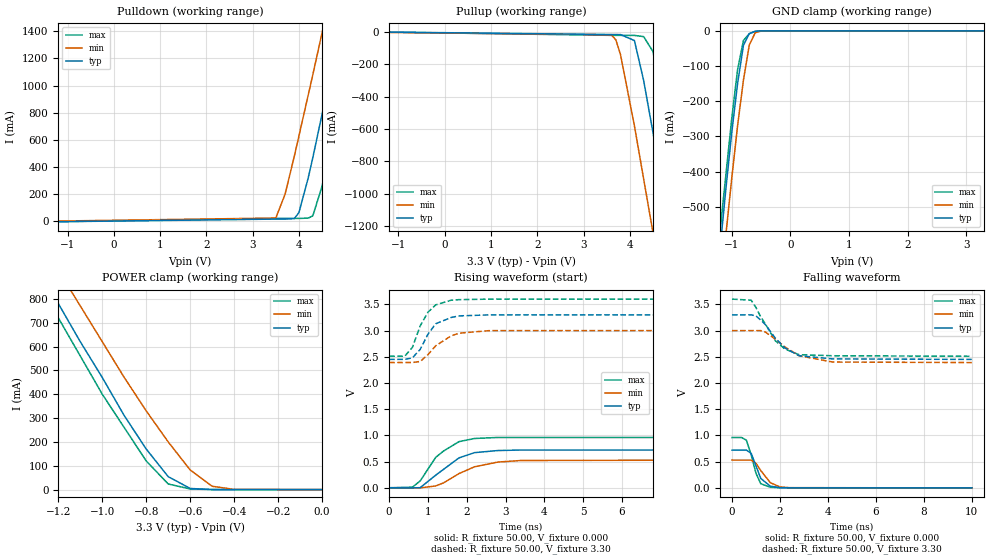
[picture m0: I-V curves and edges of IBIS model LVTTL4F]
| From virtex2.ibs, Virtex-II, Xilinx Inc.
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|   Model LVTTL4F
[Model]   LVTTL4F
Model_type   I/O
Polarity   Non-Inverting
Enable   Active-Low
Vinh = 2.0V
Vinl = 0.8V
Vmeas =   1.40V
Cref =  0pF
Rref =   1.00M
Vref =  0.000V
C_comp   10.00pF   10.00pF   10.00pF
[Temperature Range]   25.00   100.00   0.000
[Voltage Range]   3.30V   3.00V   3.60V
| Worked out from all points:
|   slope of the pulldown table from 0 to 0.495 V, typ, clamps not added: 64.8 ohm
|   slope of the pullup table from 0 to 0.495 V, typ, clamps not added: 95.5 ohm
|   GND clamp passes 1 mA (typ) near -0.57 V on its own axis
|   POWER clamp passes 1 mA (typ) near -0.52 V on its own axis
|   rising waveform, R_fixture 50.00, V_fixture 0.000: 20-80 % time 753ps typ, 888ps min, 672ps max; typ from 0 V to 0.72 V
|   rising waveform, R_fixture 50.00, V_fixture 3.30: 20-80 % time 425ps typ, 594ps min, 422ps max; typ from 2.45 V to 3.3 V
|   falling waveform, R_fixture 50.00, V_fixture 0.000: 20-80 % time 412ps typ, 520ps min, 386ps max; typ from 0.72 V to 0 V
|   falling waveform, R_fixture 50.00, V_fixture 3.30: 20-80 % time 1.01ns typ, 1.16ns min, 918ps max; typ from 3.3 V to 2.45 V
[Pulldown]
| voltage   I(typ)   I(min)   I(max)
-3.3V     -10.77mA   -7.22mA    -12.39mA
3.5V      17.22mA    24.99mA    22.01mA
3.7V      17.28mA    200mA      22.05mA
3.9V      21.2mA     480mA      22.09mA
4V        65.53mA    630mA      22.12mA
4.2V      320mA      930mA      24.26mA
4.3V      470mA      1.08A      41.45mA
4.5V      790mA      1.39A      260mA
4.9V      1.43A      2.01A      890mA
5.1V      1.76A      2.33A      1.21A
5.3V      2.09A      2.64A      1.54A
6.6V      4.26A      4.7A       3.7A
[Pullup]
| voltage   I(typ)   I(min)   I(max)
-3.3V     6.76mA     3.9mA      8.28mA
3.6V      -15.07mA   -16.2mA    -20.1mA
3.7V      -15.12mA   -48.43mA   -20.17mA
3.8V      -15.26mA   -140mA     -20.23mA
4.1V      -52.21mA   -580mA     -20.5mA
4.3V      -300mA     -910mA     -27.9mA
4.5V      -620mA     -1.24A     -120mA
4.7V      -960mA     -1.58A     -410mA
4.9V      -1.3A      -1.91A     -750mA
5.1V      -1.65A     -2.25A     -1.09A
5.3V      -2A        -2.6A      -1.43A
6.6V      -4.31A     -4.84A     -3.73A
[GND_clamp]
| voltage   I(typ)   I(min)   I(max)
-3.3V     -4.3A      -4.31A     -4.26A
-1.2V     -620mA     -740mA     -570mA
-1.1V     -450mA     -580mA     -410mA
-1V       -290mA     -420mA     -250mA
-900mV    -150mA     -270mA     -110mA
-800mV    -41.03mA   -140mA     -27.28mA
-700mV    -7.6mA     -40.21mA   -8.18mA
-600mV    -1.42mA    -5.61mA    -1.62mA
-500mV    -130uA     -670uA     -130uA
3.3V      67.85pA    43.48uA    45.6pA
[POWER_clamp]
| voltage   I(typ)   I(min)   I(max)
-3.3V     4.25A      4.22A      4.2A
-1.3V     940mA      1.07A      880mA
-1.2V     780mA      920mA      720mA
-1.1V     620mA      770mA      560mA
-1V       470mA      620mA      400mA
-900mV    310mA      470mA      260mA
-800mV    170mA      330mA      120mA
-700mV    54.34mA    200mA      23.62mA
-600mV    4.76mA     82.21mA    2.52mA
-500mV    280uA      14.02mA    260uA
-400mV    16.9uA     860uA      14.85uA
0V        67.85pA    2.04nA     61.89pA
[Ramp]
| variable   typ   min   max
dV/dt_r   0.43/0.69n   0.32/0.87n   0.58/0.60n
dV/dt_f   0.51/0.98n   0.37/1.21n   0.65/0.84n
R_load = 50.00
[Rising Waveform]
R_fixture = 50.00
V_fixture = 0.000
| time   V(typ)   V(min)   V(max)
0s        0V         0V         0V
600ps     -2.08mV    -200uV     11.19mV
800ps     1.27mV     -2.1mV     130mV
1.2ns     240mV      34.86mV    580mV
1.4ns     350mV      91.91mV    700mV
1.8ns     570mV      270mV      880mV
2.2ns     670mV      400mV      940mV
2.8ns     710mV      490mV      960mV
3.4ns     720mV      520mV      960mV
10ns      720mV      530mV      960mV
[Rising Waveform]
R_fixture = 50.00
V_fixture = 3.30
V_fixture_min = 3.00
V_fixture_max = 3.60
| time   V(typ)   V(min)   V(max)
0s        2.45V      2.39V      2.51V
400ps     2.45V      2.39V      2.51V
600ps     2.48V      2.39V      2.68V
800ps     2.64V      2.41V      3.09V
1ns       2.93V      2.54V      3.35V
1.2ns     3.13V      2.71V      3.49V
1.6ns     3.25V      2.9V       3.58V
1.8ns     3.28V      2.95V      3.59V
2.6ns     3.3V       3V         3.6V
10ns      3.3V       3V         3.6V
[Falling Waveform]
R_fixture = 50.00
V_fixture = 0.000
| time   V(typ)   V(min)   V(max)
0s        720mV      530mV      960mV
400ps     720mV      530mV      960mV
600ps     720mV      530mV      910mV
800ps     660mV      530mV      630mV
1ns       420mV      470mV      280mV
1.2ns     180mV      330mV      79.39mV
1.6ns     31.69mV    98.14mV    11.24mV
2ns       4.12mV     18.37mV    1.29mV
2.4ns     830uV      3.64mV     310uV
10ns      3.35uV     4.12uV     2.23uV
[Falling Waveform]
R_fixture = 50.00
V_fixture = 3.30
V_fixture_min = 3.00
V_fixture_max = 3.60
| time   V(typ)   V(min)   V(max)
0s        3.3V       3V         3.6V
800ps     3.3V       3V         3.58V
1ns       3.28V      3V         3.44V
1.2ns     3.2V       3V         3.26V
1.4ns     3.11V      2.97V      3.12V
1.8ns     2.86V      2.84V      2.81V
2.2ns     2.67V      2.69V      2.65V
2.8ns     2.52V      2.52V      2.54V
4.2ns     2.46V      2.4V       2.52V
10ns      2.45V      2.39V      2.51V
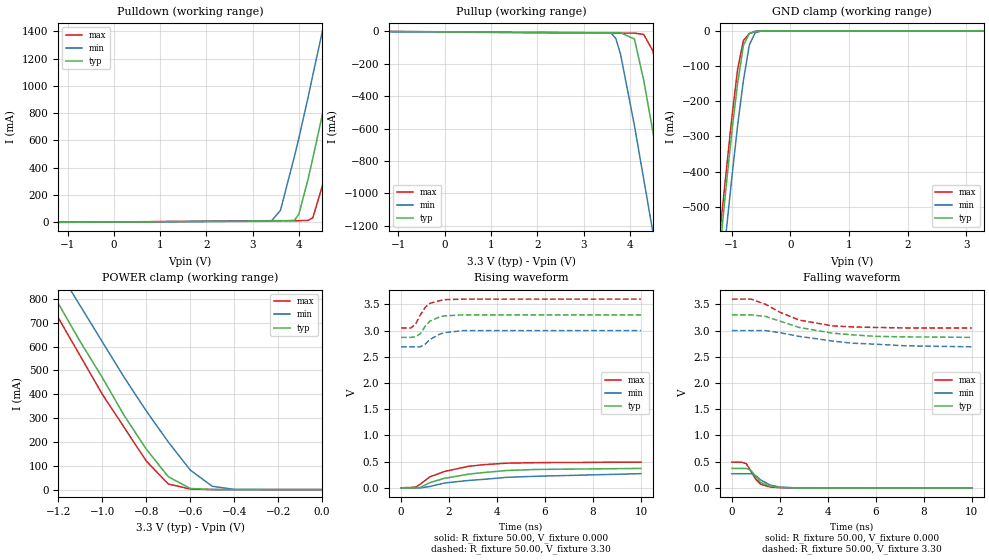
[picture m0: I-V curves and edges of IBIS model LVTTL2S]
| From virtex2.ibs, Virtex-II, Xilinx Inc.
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|   Model LVTTL2S
[Model]   LVTTL2S
Model_type   I/O
Polarity   Non-Inverting
Enable   Active-Low
Vinh = 2.0V
Vinl = 0.8V
Vmeas =   1.40V
Cref =  0pF
Rref =   1.00M
Vref =  0.000V
C_comp   10.00pF   10.00pF   10.00pF
[Temperature Range]   25.00   100.00   0.000
[Voltage Range]   3.30V   3.00V   3.60V
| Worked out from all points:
|   slope of the pulldown table from 0 to 0.495 V, typ, clamps not added: 127 ohm
|   slope of the pullup table from 0 to 0.495 V, typ, clamps not added: 191 ohm
|   GND clamp passes 1 mA (typ) near -0.57 V on its own axis
|   POWER clamp passes 1 mA (typ) near -0.52 V on its own axis
|   rising waveform, R_fixture 50.00, V_fixture 0.000: 20-80 % time 2.43ns typ, 3.86ns min, 1.75ns max; typ from 0 V to 0.37 V
|   rising waveform, R_fixture 50.00, V_fixture 3.30: 20-80 % time 547ps typ, 627ps min, 481ps max; typ from 2.87 V to 3.3 V
|   falling waveform, R_fixture 50.00, V_fixture 0.000: 20-80 % time 485ps typ, 557ps min, 445ps max; typ from 0.37 V to 0 V
|   falling waveform, R_fixture 50.00, V_fixture 3.30: 20-80 % time 2.31ns typ, 3.04ns min, 1.76ns max; typ from 3.3 V to 2.87 V
[Pulldown]
| voltage   I(typ)   I(min)   I(max)
-3.3V     -5.48mA    -3.66mA    -6.34mA
3.4V      8.68mA     7.12mA     11.12mA
3.6V      8.7mA      86.09mA    11.15mA
3.9V      13.03mA    480mA      11.18mA
4V        59.94mA    620mA      11.2mA
4.2V      320mA      920mA      13.51mA
4.3V      470mA      1.08A      32.54mA
4.5V      780mA      1.39A      260mA
4.9V      1.43A      2.01A      880mA
5.1V      1.76A      2.32A      1.21A
5.3V      2.09A      2.64A      1.54A
6.6V      4.26A      4.7A       3.7A
[Pullup]
| voltage   I(typ)   I(min)   I(max)
-3.3V     3.38mA     1.95mA     4.15mA
3.6V      -7.53mA    -10.9mA    -10.05mA
3.7V      -7.56mA    -44.3mA    -10.08mA
3.8V      -7.7mA     -140mA     -10.12mA
4.1V      -46.57mA   -580mA     -10.31mA
4.3V      -300mA     -910mA     -18.03mA
4.5V      -620mA     -1.24A     -120mA
4.7V      -960mA     -1.57A     -410mA
4.9V      -1.3A      -1.91A     -740mA
5.1V      -1.65A     -2.25A     -1.08A
5.3V      -2A        -2.59A     -1.43A
6.6V      -4.3A      -4.83A     -3.73A
[GND_clamp]
| voltage   I(typ)   I(min)   I(max)
-3.3V     -4.3A      -4.31A     -4.26A
-1.2V     -620mA     -740mA     -570mA
-1.1V     -450mA     -580mA     -410mA
-1V       -290mA     -420mA     -250mA
-900mV    -150mA     -270mA     -110mA
-800mV    -41.03mA   -140mA     -27.28mA
-700mV    -7.6mA     -40.21mA   -8.18mA
-600mV    -1.42mA    -5.61mA    -1.62mA
-500mV    -130uA     -670uA     -130uA
3.3V      67.85pA    43.48uA    45.6pA
[POWER_clamp]
| voltage   I(typ)   I(min)   I(max)
-3.3V     4.25A      4.22A      4.2A
-1.3V     940mA      1.07A      880mA
-1.2V     780mA      920mA      720mA
-1.1V     620mA      770mA      560mA
-1V       470mA      620mA      400mA
-900mV    310mA      470mA      260mA
-800mV    170mA      330mA      120mA
-700mV    54.34mA    200mA      23.62mA
-600mV    4.76mA     82.21mA    2.52mA
-500mV    280uA      14.02mA    260uA
-400mV    16.9uA     860uA      14.85uA
0V        67.85pA    2.04nA     61.89pA
[Ramp]
| variable   typ   min   max
dV/dt_r   0.22/2.35n   0.16/3.54n   0.30/1.75n
dV/dt_f   0.26/2.28n   0.18/2.95n   0.33/1.84n
R_load = 50.00
[Rising Waveform]
R_fixture = 50.00
V_fixture = 0.000
| time   V(typ)   V(min)   V(max)
0s        0V         530nV      0V
600ps     -700uV     -26.34uV   11.48mV
800ps     6.24mV     -870uV     71.23mV
1.2ns     99.9mV     25.12mV    210mV
1.8ns     180mV      90.4mV     310mV
2.8ns     260mV      140mV      410mV
3.4ns     290mV      160mV      440mV
4.4ns     330mV      200mV      470mV
5.6ns     350mV      220mV      480mV
10ns      370mV      270mV      490mV
[Rising Waveform]
R_fixture = 50.00
V_fixture = 3.30
V_fixture_min = 3.00
V_fixture_max = 3.60
| time   V(typ)   V(min)   V(max)
0s        2.87V      2.69V      3.05V
400ps     2.87V      2.69V      3.05V
600ps     2.88V      2.69V      3.12V
800ps     2.94V      2.69V      3.3V
1ns       3.08V      2.74V      3.44V
1.2ns     3.18V      2.83V      3.52V
1.6ns     3.26V      2.93V      3.57V
1.8ns     3.28V      2.96V      3.59V
2.6ns     3.3V       3V         3.6V
10ns      3.3V       3V         3.6V
[Falling Waveform]
R_fixture = 50.00
V_fixture = 0.000
| time   V(typ)   V(min)   V(max)
0s        370mV      270mV      490mV
400ps     370mV      270mV      490mV
600ps     370mV      270mV      460mV
800ps     330mV      270mV      310mV
1ns       210mV      230mV      160mV
1.2ns     100mV      150mV      68.41mV
1.6ns     29.86mV    52.35mV    16.7mV
2ns       6.52mV     14.14mV    3.15mV
2.6ns     950uV      2.13mV     600uV
10ns      6.68uV     17.14uV    4.21uV
[Falling Waveform]
R_fixture = 50.00
V_fixture = 3.30
V_fixture_min = 3.00
V_fixture_max = 3.60
| time   V(typ)   V(min)   V(max)
0s        3.3V       3V         3.6V
800ps     3.3V       3V         3.6V
1.4ns     3.27V      3V         3.5V
2ns       3.18V      2.96V      3.35V
2.8ns     3.06V      2.89V      3.2V
4.2ns     2.95V      2.8V       3.09V
5ns       2.92V      2.76V      3.07V
6ns       2.89V      2.74V      3.06V
7.2ns     2.88V      2.71V      3.05V
10ns      2.87V      2.69V      3.05V
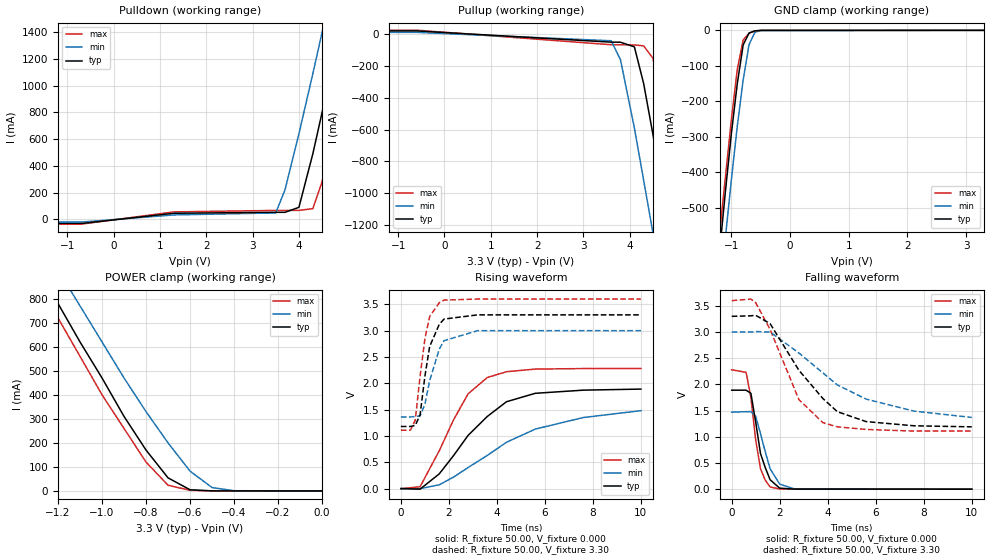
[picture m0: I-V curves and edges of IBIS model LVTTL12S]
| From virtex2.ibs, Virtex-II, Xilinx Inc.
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|   Model LVTTL12S
[Model]   LVTTL12S
Model_type   I/O
Polarity   Non-Inverting
Enable   Active-Low
Vinh = 2.0V
Vinl = 0.8V
Vmeas =   1.40V
Cref =  0pF
Rref =   1.00M
Vref =  0.000V
C_comp   10.00pF   10.00pF   10.00pF
[Temperature Range]   25.00   100.00   0.000
[Voltage Range]   3.30V   3.00V   3.60V
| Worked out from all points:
|   slope of the pulldown table from 0 to 0.495 V, typ, clamps not added: 21.8 ohm
|   slope of the pullup table from 0 to 0.495 V, typ, clamps not added: 29.6 ohm
|   GND clamp passes 1 mA (typ) near -0.57 V on its own axis
|   POWER clamp passes 1 mA (typ) near -0.52 V on its own axis
|   rising waveform, R_fixture 50.00, V_fixture 0.000: 20-80 % time 2.2ns typ, 3.54ns min, 1.54ns max; typ from 0 V to 1.89 V
|   rising waveform, R_fixture 50.00, V_fixture 3.30: 20-80 % time 497ps typ, 588ps min, 448ps max; typ from 1.18 V to 3.3 V
|   falling waveform, R_fixture 50.00, V_fixture 0.000: 20-80 % time 512ps typ, 571ps min, 407ps max; typ from 1.89 V to 0 V
|   falling waveform, R_fixture 50.00, V_fixture 3.30: 20-80 % time 2.06ns typ, 3.11ns min, 1.39ns max; typ from 3.3 V to 1.19 V
[Pulldown]
| voltage   I(typ)   I(min)   I(max)
-3.3V     -32.1mA    -21.58mA   -36.83mA
-700mV    -32.1mA    -21.58mA   -36.83mA
1.3V      44.67mA    32.07mA    55.03mA
3.5V      51.66mA    47.4mA     66.01mA
3.7V      51.79mA    220mA      66.14mA
4V        89.06mA    640mA      66.32mA
4.3V      490mA      1.09A      79.21mA
4.5V      800mA      1.4A       280mA
4.9V      1.45A      2.02A      900mA
5.1V      1.78A      2.34A      1.23A
5.3V      2.11A      2.65A      1.56A
6.6V      4.27A      4.71A      3.72A
[Pullup]
| voltage   I(typ)   I(min)   I(max)
-3.3V     21.9mA     12.73mA    26.65mA
-600mV    21.9mA     12.73mA    26.65mA
3.6V      -48.95mA   -40.18mA   -65.29mA
3.8V      -49.31mA   -160mA     -65.71mA
4.1V      -78.6mA    -590mA     -66.32mA
4.3V      -310mA     -920mA     -72.41mA
4.5V      -630mA     -1.25A     -150mA
4.7V      -970mA     -1.58A     -430mA
4.9V      -1.32A     -1.92A     -760mA
5.1V      -1.66A     -2.26A     -1.1A
5.3V      -2.01A     -2.6A      -1.45A
6.6V      -4.32A     -4.84A     -3.74A
[GND_clamp]
| voltage   I(typ)   I(min)   I(max)
-3.3V     -4.3A      -4.31A     -4.26A
-1.2V     -620mA     -740mA     -570mA
-1.1V     -450mA     -580mA     -410mA
-1V       -290mA     -420mA     -250mA
-900mV    -150mA     -270mA     -110mA
-800mV    -41.03mA   -140mA     -27.28mA
-700mV    -7.6mA     -40.21mA   -8.18mA
-600mV    -1.42mA    -5.61mA    -1.62mA
-500mV    -130uA     -670uA     -130uA
3.3V      67.85pA    43.48uA    45.6pA
[POWER_clamp]
| voltage   I(typ)   I(min)   I(max)
-3.3V     4.25A      4.22A      4.2A
-1.3V     940mA      1.07A      880mA
-1.2V     780mA      920mA      720mA
-1.1V     620mA      770mA      560mA
-1V       470mA      620mA      400mA
-900mV    310mA      470mA      260mA
-800mV    170mA      330mA      120mA
-700mV    54.34mA    200mA      23.62mA
-600mV    4.76mA     82.21mA    2.52mA
-500mV    280uA      14.02mA    260uA
-400mV    16.9uA     860uA      14.85uA
0V        67.85pA    2.04nA     61.89pA
[Ramp]
| variable   typ   min   max
dV/dt_r   1.13/2.21n   0.86/3.37n   1.37/1.56n
dV/dt_f   1.27/2.08n   0.96/3.00n   1.50/1.44n
R_load = 50.00
[Rising Waveform]
R_fixture = 50.00
V_fixture = 0.000
| time   V(typ)   V(min)   V(max)
0s        0V         0V         0V
800ps     -10.81mV   -1.76mV    34.91mV
1.6ns     280mV      71.85mV    720mV
2.2ns     630mV      220mV      1.31V
2.8ns     1.01V      400mV      1.8V
3.6ns     1.37V      630mV      2.11V
4.4ns     1.65V      880mV      2.22V
5.6ns     1.81V      1.13V      2.27V
7.6ns     1.87V      1.35V      2.28V
10ns      1.89V      1.48V      2.28V
[Rising Waveform]
R_fixture = 50.00
V_fixture = 3.30
V_fixture_min = 3.00
V_fixture_max = 3.60
| time   V(typ)   V(min)   V(max)
0s        1.18V      1.36V      1.11V
400ps     1.18V      1.36V      1.11V
600ps     1.2V       1.37V      1.3V
800ps     1.4V       1.38V      2.13V
1ns       2.13V      1.6V       2.84V
1.2ns     2.7V       2.05V      3.27V
1.6ns     3.12V      2.65V      3.53V
1.8ns     3.22V      2.81V      3.58V
3.2ns     3.3V       3V         3.6V
10ns      3.3V       3V         3.6V
[Falling Waveform]
R_fixture = 50.00
V_fixture = 0.000
| time   V(typ)   V(min)   V(max)
0s        1.89V      1.47V      2.28V
600ps     1.89V      1.48V      2.23V
800ps     1.83V      1.48V      1.75V
1ns       1.28V      1.39V      940mV
1.2ns     680mV      1.06V      390mV
1.4ns     410mV      710mV      170mV
1.6ns     180mV      390mV      42.75mV
2ns       18.75mV    95.16mV    2.56mV
2.6ns     1.66mV     6.68mV     1.25mV
10ns      23.01uV    70.16uV    7.96uV
[Falling Waveform]
R_fixture = 50.00
V_fixture = 3.30
V_fixture_min = 3.00
V_fixture_max = 3.60
| time   V(typ)   V(min)   V(max)
0s        3.3V       3V         3.6V
800ps     3.31V      3V         3.63V
1ns       3.32V      3.01V      3.56V
1.6ns     3.16V      3V         3.05V
2.8ns     2.27V      2.6V       1.71V
3.8ns     1.73V      2.22V      1.27V
4.4ns     1.48V      1.99V      1.19V
5.6ns     1.29V      1.72V      1.14V
7.6ns     1.21V      1.49V      1.11V
10ns      1.19V      1.37V      1.11V
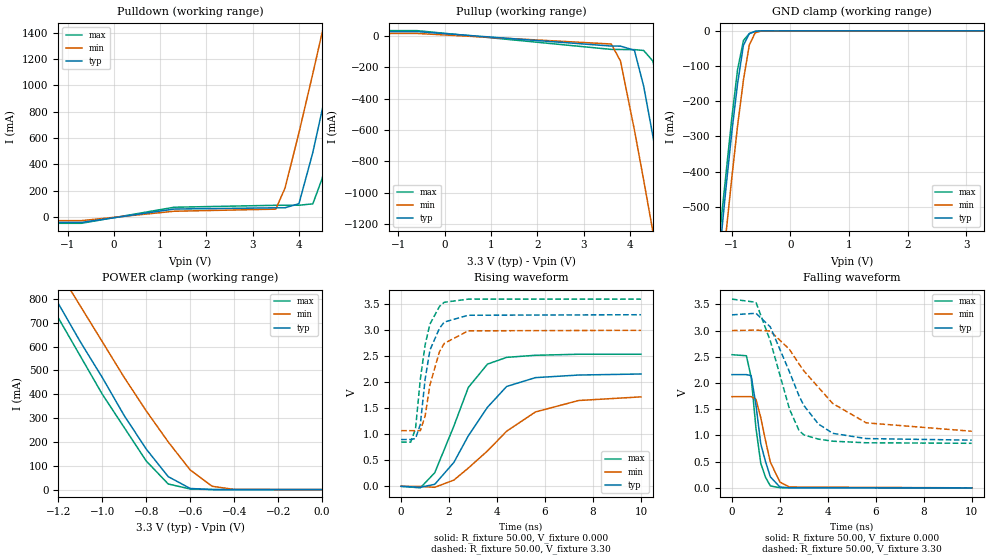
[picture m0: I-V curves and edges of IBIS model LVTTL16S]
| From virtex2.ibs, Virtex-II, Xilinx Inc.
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|   Model LVTTL16S
[Model]   LVTTL16S
Model_type   I/O
Polarity   Non-Inverting
Enable   Active-Low
Vinh = 2.0V
Vinl = 0.8V
Vmeas =   1.40V
Cref =  0pF
Rref =   1.00M
Vref =  0.000V
C_comp   10.00pF   10.00pF   10.00pF
[Temperature Range]   25.00   100.00   0.000
[Voltage Range]   3.30V   3.00V   3.60V
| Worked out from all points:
|   slope of the pulldown table from 0 to 0.495 V, typ, clamps not added: 16.5 ohm
|   slope of the pullup table from 0 to 0.495 V, typ, clamps not added: 22.7 ohm
|   GND clamp passes 1 mA (typ) near -0.57 V on its own axis
|   POWER clamp passes 1 mA (typ) near -0.52 V on its own axis
|   rising waveform, R_fixture 50.00, V_fixture 0.000: 20-80 % time 1.84ns typ, 2.63ns min, 1.31ns max; typ from 0 V to 2.16 V
|   rising waveform, R_fixture 50.00, V_fixture 3.30: 20-80 % time 530ps typ, 595ps min, 504ps max; typ from 0.9 V to 3.3 V
|   falling waveform, R_fixture 50.00, V_fixture 0.000: 20-80 % time 500ps typ, 548ps min, 373ps max; typ from 2.16 V to 0 V
|   falling waveform, R_fixture 50.00, V_fixture 3.30: 20-80 % time 1.45ns typ, 2.18ns min, 1.04ns max; typ from 3.3 V to 0.91 V
[Pulldown]
| voltage   I(typ)   I(min)   I(max)
-3.3V     -42.66mA   -28.71mA   -48.88mA
-700mV    -42.66mA   -28.71mA   -48.88mA
1.3V      59.43mA    42.7mA     73.14mA
3.5V      68.88mA    58.81mA    88.01mA
3.7V      69.04mA    220mA      88.18mA
4V        100mA      640mA      88.42mA
4.3V      490mA      1.09A      98.99mA
4.5V      810mA      1.4A       290mA
4.9V      1.45A      2.03A      910mA
5.1V      1.78A      2.34A      1.24A
5.3V      2.11A      2.66A      1.56A
6.6V      4.28A      4.72A      3.72A
[Pullup]
| voltage   I(typ)   I(min)   I(max)
-3.3V     28.6mA     16.68mA    34.69mA
-600mV    28.6mA     16.68mA    34.69mA
3.6V      -63.99mA   -50.9mA    -85.36mA
3.8V      -64.43mA   -160mA     -85.91mA
4.1V      -90.87mA   -600mA     -86.68mA
4.3V      -320mA     -920mA     -92.25mA
4.5V      -640mA     -1.25A     -160mA
4.7V      -980mA     -1.59A     -440mA
4.9V      -1.32A     -1.93A     -770mA
5.1V      -1.67A     -2.27A     -1.11A
5.3V      -2.02A     -2.61A     -1.46A
6.6V      -4.32A     -4.85A     -3.75A
[GND_clamp]
| voltage   I(typ)   I(min)   I(max)
-3.3V     -4.3A      -4.31A     -4.26A
-1.2V     -620mA     -740mA     -570mA
-1.1V     -450mA     -580mA     -410mA
-1V       -290mA     -420mA     -250mA
-900mV    -150mA     -270mA     -110mA
-800mV    -41.03mA   -140mA     -27.28mA
-700mV    -7.6mA     -40.21mA   -8.18mA
-600mV    -1.42mA    -5.61mA    -1.62mA
-500mV    -130uA     -670uA     -130uA
3.3V      67.85pA    43.48uA    45.6pA
[POWER_clamp]
| voltage   I(typ)   I(min)   I(max)
-3.3V     4.25A      4.22A      4.2A
-1.3V     940mA      1.07A      880mA
-1.2V     780mA      920mA      720mA
-1.1V     620mA      770mA      560mA
-1V       470mA      620mA      400mA
-900mV    310mA      470mA      260mA
-800mV    170mA      330mA      120mA
-700mV    54.34mA    200mA      23.62mA
-600mV    4.76mA     82.21mA    2.52mA
-500mV    280uA      14.02mA    260uA
-400mV    16.9uA     860uA      14.85uA
0V        67.85pA    2.04nA     61.89pA
[Ramp]
| variable   typ   min   max
dV/dt_r   1.29/1.83n   1.03/2.65n   1.52/1.35n
dV/dt_f   1.44/1.44n   1.15/2.23n   1.65/1.03n
R_load = 50.00
[Rising Waveform]
R_fixture = 50.00
V_fixture = 0.000
| time   V(typ)   V(min)   V(max)
0s        0V         0V         0V
800ps     -18.47mV   -1.57mV    -29.99mV
1.4ns     37.83mV    -19.32mV   260mV
2.2ns     460mV      120mV      1.16V
2.8ns     970mV      350mV      1.9V
3.6ns     1.52V      680mV      2.35V
4.4ns     1.92V      1.06V      2.48V
5.6ns     2.09V      1.43V      2.52V
7.4ns     2.14V      1.65V      2.54V
10ns      2.16V      1.72V      2.54V
[Rising Waveform]
R_fixture = 50.00
V_fixture = 3.30
V_fixture_min = 3.00
V_fixture_max = 3.60
| time   V(typ)   V(min)   V(max)
0s        900mV      1.07V      850mV
400ps     900mV      1.07V      850mV
600ps     920mV      1.07V      1.11V
800ps     1.19V      1.07V      2.06V
1ns       2.06V      1.35V      2.72V
1.2ns     2.62V      1.95V      3.12V
1.6ns     3.04V      2.59V      3.46V
1.8ns     3.16V      2.75V      3.54V
2.8ns     3.29V      2.99V      3.6V
10ns      3.3V       3V         3.6V
[Falling Waveform]
R_fixture = 50.00
V_fixture = 0.000
| time   V(typ)   V(min)   V(max)
0s        2.16V      1.74V      2.54V
600ps     2.16V      1.74V      2.52V
800ps     2.14V      1.74V      2.11V
1ns       1.58V      1.69V      1.14V
1.2ns     840mV      1.34V      470mV
1.4ns     500mV      900mV      200mV
1.6ns     210mV      490mV      36.83mV
2ns       14.92mV    110mV      2.43mV
2.4ns     2.24mV     16.23mV    1.64mV
10ns      7.85uV     40.04uV    2.89uV
[Falling Waveform]
R_fixture = 50.00
V_fixture = 3.30
V_fixture_min = 3.00
V_fixture_max = 3.60
| time   V(typ)   V(min)   V(max)
0s        3.3V       3V         3.6V
1ns       3.33V      3.01V      3.54V
1.6ns     3.07V      2.99V      2.8V
2.4ns     2.21V      2.64V      1.5V
2.8ns     1.75V      2.36V      1.09V
3ns       1.57V      2.23V      1.01V
3.6ns     1.22V      1.92V      930mV
4.2ns     1.04V      1.61V      890mV
5.6ns     940mV      1.24V      860mV
10ns      910mV      1.08V      850mV
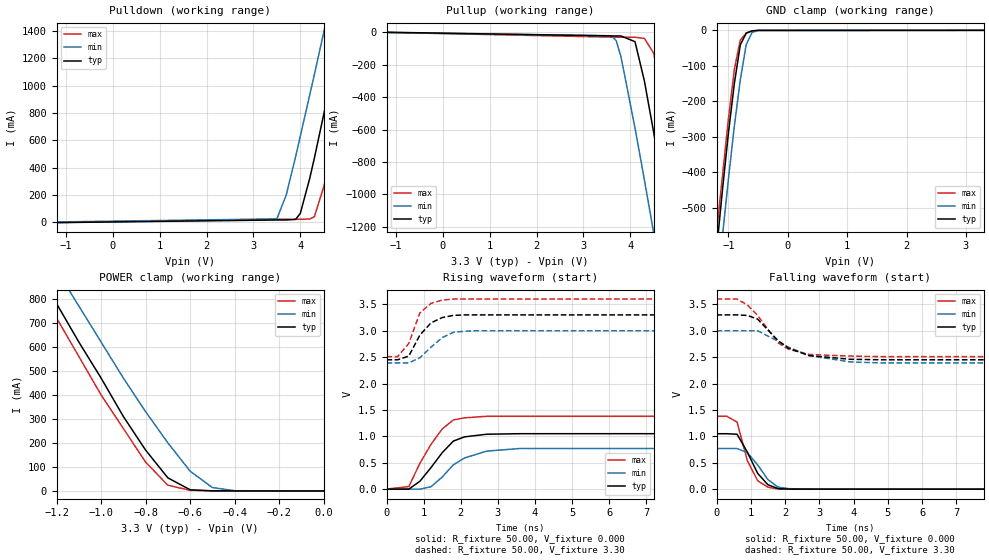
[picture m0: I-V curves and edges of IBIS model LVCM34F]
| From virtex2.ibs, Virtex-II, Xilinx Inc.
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|   Model LVCM34F
[Model]   LVCM34F
Model_type   I/O
Polarity   Non-Inverting
Enable   Active-Low
Vinh = 2.0V
Vinl = 0.8V
Vmeas =   1.65V
Cref =  0pF
Rref =   1.00M
Vref =  0.000V
C_comp   10.00pF   10.00pF   10.00pF
[Temperature Range]   25.00   100.00   0.000
[Voltage Range]   3.30V   3.00V   3.60V
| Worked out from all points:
|   slope of the pulldown table from 0 to 0.495 V, typ, clamps not added: 64.8 ohm
|   slope of the pullup table from 0 to 0.495 V, typ, clamps not added: 63.8 ohm
|   GND clamp passes 1 mA (typ) near -0.57 V on its own axis
|   POWER clamp passes 1 mA (typ) near -0.52 V on its own axis
|   rising waveform, R_fixture 50.00, V_fixture 0.000: 20-80 % time 735ps typ, 821ps min, 708ps max; typ from 0 V to 1.05 V
|   rising waveform, R_fixture 50.00, V_fixture 3.30: 20-80 % time 499ps typ, 591ps min, 408ps max; typ from 2.45 V to 3.3 V
|   falling waveform, R_fixture 50.00, V_fixture 0.000: 20-80 % time 548ps typ, 558ps min, 440ps max; typ from 1.05 V to 0 V
|   falling waveform, R_fixture 50.00, V_fixture 3.30: 20-80 % time 925ps typ, 1.19ns min, 843ps max; typ from 3.3 V to 2.45 V
[Pulldown]
| voltage   I(typ)   I(min)   I(max)
-3.3V     -10.77mA   -7.22mA    -12.39mA
3.5V      17.22mA    24.99mA    22.01mA
3.7V      17.28mA    200mA      22.05mA
3.9V      21.2mA     480mA      22.09mA
4V        65.53mA    630mA      22.12mA
4.2V      320mA      930mA      24.26mA
4.3V      470mA      1.08A      41.45mA
4.5V      790mA      1.39A      260mA
4.9V      1.43A      2.01A      890mA
5.1V      1.76A      2.33A      1.21A
5.3V      2.09A      2.64A      1.54A
6.6V      4.26A      4.7A       3.7A
[Pullup]
| voltage   I(typ)   I(min)   I(max)
-3.3V     10.13mA    5.86mA     12.39mA
3.6V      -22.6mA    -21.51mA   -30.15mA
3.7V      -22.67mA   -52.6mA    -30.25mA
3.8V      -22.83mA   -150mA     -30.34mA
4.1V      -57.92mA   -590mA     -30.68mA
4.3V      -300mA     -910mA     -37.77mA
4.5V      -620mA     -1.24A     -130mA
4.7V      -960mA     -1.58A     -420mA
4.9V      -1.31A     -1.92A     -750mA
5.1V      -1.66A     -2.26A     -1.09A
5.3V      -2.01A     -2.6A      -1.44A
6.6V      -4.31A     -4.84A     -3.73A
[GND_clamp]
| voltage   I(typ)   I(min)   I(max)
-3.3V     -4.3A      -4.31A     -4.26A
-1.2V     -620mA     -740mA     -570mA
-1.1V     -450mA     -580mA     -410mA
-1V       -290mA     -420mA     -250mA
-900mV    -150mA     -270mA     -110mA
-800mV    -41.03mA   -140mA     -27.28mA
-700mV    -7.6mA     -40.21mA   -8.18mA
-600mV    -1.42mA    -5.61mA    -1.62mA
-500mV    -130uA     -670uA     -130uA
3.3V      67.85pA    43.48uA    45.6pA
[POWER_clamp]
| voltage   I(typ)   I(min)   I(max)
-3.3V     4.25A      4.22A      4.2A
-1.3V     940mA      1.07A      880mA
-1.2V     780mA      920mA      720mA
-1.1V     620mA      770mA      560mA
-1V       470mA      620mA      400mA
-900mV    310mA      470mA      260mA
-800mV    170mA      330mA      120mA
-700mV    54.34mA    200mA      23.62mA
-600mV    4.76mA     82.21mA    2.52mA
-500mV    280uA      14.02mA    260uA
-400mV    16.9uA     860uA      14.85uA
0V        67.85pA    2.04nA     61.89pA
[Ramp]
| variable   typ   min   max
dV/dt_r   0.63/0.69n   0.46/0.86n   0.83/0.58n
dV/dt_f   0.51/0.98n   0.37/1.21n   0.65/0.85n
R_load = 50.00
[Rising Waveform]
R_fixture = 50.00
V_fixture = 0.000
| time   V(typ)   V(min)   V(max)
0s        0V         0V         0V
600ps     400uV      -280uV     49.26mV
900ps     150mV      -470uV     490mV
1.2ns     410mV      45.71mV    850mV
1.5ns     690mV      230mV      1.14V
1.8ns     910mV      460mV      1.31V
2.1ns     990mV      590mV      1.35V
2.7ns     1.04V      720mV      1.38V
3.6ns     1.05V      770mV      1.38V
15ns      1.05V      770mV      1.38V
[Rising Waveform]
R_fixture = 50.00
V_fixture = 3.30
V_fixture_min = 3.00
V_fixture_max = 3.60
| time   V(typ)   V(min)   V(max)
0s        2.45V      2.39V      2.51V
300ps     2.45V      2.39V      2.51V
600ps     2.52V      2.39V      2.76V
900ps     2.92V      2.49V      3.34V
1.2ns     3.15V      2.69V      3.52V
1.5ns     3.25V      2.87V      3.58V
1.8ns     3.29V      2.97V      3.6V
2.1ns     3.3V       2.99V      3.6V
2.4ns     3.3V       3V         3.6V
15ns      3.3V       3V         3.6V
[Falling Waveform]
R_fixture = 50.00
V_fixture = 0.000
| time   V(typ)   V(min)   V(max)
0s        1.05V      770mV      1.38V
300ps     1.05V      770mV      1.38V
600ps     1.04V      770mV      1.27V
900ps     700mV      690mV      540mV
1.2ns     300mV      460mV      160mV
1.5ns     83.87mV    180mV      37.44mV
1.8ns     10.26mV    37.81mV    1.95mV
2.1ns     1.97mV     9.84mV     530uV
2.7ns     290uV      1.01mV     110uV
15ns      2uV        2.58uV     2.72uV
[Falling Waveform]
R_fixture = 50.00
V_fixture = 3.30
V_fixture_min = 3.00
V_fixture_max = 3.60
| time   V(typ)   V(min)   V(max)
0s        3.3V       3V         3.6V
600ps     3.3V       3V         3.6V
900ps     3.29V      3V         3.49V
1.2ns     3.22V      3V         3.29V
1.8ns     2.81V      2.8V       2.77V
2.1ns     2.67V      2.69V      2.65V
2.7ns     2.53V      2.53V      2.55V
3.9ns     2.46V      2.41V      2.52V
4.8ns     2.45V      2.39V      2.51V
15ns      2.45V      2.39V      2.51V
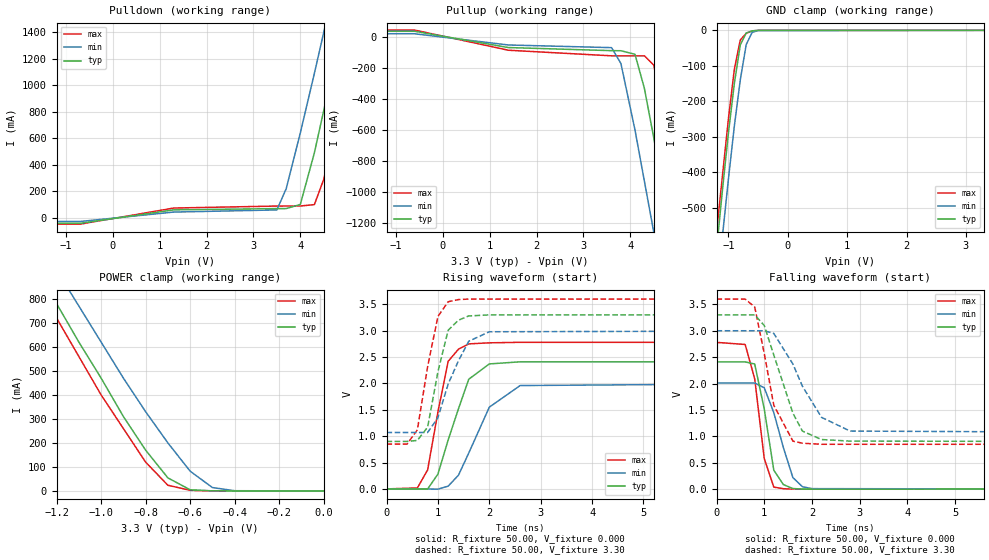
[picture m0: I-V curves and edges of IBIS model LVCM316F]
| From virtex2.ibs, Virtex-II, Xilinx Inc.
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|   Model LVCM316F
[Model]   LVCM316F
Model_type   I/O
Polarity   Non-Inverting
Enable   Active-Low
Vinh = 2.0V
Vinl = 0.8V
Vmeas =   1.65V
Cref =  0pF
Rref =   1.00M
Vref =  0.000V
C_comp   10.00pF   10.00pF   10.00pF
[Temperature Range]   25.00   100.00   0.000
[Voltage Range]   3.30V   3.00V   3.60V
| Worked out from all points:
|   slope of the pulldown table from 0 to 0.495 V, typ, clamps not added: 16.5 ohm
|   slope of the pullup table from 0 to 0.495 V, typ, clamps not added: 16.9 ohm
|   GND clamp passes 1 mA (typ) near -0.57 V on its own axis
|   POWER clamp passes 1 mA (typ) near -0.52 V on its own axis
|   rising waveform, R_fixture 50.00, V_fixture 0.000: 20-80 % time 484ps typ, 581ps min, 324ps max; typ from 0 V to 2.41 V
|   rising waveform, R_fixture 50.00, V_fixture 3.30: 20-80 % time 312ps typ, 466ps min, 307ps max; typ from 0.9 V to 3.3 V
|   falling waveform, R_fixture 50.00, V_fixture 0.000: 20-80 % time 275ps typ, 403ps min, 250ps max; typ from 2.41 V to 0 V
|   falling waveform, R_fixture 50.00, V_fixture 3.30: 20-80 % time 535ps typ, 648ps min, 397ps max; typ from 3.3 V to 0.9 V
[Pulldown]
| voltage   I(typ)   I(min)   I(max)
-3.3V     -42.66mA   -28.71mA   -48.88mA
-700mV    -42.66mA   -28.71mA   -48.88mA
1.3V      59.43mA    42.7mA     73.14mA
3.5V      68.88mA    58.81mA    88.01mA
3.7V      69.04mA    220mA      88.18mA
4V        100mA      640mA      88.42mA
4.3V      490mA      1.09A      98.99mA
4.5V      810mA      1.4A       290mA
4.9V      1.45A      2.03A      910mA
5.1V      1.78A      2.34A      1.24A
5.3V      2.11A      2.66A      1.56A
6.6V      4.28A      4.72A      3.72A
[Pullup]
| voltage   I(typ)   I(min)   I(max)
-3.3V     38.58mA    22.62mA    46.62mA
-600mV    38.58mA    22.62mA    46.62mA
1.4V      -66.48mA   -49.89mA   -83.88mA
3.6V      -86.56mA   -67.02mA   -120mA
3.8V      -87.11mA   -170mA     -120mA
4.1V      -110mA     -600mA     -120mA
4.3V      -330mA     -930mA     -120mA
4.5V      -650mA     -1.26A     -180mA
4.9V      -1.33A     -1.93A     -780mA
5.1V      -1.68A     -2.27A     -1.12A
5.3V      -2.03A     -2.61A     -1.46A
6.6V      -4.33A     -4.85A     -3.76A
[GND_clamp]
| voltage   I(typ)   I(min)   I(max)
-3.3V     -4.3A      -4.31A     -4.26A
-1.2V     -620mA     -740mA     -570mA
-1.1V     -450mA     -580mA     -410mA
-1V       -290mA     -420mA     -250mA
-900mV    -150mA     -270mA     -110mA
-800mV    -41.03mA   -140mA     -27.28mA
-700mV    -7.6mA     -40.21mA   -8.18mA
-600mV    -1.42mA    -5.61mA    -1.62mA
-500mV    -130uA     -670uA     -130uA
3.3V      67.85pA    43.48uA    45.6pA
[POWER_clamp]
| voltage   I(typ)   I(min)   I(max)
-3.3V     4.25A      4.22A      4.2A
-1.3V     940mA      1.07A      880mA
-1.2V     780mA      920mA      720mA
-1.1V     620mA      770mA      560mA
-1V       470mA      620mA      400mA
-900mV    310mA      470mA      260mA
-800mV    170mA      330mA      120mA
-700mV    54.34mA    200mA      23.62mA
-600mV    4.76mA     82.21mA    2.52mA
-500mV    280uA      14.02mA    260uA
-400mV    16.9uA     860uA      14.85uA
0V        67.85pA    2.04nA     61.89pA
[Ramp]
| variable   typ   min   max
dV/dt_r   1.45/0.40n   1.20/0.55n   1.67/0.31n
dV/dt_f   1.44/0.45n   1.16/0.63n   1.65/0.35n
R_load = 50.00
[Rising Waveform]
R_fixture = 50.00
V_fixture = 0.000
| time   V(typ)   V(min)   V(max)
0s        0V         0V         0V
600ps     -2.99mV    52.17uV    18.17mV
800ps     -1.05mV    -2mV       360mV
1ns       280mV      -5mV       1.46V
1.2ns     930mV      52.91mV    2.42V
1.4ns     1.52V      260mV      2.65V
1.6ns     2.08V      680mV      2.75V
2ns       2.37V      1.55V      2.77V
2.6ns     2.41V      1.96V      2.78V
10ns      2.41V      2.01V      2.78V
[Rising Waveform]
R_fixture = 50.00
V_fixture = 3.30
V_fixture_min = 3.00
V_fixture_max = 3.60
| time   V(typ)   V(min)   V(max)
0s        900mV      1.07V      850mV
400ps     900mV      1.07V      850mV
600ps     920mV      1.07V      1.12V
800ps     1.17V      1.07V      2.32V
1ns       2.22V      1.35V      3.27V
1.2ns     3.01V      1.99V      3.55V
1.4ns     3.2V       2.43V      3.59V
1.6ns     3.28V      2.8V       3.6V
2ns       3.3V       2.98V      3.6V
10ns      3.3V       3V         3.6V
[Falling Waveform]
R_fixture = 50.00
V_fixture = 0.000
| time   V(typ)   V(min)   V(max)
0s        2.41V      2.01V      2.78V
600ps     2.41V      2.01V      2.74V
800ps     2.37V      2.01V      2.09V
1ns       1.52V      1.92V      580mV
1.2ns     360mV      1.45V      39.34mV
1.4ns     87.06mV    790mV      8.72mV
1.6ns     11.5mV     220mV      1.47mV
1.8ns     2.57mV     46.08mV    630uV
2ns       920uV      9.92mV     270uV
10ns      980nV      2.32uV     -4.81uV
[Falling Waveform]
R_fixture = 50.00
V_fixture = 3.30
V_fixture_min = 3.00
V_fixture_max = 3.60
| time   V(typ)   V(min)   V(max)
0s        3.3V       3V         3.6V
600ps     3.3V       3V         3.6V
800ps     3.3V       3V         3.45V
1ns       3.1V       3V         2.57V
1.2ns     2.54V      2.95V      1.59V
1.6ns     1.44V      2.37V      910mV
1.8ns     1.1V       1.95V      870mV
2.2ns     940mV      1.36V      850mV
2.8ns     910mV      1.1V       850mV
10ns      900mV      1.07V      850mV
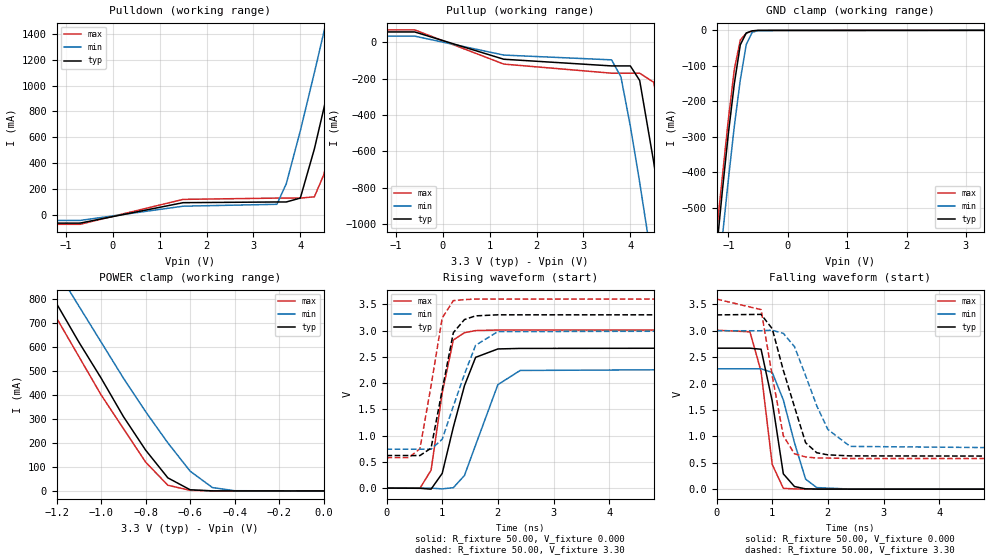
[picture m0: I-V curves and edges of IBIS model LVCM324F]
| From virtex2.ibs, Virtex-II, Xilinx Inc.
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|   Model LVCM324F
[Model]   LVCM324F
Model_type   I/O
Polarity   Non-Inverting
Enable   Active-Low
Vinh = 2.0V
Vinl = 0.8V
Vmeas =   1.65V
Cref =  0pF
Rref =   1.00M
Vref =  0.000V
C_comp   10.00pF   10.00pF   10.00pF
[Temperature Range]   25.00   100.00   0.000
[Voltage Range]   3.30V   3.00V   3.60V
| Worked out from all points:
|   slope of the pulldown table from 0 to 0.495 V, typ, clamps not added: 11.1 ohm
|   slope of the pullup table from 0 to 0.495 V, typ, clamps not added: 11.5 ohm
|   GND clamp passes 1 mA (typ) near -0.57 V on its own axis
|   POWER clamp passes 1 mA (typ) near -0.52 V on its own axis
|   rising waveform, R_fixture 50.00, V_fixture 0.000: 20-80 % time 411ps typ, 465ps min, 283ps max; typ from 0 V to 2.67 V
|   rising waveform, R_fixture 50.00, V_fixture 3.30: 20-80 % time 293ps typ, 454ps min, 290ps max; typ from 0.62 V to 3.3 V
|   falling waveform, R_fixture 50.00, V_fixture 0.000: 20-80 % time 260ps typ, 374ps min, 232ps max; typ from 2.67 V to 0 V
|   falling waveform, R_fixture 50.00, V_fixture 3.30: 20-80 % time 449ps typ, 517ps min, 305ps max; typ from 3.3 V to 0.62 V
[Pulldown]
| voltage   I(typ)   I(min)   I(max)
-3.3V     -63.55mA   -42.85mA   -72.64mA
-700mV    -63.55mA   -42.85mA   -72.64mA
1.5V      94.54mA    67.4mA     120mA
3.5V      100mA      82mA       130mA
3.7V      100mA      240mA      130mA
4V        130mA      650mA      130mA
4.3V      510mA      1.1A       140mA
4.5V      820mA      1.41A      310mA
4.9V      1.47A      2.04A      930mA
5.1V      1.79A      2.35A      1.25A
5.3V      2.12A      2.67A      1.58A
6.6V      4.29A      4.73A      3.74A
[Pullup]
| voltage   I(typ)   I(min)   I(max)
-3.3V     56.69mA    33.54mA    68.06mA
-600mV    56.69mA    33.54mA    68.06mA
1.3V      -93.32mA   -70.46mA   -120mA
3.6V      -130mA     -96.72mA   -170mA
3.8V      -130mA     -190mA     -170mA
4V        -130mA     -460mA     -170mA
4.2V      -210mA     -770mA     -170mA
4.5V      -660mA     -1.27A     -220mA
4.9V      -1.34A     -1.94A     -800mA
5.1V      -1.69A     -2.28A     -1.14A
5.3V      -2.04A     -2.62A     -1.48A
6.6V      -4.34A     -4.86A     -3.78A
[GND_clamp]
| voltage   I(typ)   I(min)   I(max)
-3.3V     -4.3A      -4.31A     -4.26A
-1.2V     -620mA     -740mA     -570mA
-1.1V     -450mA     -580mA     -410mA
-1V       -290mA     -420mA     -250mA
-900mV    -150mA     -270mA     -110mA
-800mV    -41.03mA   -140mA     -27.28mA
-700mV    -7.6mA     -40.21mA   -8.18mA
-600mV    -1.42mA    -5.61mA    -1.62mA
-500mV    -130uA     -670uA     -130uA
3.3V      67.85pA    43.48uA    45.6pA
[POWER_clamp]
| voltage   I(typ)   I(min)   I(max)
-3.3V     4.25A      4.22A      4.2A
-1.3V     940mA      1.07A      880mA
-1.2V     780mA      920mA      720mA
-1.1V     620mA      770mA      560mA
-1V       470mA      620mA      400mA
-900mV    310mA      470mA      260mA
-800mV    170mA      330mA      120mA
-700mV    54.34mA    200mA      23.62mA
-600mV    4.76mA     82.21mA    2.52mA
-500mV    280uA      14.02mA    260uA
-400mV    16.9uA     860uA      14.85uA
0V        67.85pA    2.04nA     61.89pA
[Ramp]
| variable   typ   min   max
dV/dt_r   1.60/0.31n   1.37/0.44n   1.81/0.24n
dV/dt_f   1.61/0.36n   1.36/0.50n   1.81/0.28n
R_load = 50.00
[Rising Waveform]
R_fixture = 50.00
V_fixture = 0.000
| time   V(typ)   V(min)   V(max)
0s        0V         0V         0V
600ps     -3.4mV     110uV      -3.67mV
800ps     -20.51mV   -1.36mV    340mV
1ns       280mV      -15.14mV   1.81V
1.2ns     1.16V      7.51mV     2.82V
1.4ns     1.95V      240mV      2.96V
1.6ns     2.49V      820mV      3V
2ns       2.65V      1.97V      3.01V
2.4ns     2.66V      2.24V      3.01V
10ns      2.67V      2.28V      3.01V
[Rising Waveform]
R_fixture = 50.00
V_fixture = 3.30
V_fixture_min = 3.00
V_fixture_max = 3.60
| time   V(typ)   V(min)   V(max)
0s        620mV      740mV      580mV
400ps     620mV      740mV      580mV
600ps     620mV      740mV      750mV
800ps     760mV      740mV      1.95V
1ns       1.87V      930mV      3.24V
1.2ns     2.96V      1.56V      3.57V
1.4ns     3.21V      2.17V      3.59V
1.6ns     3.28V      2.72V      3.6V
2ns       3.3V       2.98V      3.6V
10ns      3.3V       3V         3.6V
[Falling Waveform]
R_fixture = 50.00
V_fixture = 0.000
| time   V(typ)   V(min)   V(max)
0s        2.67V      2.28V      3.01V
600ps     2.67V      2.28V      2.98V
800ps     2.65V      2.28V      2.23V
1ns       1.67V      2.21V      470mV
1.2ns     290mV      1.69V      16.04mV
1.4ns     49.91mV    880mV      4.63mV
1.6ns     6.1mV      190mV      1.52mV
1.8ns     2.09mV     30.01mV    660uV
2.4ns     280uV      1.39mV     67.14uV
10ns      2.82uV     -2.06uV    6.36uV
[Falling Waveform]
R_fixture = 50.00
V_fixture = 3.30
V_fixture_min = 3.00
V_fixture_max = 3.60
| time   V(typ)   V(min)   V(max)
0s        3.3V       3V         3.6V
800ps     3.31V      3V         3.4V
1ns       3.04V      3.01V      2.15V
1.2ns     2.25V      2.95V      1.01V
1.4ns     1.56V      2.7V       670mV
1.6ns     880mV      2.15V      610mV
1.8ns     690mV      1.58V      590mV
2ns       650mV      1.13V      590mV
2.4ns     630mV      810mV      580mV
10ns      620mV      740mV      580mV
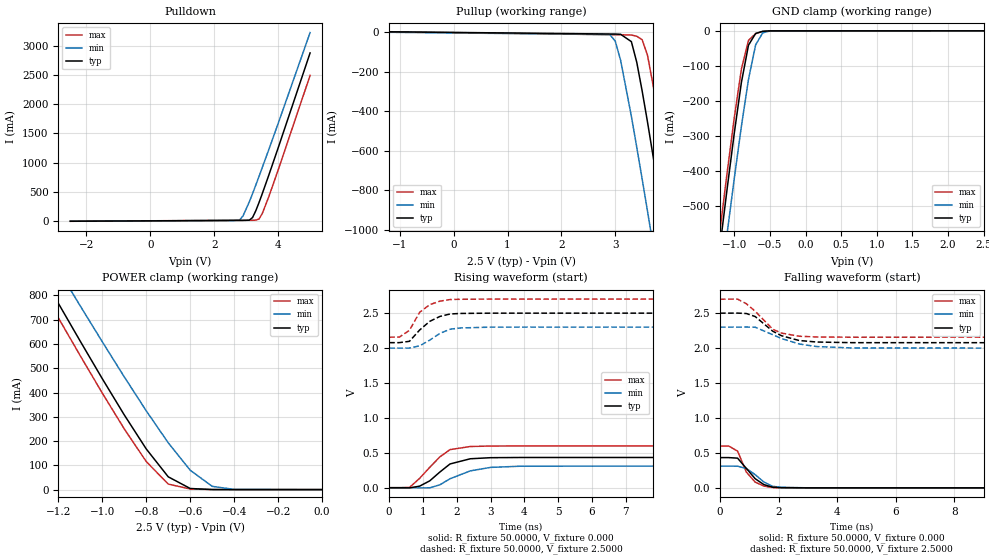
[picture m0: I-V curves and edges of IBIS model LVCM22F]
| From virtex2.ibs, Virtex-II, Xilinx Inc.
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|   Model LVCM22F
[Model]   LVCM22F
Model_type   I/O
Polarity   Non-Inverting
Enable   Active-Low
Vinh = 1.7V
Vinl = 0.7V
Vmeas =   1.2500V
Cref =  0pF
Rref =   1.0000M
Vref =  0.000V
C_comp   7.0000pF   6.0000pF   8.0000pF
[Temperature Range]   25.0000   100.0000   0.000
[Voltage Range]   2.5000V   2.3000V   2.7000V
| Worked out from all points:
|   slope of the pulldown table from 0 to 0.375 V, typ, clamps not added: 122 ohm
|   slope of the pullup table from 0 to 0.375 V, typ, clamps not added: 116 ohm
|   GND clamp passes 1 mA (typ) near -0.57 V on its own axis
|   POWER clamp passes 1 mA (typ) near -0.52 V on its own axis
|   rising waveform, R_fixture 50.0000, V_fixture 0.000: 20-80 % time 684ps typ, 900ps min, 739ps max; typ from 0 V to 0.433 V
|   rising waveform, R_fixture 50.0000, V_fixture 2.5000: 20-80 % time 622ps typ, 653ps min, 505ps max; typ from 2.08 V to 2.5 V
|   falling waveform, R_fixture 50.0000, V_fixture 0.000: 20-80 % time 596ps typ, 605ps min, 475ps max; typ from 0.433 V to 0 V
|   falling waveform, R_fixture 50.0000, V_fixture 2.5000: 20-80 % time 896ps typ, 1.11ns min, 809ps max; typ from 2.5 V to 2.08 V
[Pulldown]
| voltage   I(typ)   I(min)   I(max)
-2.5V     -5.481mA   -3.66mA    -6.342mA
2.6V      8.571mA    6.23mA     11mA
2.8V      8.605mA    18.9mA     11.04mA
2.9V      8.633mA    83.75mA    11.06mA
3.1V      12.78mA    327.5mA    11.1mA
3.2V      58.36mA    467.2mA    11.32mA
3.3V      171.9mA    611.7mA    13.35mA
3.4V      311.3mA    758.9mA    31.74mA
3.5V      460.3mA    908mA      121.4mA
3.7V      770.7mA    1.209A     402.1mA
4V        1.249A     1.668A     870.2mA
5V        2.877A     3.226A     2.492A
[Pullup]
| voltage   I(typ)   I(min)   I(max)
-2.5V     5.869mA    3.31mA     7.396mA
2.9V      -9.073mA   -11.85mA   -12.55mA
3V        -9.217mA   -45.04mA   -12.6mA
3.1V      -10.44mA   -142mA     -12.65mA
3.3V      -47.69mA   -425.5mA   -14.17mA
3.4V      -152.4mA   -582.2mA   -20.41mA
3.5V      -297mA     -743mA     -38.14mA
3.6V      -455.4mA   -906.4mA   -116.8mA
3.8V      -788.3mA   -1.238A    -410.7mA
4V        -1.13A     -1.574A    -743.1mA
4.2V      -1.477A    -1.913A    -1.085A
5V        -2.884A    -3.282A    -2.488A
[GND_clamp]
| voltage   I(typ)   I(min)   I(max)
-2.5V     -2.881A    -2.936A    -2.838A
-1.2V     -617mA     -740.6mA   -570.6mA
-1.1V     -452.1mA   -579.7mA   -406.1mA
-1V       -293.4mA   -423mA     -249mA
-900mV    -148mA     -273.4mA   -110.1mA
-800mV    -41mA      -138.5mA   -27.22mA
-700mV    -7.569mA   -40.19mA   -8.128mA
-600mV    -1.403mA   -5.589mA   -1.597mA
-500mV    -127.6uA   -662.5uA   -122uA
2.5V      397.5nA    2.548uA    351.3nA
[POWER_clamp]
| voltage   I(typ)   I(min)   I(max)
-2.5V     2.874A     2.908A     2.816A
-1.3V     925.8mA    1.055A     866.1mA
-1.2V     767.5mA    905.5mA    707.7mA
-1.1V     610.9mA    756.3mA    551.2mA
-1V       456.9mA    609.1mA    397.6mA
-900mV    307.7mA    464.5mA    250.2mA
-800mV    167.5mA    324.6mA    115.6mA
-700mV    52.75mA    192.9mA    22.81mA
-600mV    4.571mA    79.88mA    2.444mA
-500mV    271.3uA    13.45mA    251.8uA
-400mV    16.93uA    820.9uA    15.04uA
0V        397.5nA    368nA      428.7nA
[Ramp]
| variable   typ   min   max
dV/dt_r   0.2598/0.7377n   0.1865/0.9257n   0.3590/0.6380n
dV/dt_f   0.2538/0.9437n   0.1806/1.1440n   0.3270/0.8292n
R_load = 50.0000
[Rising Waveform]
R_fixture = 50.0000
V_fixture = 0.000
| time   V(typ)   V(min)   V(max)
0s        14.97uV    15.8uV     15.19uV
600ps     -1.679mV   -36.34uV   3.043mV
900ps     22.16mV    -2.088mV   133.4mV
1.2ns     98.34mV    -1.759mV   291.9mV
1.5ns     224.7mV    41.66mV    441.5mV
1.8ns     340.1mV    128.2mV    545.6mV
2.4ns     414.5mV    241.2mV    590mV
3ns       429.9mV    290.8mV    596.7mV
3.9ns     432.8mV    308.3mV    598mV
15ns      433.1mV    310.8mV    598.4mV
[Rising Waveform]
R_fixture = 50.0000
V_fixture = 2.5000
V_fixture_min = 2.3000
V_fixture_max = 2.7000
| time   V(typ)   V(min)   V(max)
0s        2.077V     1.999V     2.155V
300ps     2.077V     1.999V     2.156V
600ps     2.096V     1.999V     2.253V
900ps     2.257V     2.031V     2.511V
1.2ns     2.382V     2.113V     2.621V
1.5ns     2.452V     2.209V     2.671V
1.8ns     2.487V     2.269V     2.694V
2.1ns     2.495V     2.287V     2.698V
3ns       2.499V     2.299V     2.7V
15ns      2.5V       2.3V       2.7V
[Falling Waveform]
R_fixture = 50.0000
V_fixture = 0.000
| time   V(typ)   V(min)   V(max)
0s        433.1mV    310.8mV    598.4mV
300ps     433.1mV    310.8mV    598.5mV
600ps     425.1mV    310.4mV    525.7mV
900ps     278.3mV    277.1mV    225.1mV
1.2ns     131mV      188.9mV    82.29mV
1.5ns     46.23mV    82.79mV    25.35mV
1.8ns     8.845mV    21.84mV    4.019mV
2.1ns     2.591mV    7.985mV    964.4uV
3ns       114.5uV    414.1uV    46.86uV
15ns      1.966uV    2.77uV     2.285uV
[Falling Waveform]
R_fixture = 50.0000
V_fixture = 2.5000
V_fixture_min = 2.3000
V_fixture_max = 2.7000
| time   V(typ)   V(min)   V(max)
0s        2.5V       2.3V       2.7V
600ps     2.501V     2.3V       2.701V
900ps     2.495V     2.302V     2.635V
1.2ns     2.452V     2.299V     2.528V
1.8ns     2.242V     2.192V     2.27V
2.1ns     2.177V     2.137V     2.215V
2.7ns     2.109V     2.059V     2.17V
3.3ns     2.087V     2.022V     2.159V
4.5ns     2.078V     2.002V     2.156V
15ns      2.077V     1.999V     2.155V
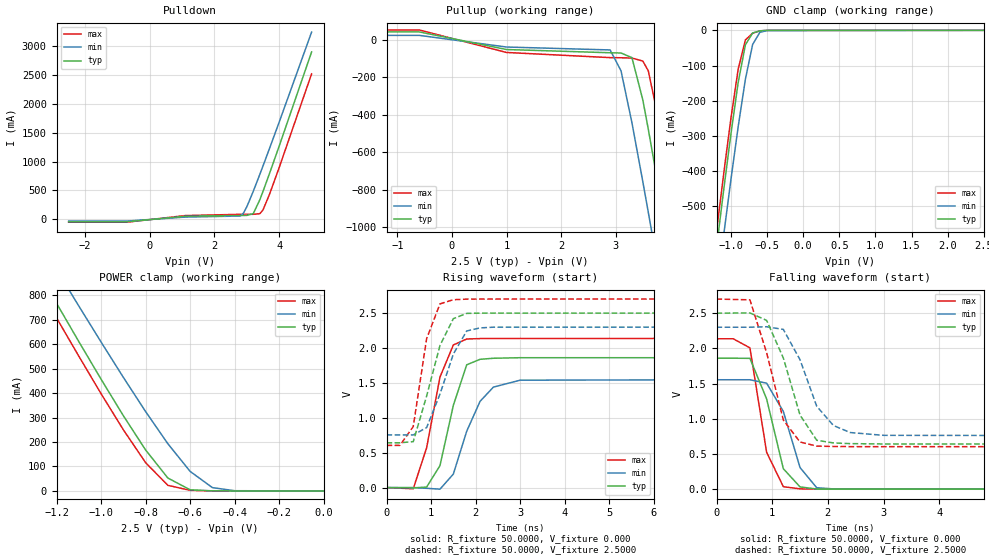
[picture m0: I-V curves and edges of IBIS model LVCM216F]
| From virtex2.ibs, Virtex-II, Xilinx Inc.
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|   Model LVCM216F
[Model]   LVCM216F
Model_type   I/O
Polarity   Non-Inverting
Enable   Active-Low
Vinh = 1.7V
Vinl = 0.7V
Vmeas =   1.2500V
Cref =  0pF
Rref =   1.0000M
Vref =  0.000V
C_comp   7.0000pF   6.0000pF   8.0000pF
[Temperature Range]   25.0000   100.0000   0.000
[Voltage Range]   2.5000V   2.3000V   2.7000V
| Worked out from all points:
|   slope of the pulldown table from 0 to 0.375 V, typ, clamps not added: 15.9 ohm
|   slope of the pullup table from 0 to 0.375 V, typ, clamps not added: 15.8 ohm
|   GND clamp passes 1 mA (typ) near -0.57 V on its own axis
|   POWER clamp passes 1 mA (typ) near -0.52 V on its own axis
|   rising waveform, R_fixture 50.0000, V_fixture 0.000: 20-80 % time 441ps typ, 554ps min, 455ps max; typ from 0 V to 1.86 V
|   rising waveform, R_fixture 50.0000, V_fixture 2.5000: 20-80 % time 510ps typ, 544ps min, 354ps max; typ from 0.641 V to 2.5 V
|   falling waveform, R_fixture 50.0000, V_fixture 0.000: 20-80 % time 383ps typ, 403ps min, 299ps max; typ from 1.86 V to 0 V
|   falling waveform, R_fixture 50.0000, V_fixture 2.5000: 20-80 % time 482ps typ, 531ps min, 424ps max; typ from 2.5 V to 0.641 V
[Pulldown]
| voltage   I(typ)   I(min)   I(max)
-2.5V     -42.66mA   -28.72mA   -48.89mA
-700mV    -42.66mA   -28.72mA   -48.89mA
1.1V      54.26mA    39.33mA    65.96mA
2.8V      68.19mA    57.71mA    87.25mA
2.9V      68.32mA    111.5mA    87.38mA
3V        68.55mA    218.2mA    87.5mA
3.2V      99.9mA     486.2mA    87.82mA
3.4V      336.9mA    776.8mA    97.97mA
3.5V      484.2mA    925.7mA    163.6mA
3.7V      793.2mA    1.227A     433.3mA
4V        1.27A      1.685A     898.5mA
5V        2.898A     3.242A     2.519A
[Pullup]
| voltage   I(typ)   I(min)   I(max)
-2.5V     43.6mA     25.02mA    54.04mA
-600mV    43.6mA     25.02mA    54.04mA
1V        -50.63mA   -37.28mA   -66.4mA
2.9V      -67.94mA   -52.89mA   -93.97mA
3.1V      -69.23mA   -164.7mA   -94.73mA
3.3V      -94.13mA   -442.3mA   -96.09mA
3.5V      -320.7mA   -758.3mA   -112.6mA
3.6V      -476.8mA   -921.4mA   -164.7mA
3.8V      -807.9mA   -1.252A    -441.1mA
4V        -1.149A    -1.588A    -770.5mA
4.2V      -1.496A    -1.927A    -1.112A
5V        -2.902A    -3.296A    -2.513A
[GND_clamp]
| voltage   I(typ)   I(min)   I(max)
-2.5V     -2.881A    -2.936A    -2.838A
-1.2V     -617mA     -740.6mA   -570.6mA
-1.1V     -452.1mA   -579.7mA   -406.1mA
-1V       -293.4mA   -423mA     -249mA
-900mV    -148mA     -273.4mA   -110.1mA
-800mV    -41mA      -138.5mA   -27.22mA
-700mV    -7.569mA   -40.19mA   -8.128mA
-600mV    -1.403mA   -5.589mA   -1.597mA
-500mV    -127.6uA   -662.5uA   -122uA
2.5V      397.5nA    2.548uA    351.3nA
[POWER_clamp]
| voltage   I(typ)   I(min)   I(max)
-2.5V     2.874A     2.908A     2.816A
-1.3V     925.8mA    1.055A     866.1mA
-1.2V     767.5mA    905.5mA    707.7mA
-1.1V     610.9mA    756.3mA    551.2mA
-1V       456.9mA    609.1mA    397.6mA
-900mV    307.7mA    464.5mA    250.2mA
-800mV    167.5mA    324.6mA    115.6mA
-700mV    52.75mA    192.9mA    22.81mA
-600mV    4.571mA    79.88mA    2.444mA
-500mV    271.3uA    13.45mA    251.8uA
-400mV    16.93uA    820.9uA    15.04uA
0V        397.5nA    368nA      428.7nA
[Ramp]
| variable   typ   min   max
dV/dt_r   1.1160/0.4046n   0.9324/0.5868n   1.2816/0.3094n
dV/dt_f   1.1152/0.3860n   0.9274/0.5390n   1.2578/0.2889n
R_load = 50.0000
[Rising Waveform]
R_fixture = 50.0000
V_fixture = 0.000
| time   V(typ)   V(min)   V(max)
0s        5.495uV    6.591uV    5.258uV
600ps     -5.26mV    44.72uV    -17.55mV
900ps     6.875mV    -10.79mV   569.3mV
1.2ns     314mV      -23.11mV   1.582V
1.5ns     1.177V     193.1mV    2.042V
1.8ns     1.758V     806.3mV    2.128V
2.1ns     1.837V     1.235V     2.134V
2.4ns     1.852V     1.439V     2.136V
3ns       1.86V      1.538V     2.136V
15ns      1.86V      1.554V     2.136V
[Rising Waveform]
R_fixture = 50.0000
V_fixture = 2.5000
V_fixture_min = 2.3000
V_fixture_max = 2.7000
| time   V(typ)   V(min)   V(max)
0s        641.4mV    754.3mV    603.7mV
300ps     641.4mV    754.3mV    603.7mV
600ps     657.6mV    754.1mV    873.5mV
900ps     1.31V      858.6mV    2.131V
1.2ns     2.035V     1.339V     2.631V
1.5ns     2.419V     1.912V     2.691V
1.8ns     2.495V     2.243V     2.699V
2.1ns     2.498V     2.287V     2.7V
2.4ns     2.499V     2.297V     2.7V
15ns      2.5V       2.3V       2.7V
[Falling Waveform]
R_fixture = 50.0000
V_fixture = 0.000
| time   V(typ)   V(min)   V(max)
0s        1.86V      1.554V     2.136V
300ps     1.86V      1.554V     2.136V
600ps     1.858V     1.554V     2.007V
900ps     1.281V     1.505V     524.1mV
1.2ns     290.4mV    1.104V     35.43mV
1.5ns     32.01mV    306.8mV    4.39mV
1.8ns     1.819mV    20.23mV    170.1uV
2.1ns     645.7uV    3.818mV    143.1uV
2.4ns     225.5uV    992.2uV    64.1uV
15ns      3.689uV    8.501uV    2.098uV
[Falling Waveform]
R_fixture = 50.0000
V_fixture = 2.5000
V_fixture_min = 2.3000
V_fixture_max = 2.7000
| time   V(typ)   V(min)   V(max)
0s        2.5V       2.3V       2.7V
600ps     2.503V     2.3V       2.689V
900ps     2.397V     2.307V     1.938V
1.2ns     1.863V     2.269V     981.3mV
1.5ns     1.052V     1.838V     669.7mV
1.8ns     694.6mV    1.177V     611.6mV
2.1ns     656.7mV    904.4mV    606mV
2.4ns     646.9mV    804.4mV    604.4mV
3ns       641.9mV    764.4mV    603.6mV
15ns      641.4mV    754.3mV    603.7mV
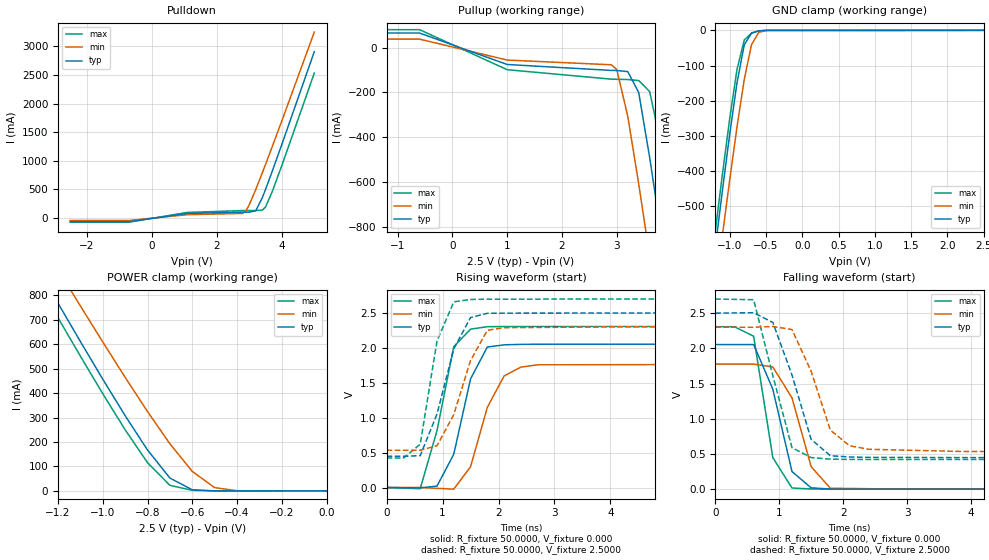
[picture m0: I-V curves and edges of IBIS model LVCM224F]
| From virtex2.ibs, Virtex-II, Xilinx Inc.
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|   Model LVCM224F
[Model]   LVCM224F
Model_type   I/O
Polarity   Non-Inverting
Enable   Active-Low
Vinh = 1.7V
Vinl = 0.7V
Vmeas =   1.2500V
Cref =  0pF
Rref =   1.0000M
Vref =  0.000V
C_comp   7.0000pF   6.0000pF   8.0000pF
[Temperature Range]   25.0000   100.0000   0.000
[Voltage Range]   2.5000V   2.3000V   2.7000V
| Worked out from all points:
|   slope of the pulldown table from 0 to 0.375 V, typ, clamps not added: 10.7 ohm
|   slope of the pullup table from 0 to 0.375 V, typ, clamps not added: 10.6 ohm
|   GND clamp passes 1 mA (typ) near -0.57 V on its own axis
|   POWER clamp passes 1 mA (typ) near -0.52 V on its own axis
|   rising waveform, R_fixture 50.0000, V_fixture 0.000: 20-80 % time 401ps typ, 461ps min, 384ps max; typ from 0 V to 2.05 V
|   rising waveform, R_fixture 50.0000, V_fixture 2.5000: 20-80 % time 467ps typ, 494ps min, 326ps max; typ from 0.448 V to 2.5 V
|   falling waveform, R_fixture 50.0000, V_fixture 0.000: 20-80 % time 364ps typ, 374ps min, 241ps max; typ from 2.05 V to 0 V
|   falling waveform, R_fixture 50.0000, V_fixture 2.5000: 20-80 % time 439ps typ, 421ps min, 391ps max; typ from 2.5 V to 0.448 V
[Pulldown]
| voltage   I(typ)   I(min)   I(max)
-2.5V     -63.55mA   -42.86mA   -72.65mA
-700mV    -63.55mA   -42.86mA   -72.65mA
1.1V      80.91mA    58.77mA    98.16mA
2.8V      102.3mA    80.58mA    130.8mA
2.9V      102.4mA    128mA      131mA
3V        102.7mA    231.2mA    131.2mA
3.2V      125.9mA    497mA      131.6mA
3.4V      351.8mA    787.1mA    138.6mA
3.5V      497.9mA    935.8mA    190.1mA
3.7V      806.1mA    1.237A     451.4mA
4V        1.283A     1.695A     914.8mA
5V        2.91A      3.252A     2.535A
[Pullup]
| voltage   I(typ)   I(min)   I(max)
-2.5V     64.88mA    37.65mA    79.8mA
-600mV    64.88mA    37.65mA    79.8mA
1V        -75.49mA   -55.69mA   -98.73mA
2.9V      -101.9mA   -76.76mA   -140.8mA
3V        -102.3mA   -97.71mA   -141.4mA
3.2V      -107.1mA   -305.7mA   -142.5mA
3.4V      -200.1mA   -607.2mA   -147.1mA
3.6V      -489.3mA   -930mA     -196.2mA
3.7V      -652.2mA   -1.094A    -310mA
4V        -1.16A     -1.597A    -786.4mA
4.2V      -1.506A    -1.935A    -1.127A
5V        -2.913A    -3.304A    -2.527A
[GND_clamp]
| voltage   I(typ)   I(min)   I(max)
-2.5V     -2.881A    -2.936A    -2.838A
-1.2V     -617mA     -740.6mA   -570.6mA
-1.1V     -452.1mA   -579.7mA   -406.1mA
-1V       -293.4mA   -423mA     -249mA
-900mV    -148mA     -273.4mA   -110.1mA
-800mV    -41mA      -138.5mA   -27.22mA
-700mV    -7.569mA   -40.19mA   -8.128mA
-600mV    -1.403mA   -5.589mA   -1.597mA
-500mV    -127.6uA   -662.5uA   -122uA
2.5V      397.5nA    2.548uA    351.3nA
[POWER_clamp]
| voltage   I(typ)   I(min)   I(max)
-2.5V     2.874A     2.908A     2.816A
-1.3V     925.8mA    1.055A     866.1mA
-1.2V     767.5mA    905.5mA    707.7mA
-1.1V     610.9mA    756.3mA    551.2mA
-1V       456.9mA    609.1mA    397.6mA
-900mV    307.7mA    464.5mA    250.2mA
-800mV    167.5mA    324.6mA    115.6mA
-700mV    52.75mA    192.9mA    22.81mA
-600mV    4.571mA    79.88mA    2.444mA
-500mV    271.3uA    13.45mA    251.8uA
-400mV    16.93uA    820.9uA    15.04uA
0V        397.5nA    368nA      428.7nA
[Ramp]
| variable   typ   min   max
dV/dt_r   1.2324/0.3212n   1.0656/0.4743n   1.3842/0.2521n
dV/dt_f   1.2313/0.3138n   1.0598/0.4429n   1.3672/0.2561n
R_load = 50.0000
[Rising Waveform]
R_fixture = 50.0000
V_fixture = 0.000
| time   V(typ)   V(min)   V(max)
0s        3.833uV    4.715uV    3.641uV
600ps     -5.66mV    191.6uV    -16.81mV
900ps     20.57mV    -12.12mV   814mV
1.2ns     476.6mV    -23.78mV   2.018V
1.5ns     1.556V     297.8mV    2.269V
1.8ns     2.013V     1.149V     2.304V
2.1ns     2.044V     1.598V     2.306V
2.4ns     2.051V     1.725V     2.306V
2.7ns     2.053V     1.758V     2.307V
15ns      2.054V     1.776V     2.307V
[Rising Waveform]
R_fixture = 50.0000
V_fixture = 2.5000
V_fixture_min = 2.3000
V_fixture_max = 2.7000
| time   V(typ)   V(min)   V(max)
0s        447.9mV    533.7mV    421.4mV
300ps     447.9mV    533.7mV    421.5mV
600ps     455.5mV    533.6mV    619.9mV
900ps     1.052V     598.4mV    2.098V
1.2ns     1.986V     1.045V     2.66V
1.5ns     2.435V     1.821V     2.694V
1.8ns     2.496V     2.252V     2.699V
2.1ns     2.498V     2.29V      2.699V
3.9ns     2.5V       2.3V       2.7V
15ns      2.5V       2.3V       2.7V
[Falling Waveform]
R_fixture = 50.0000
V_fixture = 0.000
| time   V(typ)   V(min)   V(max)
0s        2.054V     1.776V     2.307V
300ps     2.054V     1.776V     2.307V
600ps     2.054V     1.776V     2.172V
900ps     1.421V     1.736V     448.4mV
1.2ns     250.3mV    1.297V     16.27mV
1.5ns     19.08mV    320mV      2.736mV
1.8ns     1.851mV    12.85mV    392.6uV
3ns       45.03uV    230.2uV    -10.04uV
15ns      5.901uV    -15.56uV   -5.546uV
[Falling Waveform]
R_fixture = 50.0000
V_fixture = 2.5000
V_fixture_min = 2.3000
V_fixture_max = 2.7000
| time   V(typ)   V(min)   V(max)
0s        2.5V       2.3V       2.7V
600ps     2.506V     2.3V       2.691V
900ps     2.368V     2.31V      1.614V
1.2ns     1.622V     2.268V     589.1mV
1.5ns     707.3mV    1.673V     449mV
1.8ns     474.6mV    838.6mV    426.1mV
2.1ns     457.2mV    616.5mV    422.5mV
2.4ns     451.9mV    566.4mV    421.6mV
3.9ns     447.9mV    534.5mV    421.4mV
15ns      447.9mV    533.7mV    421.4mV
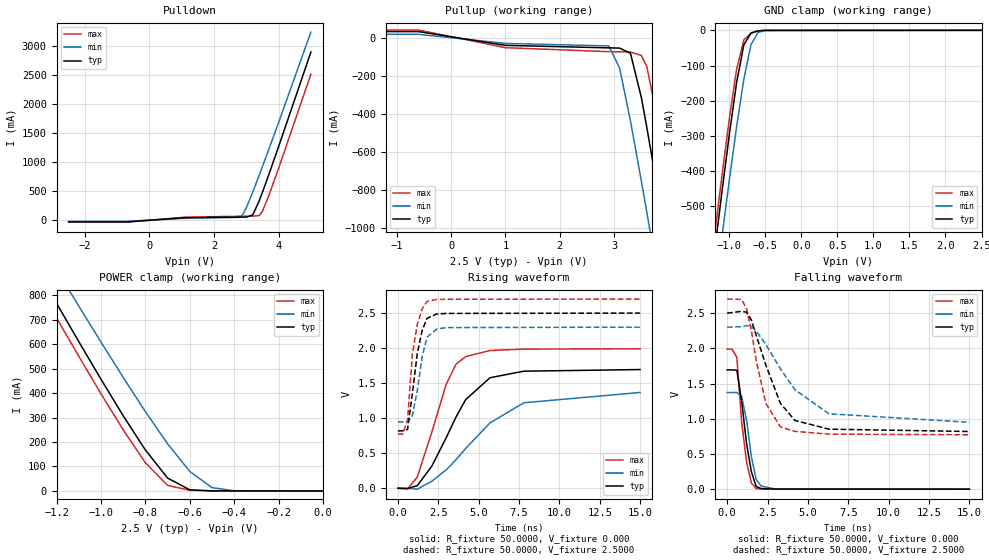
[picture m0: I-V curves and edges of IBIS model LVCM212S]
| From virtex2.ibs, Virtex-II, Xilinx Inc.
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|   Model LVCM212S
[Model]   LVCM212S
Model_type   I/O
Polarity   Non-Inverting
Enable   Active-Low
Vinh = 1.7V
Vinl = 0.7V
Vmeas =   1.2500V
Cref =  0pF
Rref =   1.0000M
Vref =  0.000V
C_comp   7.0000pF   6.0000pF   8.0000pF
[Temperature Range]   25.0000   100.0000   0.000
[Voltage Range]   2.5000V   2.3000V   2.7000V
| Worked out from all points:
|   slope of the pulldown table from 0 to 0.375 V, typ, clamps not added: 21 ohm
|   slope of the pullup table from 0 to 0.375 V, typ, clamps not added: 20.5 ohm
|   GND clamp passes 1 mA (typ) near -0.57 V on its own axis
|   POWER clamp passes 1 mA (typ) near -0.52 V on its own axis
|   rising waveform, R_fixture 50.0000, V_fixture 0.000: 20-80 % time 2.32ns typ, 3.58ns min, 1.58ns max; typ from 0 V to 1.69 V
|   rising waveform, R_fixture 50.0000, V_fixture 2.5000: 20-80 % time 640ps typ, 615ps min, 528ps max; typ from 0.819 V to 2.5 V
|   falling waveform, R_fixture 50.0000, V_fixture 0.000: 20-80 % time 607ps typ, 576ps min, 505ps max; typ from 1.69 V to 0 V
|   falling waveform, R_fixture 50.0000, V_fixture 2.5000: 20-80 % time 1.64ns typ, 2.59ns min, 1.06ns max; typ from 2.5 V to 0.819 V
[Pulldown]
| voltage   I(typ)   I(min)   I(max)
-2.5V     -32.1mA    -21.59mA   -36.83mA
-700mV    -32.1mA    -21.59mA   -36.83mA
1.1V      40.81mA    29.55mA    49.66mA
2.8V      51.15mA    46.44mA    65.44mA
2.9V      51.24mA    103.4mA    65.54mA
3V        51.47mA    211.8mA    65.63mA
3.2V      87.52mA    480.7mA    65.92mA
3.4V      329.5mA    771.7mA    78.28mA
3.5V      477.3mA    920.6mA    151mA
3.7V      786.8mA    1.222A     424.4mA
4V        1.264A     1.68A      890.4mA
5V        2.892A     3.237A     2.511A
[Pullup]
| voltage   I(typ)   I(min)   I(max)
-2.5V     33.53mA    19.14mA    41.73mA
-600mV    33.53mA    19.14mA    41.73mA
1V        -38.92mA   -28.63mA   -51.11mA
2.9V      -52.1mA    -41.79mA   -72.07mA
3.1V      -53.39mA   -158.4mA   -72.65mA
3.3V      -81.13mA   -437.8mA   -74mA
3.5V      -314.2mA   -754.1mA   -92.11mA
3.6V      -471mA     -917.4mA   -151mA
3.8V      -802.6mA   -1.249A    -432.8mA
4V        -1.144A    -1.585A    -763.1mA
4.2V      -1.491A    -1.923A    -1.105A
5V        -2.897A    -3.292A    -2.506A
[GND_clamp]
| voltage   I(typ)   I(min)   I(max)
-2.5V     -2.881A    -2.936A    -2.838A
-1.2V     -617mA     -740.6mA   -570.6mA
-1.1V     -452.1mA   -579.7mA   -406.1mA
-1V       -293.4mA   -423mA     -249mA
-900mV    -148mA     -273.4mA   -110.1mA
-800mV    -41mA      -138.5mA   -27.22mA
-700mV    -7.569mA   -40.19mA   -8.128mA
-600mV    -1.403mA   -5.589mA   -1.597mA
-500mV    -127.6uA   -662.5uA   -122uA
2.5V      397.5nA    2.548uA    351.3nA
[POWER_clamp]
| voltage   I(typ)   I(min)   I(max)
-2.5V     2.874A     2.908A     2.816A
-1.3V     925.8mA    1.055A     866.1mA
-1.2V     767.5mA    905.5mA    707.7mA
-1.1V     610.9mA    756.3mA    551.2mA
-1V       456.9mA    609.1mA    397.6mA
-900mV    307.7mA    464.5mA    250.2mA
-800mV    167.5mA    324.6mA    115.6mA
-700mV    52.75mA    192.9mA    22.81mA
-600mV    4.571mA    79.88mA    2.444mA
-500mV    271.3uA    13.45mA    251.8uA
-400mV    16.93uA    820.9uA    15.04uA
0V        397.5nA    368nA      428.7nA
[Ramp]
| variable   typ   min   max
dV/dt_r   1.0164/2.3118n   0.8202/3.5760n   1.1940/1.6126n
dV/dt_f   1.0087/1.6280n   0.8105/2.5838n   1.1564/1.1102n
R_load = 50.0000
[Rising Waveform]
R_fixture = 50.0000
V_fixture = 0.000
| time   V(typ)   V(min)   V(max)
0s        6.981uV    8.2uV      6.729uV
600ps     -3.649mV   -137.9uV   -10.31mV
1.2ns     37.33mV    -12.94mV   159.6mV
2.1ns     315.3mV    100.7mV    800mV
3ns       725.2mV    264.2mV    1.49V
3.6ns     1.017V     407.9mV    1.771V
4.2ns     1.266V     568.3mV    1.879V
5.7ns     1.577V     932.1mV    1.966V
7.8ns     1.671V     1.22V      1.986V
15ns      1.694V     1.367V     1.99V
[Rising Waveform]
R_fixture = 50.0000
V_fixture = 2.5000
V_fixture_min = 2.3000
V_fixture_max = 2.7000
| time   V(typ)   V(min)   V(max)
0s        818.6mV    946.5mV    772.7mV
300ps     818.6mV    946.5mV    772.7mV
600ps     840.7mV    947.5mV    978.4mV
900ps     1.359V     1.041V     1.919V
1.2ns     1.922V     1.393V     2.335V
1.5ns     2.249V     1.875V     2.558V
1.8ns     2.425V     2.155V     2.666V
2.4ns     2.487V     2.272V     2.695V
3ns       2.495V     2.293V     2.697V
15ns      2.5V       2.299V     2.7V
[Falling Waveform]
R_fixture = 50.0000
V_fixture = 0.000
| time   V(typ)   V(min)   V(max)
0s        1.694V     1.372V     1.99V
300ps     1.694V     1.372V     1.99V
600ps     1.69V      1.373V     1.873V
900ps     1.244V     1.315V     948.5mV
1.2ns     651.6mV    983.7mV    391.5mV
1.5ns     246.5mV    462mV      88.56mV
1.8ns     38.27mV    136.8mV    7.769mV
2.1ns     9.096mV    45.79mV    2.659mV
3ns       1.209mV    1.233mV    1.14mV
15ns      -23.71uV   15.13uV    33.54uV
[Falling Waveform]
R_fixture = 50.0000
V_fixture = 2.5000
V_fixture_min = 2.3000
V_fixture_max = 2.7000
| time   V(typ)   V(min)   V(max)
0s        2.5V       2.3V       2.7V
900ps     2.526V     2.308V     2.695V
1.2ns     2.513V     2.322V     2.561V
1.5ns     2.404V     2.312V     2.256V
1.8ns     2.184V     2.247V     1.825V
2.4ns     1.759V     2.054V     1.217V
3.3ns     1.218V     1.708V     885.2mV
4.2ns     975.3mV    1.411V     820.3mV
6.3ns     852.2mV    1.071V     781.3mV
15ns      818.8mV    949.2mV    772.7mV
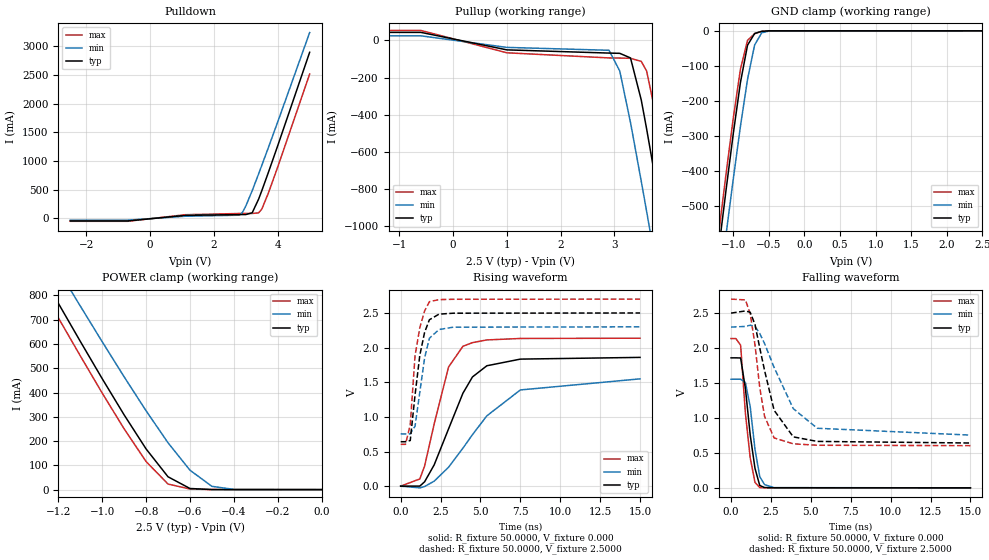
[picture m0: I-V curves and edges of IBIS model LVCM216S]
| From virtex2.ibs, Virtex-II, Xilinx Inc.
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|   Model LVCM216S
[Model]   LVCM216S
Model_type   I/O
Polarity   Non-Inverting
Enable   Active-Low
Vinh = 1.7V
Vinl = 0.7V
Vmeas =   1.2500V
Cref =  0pF
Rref =   1.0000M
Vref =  0.000V
C_comp   7.0000pF   6.0000pF   8.0000pF
[Temperature Range]   25.0000   100.0000   0.000
[Voltage Range]   2.5000V   2.3000V   2.7000V
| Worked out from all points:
|   slope of the pulldown table from 0 to 0.375 V, typ, clamps not added: 15.9 ohm
|   slope of the pullup table from 0 to 0.375 V, typ, clamps not added: 15.8 ohm
|   GND clamp passes 1 mA (typ) near -0.57 V on its own axis
|   POWER clamp passes 1 mA (typ) near -0.52 V on its own axis
|   rising waveform, R_fixture 50.0000, V_fixture 0.000: 20-80 % time 2.02ns typ, 3.26ns min, 1.36ns max; typ from 0 V to 1.86 V
|   rising waveform, R_fixture 50.0000, V_fixture 2.5000: 20-80 % time 654ps typ, 626ps min, 552ps max; typ from 0.641 V to 2.5 V
|   falling waveform, R_fixture 50.0000, V_fixture 0.000: 20-80 % time 587ps typ, 554ps min, 502ps max; typ from 1.86 V to 0 V
|   falling waveform, R_fixture 50.0000, V_fixture 2.5000: 20-80 % time 1.17ns typ, 1.89ns min, 756ps max; typ from 2.5 V to 0.642 V
[Pulldown]
| voltage   I(typ)   I(min)   I(max)
-2.5V     -42.66mA   -28.72mA   -48.89mA
-700mV    -42.66mA   -28.72mA   -48.89mA
1.1V      54.26mA    39.33mA    65.96mA
2.8V      68.19mA    57.71mA    87.24mA
2.9V      68.31mA    111.5mA    87.38mA
3V        68.55mA    218.2mA    87.5mA
3.2V      99.9mA     486.1mA    87.82mA
3.4V      336.9mA    776.8mA    97.97mA
3.5V      484.1mA    925.7mA    163.6mA
3.7V      793.2mA    1.227A     433.3mA
4V        1.27A      1.685A     898.5mA
5V        2.898A     3.242A     2.519A
[Pullup]
| voltage   I(typ)   I(min)   I(max)
-2.5V     43.6mA     25.02mA    54.04mA
-600mV    43.6mA     25.02mA    54.04mA
1V        -50.63mA   -37.27mA   -66.4mA
2.9V      -67.94mA   -52.88mA   -93.97mA
3.1V      -69.23mA   -164.7mA   -94.73mA
3.3V      -94.12mA   -442.3mA   -96.08mA
3.5V      -320.6mA   -758.3mA   -112.6mA
3.6V      -476.8mA   -921.4mA   -164.7mA
3.8V      -807.9mA   -1.252A    -441.1mA
4V        -1.149A    -1.588A    -770.5mA
4.2V      -1.496A    -1.927A    -1.112A
5V        -2.902A    -3.296A    -2.513A
[GND_clamp]
| voltage   I(typ)   I(min)   I(max)
-2.5V     -2.881A    -2.936A    -2.838A
-1.2V     -617mA     -740.6mA   -570.6mA
-1.1V     -452.1mA   -579.7mA   -406.1mA
-1V       -293.4mA   -423mA     -249mA
-900mV    -148mA     -273.4mA   -110.1mA
-800mV    -41mA      -138.5mA   -27.22mA
-700mV    -7.569mA   -40.19mA   -8.128mA
-600mV    -1.403mA   -5.589mA   -1.597mA
-500mV    -127.6uA   -662.5uA   -122uA
2.5V      397.5nA    2.548uA    351.3nA
[POWER_clamp]
| voltage   I(typ)   I(min)   I(max)
-2.5V     2.874A     2.908A     2.816A
-1.3V     925.8mA    1.055A     866.1mA
-1.2V     767.5mA    905.5mA    707.7mA
-1.1V     610.9mA    756.3mA    551.2mA
-1V       456.9mA    609.1mA    397.6mA
-900mV    307.7mA    464.5mA    250.2mA
-800mV    167.5mA    324.6mA    115.6mA
-700mV    52.75mA    192.9mA    22.81mA
-600mV    4.571mA    79.88mA    2.444mA
-500mV    271.3uA    13.45mA    251.8uA
-400mV    16.93uA    820.9uA    15.04uA
0V        397.5nA    368nA      428.7nA
[Ramp]
| variable   typ   min   max
dV/dt_r   1.1154/2.0087n   0.9294/3.2576n   1.2816/1.3797n
dV/dt_f   1.1151/1.1674n   0.9272/1.8839n   1.2578/0.8180n
R_load = 50.0000
[Rising Waveform]
R_fixture = 50.0000
V_fixture = 0.000
| time   V(typ)   V(min)   V(max)
0s        5.495uV    6.59uV     5.26uV
1.2ns     997uV      -24.63mV   104.2mV
1.5ns     63.01mV    -5.122mV   290.9mV
2.1ns     307.2mV    71.91mV    897.8mV
3ns       826.3mV    273.3mV    1.72V
3.9ns     1.341V     548.2mV    2.019V
4.5ns     1.577V     743.7mV    2.072V
5.4ns     1.738V     1.015V     2.111V
7.5ns     1.834V     1.389V     2.132V
15ns      1.859V     1.549V     2.136V
[Rising Waveform]
R_fixture = 50.0000
V_fixture = 2.5000
V_fixture_min = 2.3000
V_fixture_max = 2.7000
| time   V(typ)   V(min)   V(max)
0s        641.4mV    754.3mV    603.7mV
300ps     641.4mV    754.3mV    603.7mV
600ps     658.4mV    754.2mV    884.6mV
900ps     1.314V     865.3mV    1.881V
1.2ns     1.89V      1.357V     2.289V
1.5ns     2.22V      1.852V     2.53V
1.8ns     2.402V     2.135V     2.663V
2.4ns     2.483V     2.261V     2.693V
3.3ns     2.497V     2.295V     2.698V
15ns      2.5V       2.3V       2.7V
[Falling Waveform]
R_fixture = 50.0000
V_fixture = 0.000
| time   V(typ)   V(min)   V(max)
0s        1.86V      1.554V     2.136V
300ps     1.86V      1.554V     2.136V
600ps     1.858V     1.554V     2.041V
900ps     1.422V     1.507V     1.067V
1.2ns     756.1mV    1.163V     431.8mV
1.5ns     278.8mV    551.3mV    78.52mV
1.8ns     33.55mV    159.8mV    4.472mV
2.1ns     4.563mV    45.87mV    1.495mV
2.7ns     1.304mV    3.561mV    1.395mV
15ns      38.41uV    46.73uV    -13.1uV
[Falling Waveform]
R_fixture = 50.0000
V_fixture = 2.5000
V_fixture_min = 2.3000
V_fixture_max = 2.7000
| time   V(typ)   V(min)   V(max)
0s        2.5V       2.3V       2.7V
900ps     2.531V     2.309V     2.689V
1.2ns     2.512V     2.327V     2.493V
1.5ns     2.338V     2.31V      2.048V
1.8ns     2.001V     2.207V     1.433V
2.1ns     1.68V      2.065V     1.022V
2.7ns     1.109V     1.722V     714.3mV
3.9ns     729.2mV    1.133V     629.9mV
5.4ns     664.6mV    852.8mV    609.6mV
15ns      641.5mV    754.7mV    603.7mV
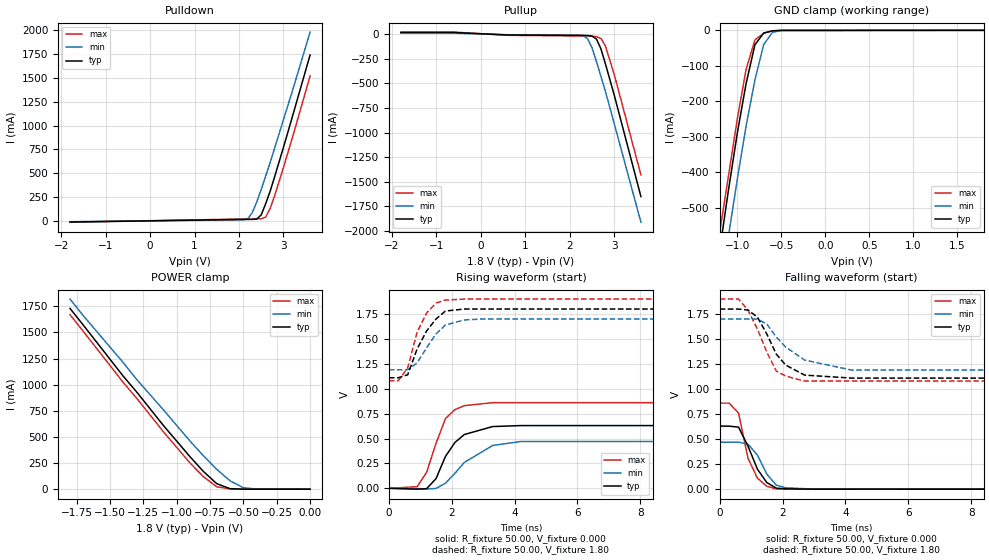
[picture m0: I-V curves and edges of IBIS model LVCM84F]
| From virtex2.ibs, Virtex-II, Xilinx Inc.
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|   Model LVCM84F
[Model]   LVCM84F
Model_type   I/O
Polarity   Non-Inverting
Enable   Active-Low
Vinh = 1.19V
Vinl = 0.4V
Vmeas =   0.90V
Cref =  0pF
Rref =   1.00M
Vref =  0.000V
C_comp   10.00pF   10.00pF   10.00pF
[Temperature Range]   25.00   100.00   0.000
[Voltage Range]   1.80V   1.70V   1.90V
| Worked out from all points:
|   slope of the pulldown table from 0 to 0.27 V, typ, clamps not added: 60.3 ohm
|   slope of the pullup table from 0 to 0.27 V, typ, clamps not added: 50.5 ohm
|   GND clamp passes 1 mA (typ) near -0.57 V on its own axis
|   POWER clamp passes 1 mA (typ) near -0.52 V on its own axis
|   rising waveform, R_fixture 50.00, V_fixture 0.000: 20-80 % time 726ps typ, 987ps min, 573ps max; typ from 0 V to 0.63 V
|   rising waveform, R_fixture 50.00, V_fixture 1.80: 20-80 % time 680ps typ, 696ps min, 534ps max; typ from 1.11 V to 1.8 V
|   falling waveform, R_fixture 50.00, V_fixture 0.000: 20-80 % time 582ps typ, 551ps min, 459ps max; typ from 0.63 V to 0 V
|   falling waveform, R_fixture 50.00, V_fixture 1.80: 20-80 % time 776ps typ, 1.07ns min, 714ps max; typ from 1.8 V to 1.11 V
[Pulldown]
| voltage   I(typ)   I(min)   I(max)
-1.8V     -10.76mA   -7.23mA    -12.39mA
2.1V      16.75mA    12.75mA    21.45mA
2.2V      16.82mA    24.06mA    21.53mA
2.3V      17.09mA    87.43mA    21.61mA
2.4V      20.67mA    200mA      21.85mA
2.5V      63.83mA    330mA      23.76mA
2.6V      180mA      470mA      40.43mA
2.7V      310mA      610mA      130mA
2.8V      460mA      760mA      260mA
3V        770mA      1.06A      560mA
3.2V      1.09A      1.36A      870mA
3.6V      1.74A      1.98A      1.52A
[Pullup]
| voltage   I(typ)   I(min)   I(max)
-1.8V     15.21mA    8.5mA      19.56mA
-600mV    15.21mA    8.5mA      19.56mA
600mV     -9.7mA     -7.29mA    -13.14mA
2.2V      -13.94mA   -11mA      -19.85mA
2.3V      -14.12mA   -15.57mA   -19.97mA
2.4V      -15.32mA   -47.94mA   -20.16mA
2.5V      -21.08mA   -140mA     -21.5mA
2.6V      -51.36mA   -280mA     -27.58mA
2.7V      -150mA     -430mA     -44.6mA
2.8V      -300mA     -580mA     -120mA
3V        -620mA     -910mA     -410mA
3.6V      -1.65A     -1.91A     -1.43A
[GND_clamp]
| voltage   I(typ)   I(min)   I(max)
-1.8V     -1.65A     -1.74A     -1.6A
-1.2V     -620mA     -740mA     -570mA
-1.1V     -450mA     -580mA     -410mA
-1V       -290mA     -420mA     -250mA
-900mV    -150mA     -270mA     -110mA
-800mV    -40.97mA   -140mA     -27.17mA
-700mV    -7.54mA    -40.17mA   -8.08mA
-600mV    -1.39mA    -5.57mA    -1.57mA
-500mV    -120uA     -660uA     -120uA
1.8V      34.27pA    98.88nA    22.46pA
[POWER_clamp]
| voltage   I(typ)   I(min)   I(max)
-1.8V     1.73A      1.82A      1.67A
-1.7V     1.57A      1.66A      1.51A
-1.4V     1.08A      1.21A      1.02A
-1.3V     930mA      1.05A      870mA
-1.1V     610mA      760mA      550mA
-900mV    310mA      460mA      250mA
-800mV    170mA      320mA      120mA
-700mV    52.75mA    190mA      22.81mA
-600mV    4.57mA     79.88mA    2.44mA
-500mV    270uA      13.45mA    250uA
-400mV    16.38uA    820uA      14.46uA
0V        34.27pA    1.07nA     29.84pA
[Ramp]
| variable   typ   min   max
dV/dt_r   0.38/0.74n   0.28/0.96n   0.51/0.62n
dV/dt_f   0.41/0.84n   0.31/1.11n   0.49/0.66n
R_load = 50.00
[Rising Waveform]
R_fixture = 50.00
V_fixture = 0.000
| time   V(typ)   V(min)   V(max)
0s        0V         0V         0V
900ps     -8.44mV    -3.78mV    16.31mV
1.2ns     -3.78mV    -6.95mV    160mV
1.5ns     96.81mV    -1.27mV    450mV
1.8ns     320mV      51.66mV    700mV
2.1ns     460mV      150mV      790mV
2.4ns     540mV      260mV      830mV
3.3ns     620mV      430mV      860mV
4.2ns     630mV      470mV      860mV
15ns      630mV      470mV      860mV
[Rising Waveform]
R_fixture = 50.00
V_fixture = 1.80
V_fixture_min = 1.70
V_fixture_max = 1.90
| time   V(typ)   V(min)   V(max)
0s        1.11V      1.19V      1.08V
300ps     1.11V      1.19V      1.08V
600ps     1.14V      1.19V      1.21V
900ps     1.4V       1.26V      1.57V
1.2ns     1.58V      1.41V      1.76V
1.5ns     1.7V       1.55V      1.86V
1.8ns     1.78V      1.64V      1.89V
2.4ns     1.8V       1.69V      1.9V
3ns       1.8V       1.7V       1.9V
15ns      1.8V       1.7V       1.9V
[Falling Waveform]
R_fixture = 50.00
V_fixture = 0.000
| time   V(typ)   V(min)   V(max)
0s        630mV      470mV      860mV
300ps     630mV      470mV      860mV
600ps     620mV      470mV      760mV
900ps     430mV      450mV      310mV
1.2ns     200mV      340mV      110mV
1.5ns     65.65mV    150mV      28.82mV
1.8ns     9.88mV     40.34mV    2.28mV
2.1ns     3.35mV     13.6mV     980uV
3ns       180uV      380uV      67.2uV
15ns      8.42uV     2.42uV     -29.8uV
[Falling Waveform]
R_fixture = 50.00
V_fixture = 1.80
V_fixture_min = 1.70
V_fixture_max = 1.90
| time   V(typ)   V(min)   V(max)
0s        1.8V       1.7V       1.9V
600ps     1.8V       1.7V       1.9V
900ps     1.79V      1.7V       1.79V
1.2ns     1.72V      1.7V       1.6V
1.5ns     1.55V      1.65V      1.37V
1.8ns     1.35V      1.52V      1.18V
2.1ns     1.24V      1.42V      1.13V
2.7ns     1.14V      1.29V      1.08V
4.2ns     1.11V      1.19V      1.08V
15ns      1.11V      1.19V      1.08V
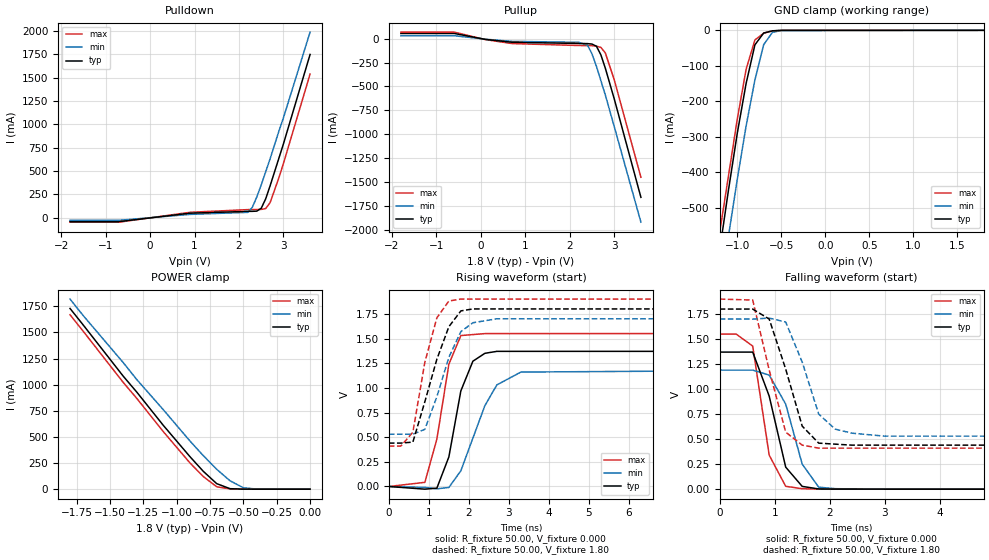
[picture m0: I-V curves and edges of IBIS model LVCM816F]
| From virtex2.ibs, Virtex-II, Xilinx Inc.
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|   Model LVCM816F
[Model]   LVCM816F
Model_type   I/O
Polarity   Non-Inverting
Enable   Active-Low
Vinh = 1.19V
Vinl = 0.4V
Vmeas =   0.90V
Cref =  0pF
Rref =   1.00M
Vref =  0.000V
C_comp   10.00pF   10.00pF   10.00pF
[Temperature Range]   25.00   100.00   0.000
[Voltage Range]   1.80V   1.70V   1.90V
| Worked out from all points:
|   slope of the pulldown table from 0 to 0.27 V, typ, clamps not added: 15.4 ohm
|   slope of the pullup table from 0 to 0.27 V, typ, clamps not added: 14.2 ohm
|   GND clamp passes 1 mA (typ) near -0.57 V on its own axis
|   POWER clamp passes 1 mA (typ) near -0.52 V on its own axis
|   rising waveform, R_fixture 50.00, V_fixture 0.000: 20-80 % time 451ps typ, 718ps min, 416ps max; typ from 0 V to 1.37 V
|   rising waveform, R_fixture 50.00, V_fixture 1.80: 20-80 % time 625ps typ, 613ps min, 461ps max; typ from 0.44 V to 1.8 V
|   falling waveform, R_fixture 50.00, V_fixture 0.000: 20-80 % time 390ps typ, 421ps min, 277ps max; typ from 1.37 V to 0 V
|   falling waveform, R_fixture 50.00, V_fixture 1.80: 20-80 % time 454ps typ, 439ps min, 410ps max; typ from 1.8 V to 0.44 V
[Pulldown]
| voltage   I(typ)   I(min)   I(max)
-1.8V     -42.66mA   -28.72mA   -48.89mA
-700mV    -42.66mA   -28.72mA   -48.89mA
900mV     47.73mA    34.88mA    57.36mA
2.2V      67.2mA     56.66mA    86.05mA
2.3V      67.54mA    110mA      86.33mA
2.4V      69.73mA    220mA      86.66mA
2.5V      99.28mA    350mA      87.97mA
2.6V      200mA      490mA      97.08mA
2.7V      340mA      630mA      160mA
2.9V      640mA      930mA      430mA
3V        790mA      1.07A      580mA
3.6V      1.75A      1.99A      1.54A
[Pullup]
| voltage   I(typ)   I(min)   I(max)
-1.8V     54.35mA    30.98mA    68.67mA
-600mV    54.35mA    30.98mA    68.67mA
100mV     -7.7mA     -5.89mA    -9.92mA
700mV     -37.83mA   -28.42mA   -51.54mA
2.2V      -50.35mA   -38.05mA   -71.67mA
2.4V      -51.79mA   -68.88mA   -72.53mA
2.5V      -56.69mA   -160mA     -73.67mA
2.6V      -79.92mA   -290mA     -78.72mA
2.7V      -170mA     -440mA     -91.95mA
2.8V      -310mA     -590mA     -150mA
3V        -630mA     -920mA     -430mA
3.6V      -1.66A     -1.92A     -1.45A
[GND_clamp]
| voltage   I(typ)   I(min)   I(max)
-1.8V     -1.65A     -1.74A     -1.6A
-1.2V     -620mA     -740mA     -570mA
-1.1V     -450mA     -580mA     -410mA
-1V       -290mA     -420mA     -250mA
-900mV    -150mA     -270mA     -110mA
-800mV    -40.97mA   -140mA     -27.17mA
-700mV    -7.54mA    -40.17mA   -8.08mA
-600mV    -1.39mA    -5.57mA    -1.57mA
-500mV    -120uA     -660uA     -120uA
1.8V      34.27pA    98.88nA    22.46pA
[POWER_clamp]
| voltage   I(typ)   I(min)   I(max)
-1.8V     1.73A      1.82A      1.67A
-1.7V     1.57A      1.66A      1.51A
-1.4V     1.08A      1.21A      1.02A
-1.3V     930mA      1.05A      870mA
-1.1V     610mA      760mA      550mA
-900mV    310mA      460mA      250mA
-800mV    170mA      320mA      120mA
-700mV    52.75mA    190mA      22.81mA
-600mV    4.57mA     79.88mA    2.44mA
-500mV    270uA      13.45mA    250uA
-400mV    16.38uA    820uA      14.46uA
0V        34.27pA    1.07nA     29.83pA
[Ramp]
| variable   typ   min   max
dV/dt_r   0.82/0.47n   0.71/0.68n   0.93/0.34n
dV/dt_f   0.82/0.34n   0.70/0.47n   0.90/0.28n
R_load = 50.00
[Rising Waveform]
R_fixture = 50.00
V_fixture = 0.000
| time   V(typ)   V(min)   V(max)
0s        0V         0V         0V
900ps     -27.07mV   -9.2mV     42.04mV
1.2ns     -16.63mV   -23.82mV   480mV
1.5ns     300mV      -9.82mV    1.24V
1.8ns     970mV      160mV      1.53V
2.1ns     1.27V      490mV      1.54V
2.4ns     1.35V      820mV      1.55V
2.7ns     1.37V      1.03V      1.55V
3.3ns     1.37V      1.16V      1.55V
15ns      1.37V      1.19V      1.55V
[Rising Waveform]
R_fixture = 50.00
V_fixture = 1.80
V_fixture_min = 1.70
V_fixture_max = 1.90
| time   V(typ)   V(min)   V(max)
0s        440mV      530mV      410mV
300ps     440mV      530mV      410mV
600ps     450mV      530mV      550mV
900ps     860mV      580mV      1.26V
1.2ns     1.29V      910mV      1.71V
1.5ns     1.62V      1.31V      1.88V
1.8ns     1.78V      1.57V      1.9V
2.1ns     1.8V       1.66V      1.9V
2.7ns     1.8V       1.7V       1.9V
15ns      1.8V       1.7V       1.9V
[Falling Waveform]
R_fixture = 50.00
V_fixture = 0.000
| time   V(typ)   V(min)   V(max)
0s        1.37V      1.19V      1.55V
300ps     1.37V      1.19V      1.55V
600ps     1.37V      1.19V      1.43V
900ps     930mV      1.14V      340mV
1.2ns     220mV      850mV      28.65mV
1.5ns     27.78mV    250mV      4.56mV
1.8ns     2.25mV     20.08mV    570uV
2.1ns     750uV      4.71mV     230uV
3ns       30.09uV    65.71uV    10.71uV
15ns      10.65uV    5.37uV     5.77uV
[Falling Waveform]
R_fixture = 50.00
V_fixture = 1.80
V_fixture_min = 1.70
V_fixture_max = 1.90
| time   V(typ)   V(min)   V(max)
0s        1.8V       1.7V       1.9V
600ps     1.8V       1.7V       1.89V
900ps     1.7V       1.71V      1.19V
1.2ns     1.2V       1.67V      570mV
1.5ns     630mV      1.27V      440mV
1.8ns     460mV      750mV      410mV
2.1ns     450mV      600mV      410mV
2.4ns     440mV      560mV      410mV
3ns       440mV      530mV      410mV
15ns      440mV      530mV      410mV
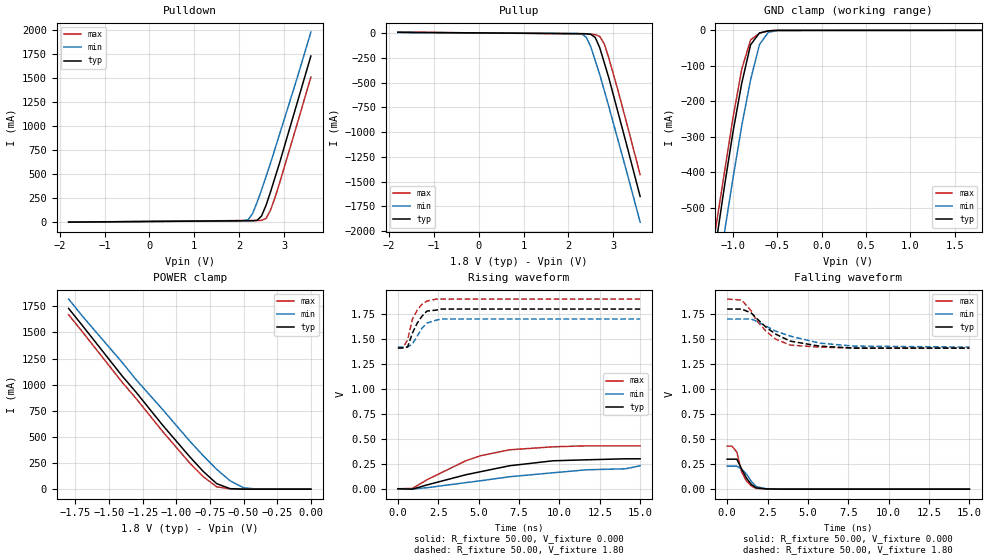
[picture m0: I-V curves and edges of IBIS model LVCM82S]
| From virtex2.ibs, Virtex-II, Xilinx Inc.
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|   Model LVCM82S
[Model]   LVCM82S
Model_type   I/O
Polarity   Non-Inverting
Enable   Active-Low
Vinh = 1.19V
Vinl = 0.4V
Vmeas =   0.90V
Cref =  0pF
Rref =   1.00M
Vref =  0.000V
C_comp   10.00pF   10.00pF   10.00pF
[Temperature Range]   25.00   100.00   0.000
[Voltage Range]   1.80V   1.70V   1.90V
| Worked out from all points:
|   slope of the pulldown table from 0 to 0.27 V, typ, clamps not added: 118 ohm
|   slope of the pullup table from 0 to 0.27 V, typ, clamps not added: 109 ohm
|   GND clamp passes 1 mA (typ) near -0.57 V on its own axis
|   POWER clamp passes 1 mA (typ) near -0.52 V on its own axis
|   rising waveform, R_fixture 50.00, V_fixture 0.000: 20-80 % time 4.86ns typ, 8.14ns min, 3.76ns max; typ from 0 V to 0.3 V
|   rising waveform, R_fixture 50.00, V_fixture 1.80: 20-80 % time 720ps typ, 707ps min, 634ps max; typ from 1.41 V to 1.8 V
|   falling waveform, R_fixture 50.00, V_fixture 0.000: 20-80 % time 656ps typ, 685ps min, 545ps max; typ from 0.3 V to 0 V
|   falling waveform, R_fixture 50.00, V_fixture 1.80: 20-80 % time 2.05ns typ, 3.03ns min, 1.53ns max; typ from 1.8 V to 1.41 V
[Pulldown]
| voltage   I(typ)   I(min)   I(max)
-1.8V     -5.48mA    -3.66mA    -6.34mA
2V        8.41mA     6.05mA     10.81mA
2.2V      8.5mA      18.77mA    10.9mA
2.3V      8.76mA     83.67mA    10.94mA
2.4V      12.68mA    200mA      11.18mA
2.5V      58.29mA    330mA      13.22mA
2.6V      170mA      470mA      31.64mA
2.7V      310mA      610mA      120mA
2.8V      460mA      760mA      250mA
2.9V      610mA      910mA      400mA
3.3V      1.25A      1.51A      1.03A
3.6V      1.73A      1.98A      1.51A
[Pullup]
| voltage   I(typ)   I(min)   I(max)
-1.8V     7.03mA     3.91mA     9.08mA
2.2V      -6.44mA    -5.43mA    -9.16mA
2.3V      -6.58mA    -10.18mA   -9.22mA
2.4V      -7.82mA    -43.74mA   -9.37mA
2.5V      -13.78mA   -140mA     -10.77mA
2.6V      -45.73mA   -280mA     -17.07mA
2.7V      -150mA     -420mA     -35.16mA
2.8V      -300mA     -580mA     -110mA
2.9V      -450mA     -740mA     -250mA
3.1V      -790mA     -1.07A     -570mA
3.3V      -1.13A     -1.4A      -910mA
3.6V      -1.65A     -1.91A     -1.43A
[GND_clamp]
| voltage   I(typ)   I(min)   I(max)
-1.8V     -1.65A     -1.74A     -1.6A
-1.2V     -620mA     -740mA     -570mA
-1.1V     -450mA     -580mA     -410mA
-1V       -290mA     -420mA     -250mA
-900mV    -150mA     -270mA     -110mA
-800mV    -40.97mA   -140mA     -27.17mA
-700mV    -7.54mA    -40.17mA   -8.08mA
-600mV    -1.39mA    -5.57mA    -1.57mA
-500mV    -120uA     -660uA     -120uA
1.8V      34.27pA    98.88nA    22.46pA
[POWER_clamp]
| voltage   I(typ)   I(min)   I(max)
-1.8V     1.73A      1.82A      1.67A
-1.7V     1.57A      1.66A      1.51A
-1.4V     1.08A      1.21A      1.02A
-1.3V     930mA      1.05A      870mA
-1.1V     610mA      760mA      550mA
-900mV    310mA      460mA      250mA
-800mV    170mA      320mA      120mA
-700mV    52.75mA    190mA      22.81mA
-600mV    4.57mA     79.88mA    2.44mA
-500mV    270uA      13.45mA    250uA
-400mV    16.38uA    820uA      14.46uA
0V        34.27pA    1.07nA     29.83pA
[Ramp]
| variable   typ   min   max
dV/dt_r   0.18/5.04n   0.12/6.79n   0.26/3.76n
dV/dt_f   0.24/2.16n   0.17/2.95n   0.29/1.62n
R_load = 50.00
[Rising Waveform]
R_fixture = 50.00
V_fixture = 0.000
| time   V(typ)   V(min)   V(max)
0s        0V         0V         0V
900ps     -4.18mV    -1.64mV    3.39mV
1.8ns     38.13mV    10.56mV    89.84mV
4.2ns     140mV      61.14mV    280mV
5.1ns     170mV      79.43mV    330mV
6.9ns     230mV      120mV      390mV
9.6ns     280mV      160mV      420mV
11.7ns    290mV      190mV      430mV
14.1ns    300mV      200mV      430mV
15ns      300mV      230mV      430mV
[Rising Waveform]
R_fixture = 50.00
V_fixture = 1.80
V_fixture_min = 1.70
V_fixture_max = 1.90
| time   V(typ)   V(min)   V(max)
0s        1.41V      1.42V      1.41V
300ps     1.41V      1.42V      1.41V
600ps     1.42V      1.42V      1.49V
900ps     1.56V      1.45V      1.7V
1.2ns     1.66V      1.53V      1.79V
1.5ns     1.73V      1.61V      1.85V
1.8ns     1.78V      1.66V      1.88V
2.4ns     1.79V      1.69V      1.9V
2.7ns     1.8V       1.7V       1.9V
15ns      1.8V       1.7V       1.9V
[Falling Waveform]
R_fixture = 50.00
V_fixture = 0.000
| time   V(typ)   V(min)   V(max)
0s        300mV      230mV      430mV
300ps     300mV      230mV      430mV
600ps     300mV      230mV      370mV
900ps     200mV      200mV      170mV
1.2ns     110mV      150mV      81.36mV
1.5ns     46.44mV    76.17mV    30.66mV
1.8ns     13.15mV    26.27mV    7.65mV
2.4ns     2.47mV     5.16mV     1.74mV
3.3ns     270uV      530uV      180uV
15ns      -4.11uV    75.43uV    57.93uV
[Falling Waveform]
R_fixture = 50.00
V_fixture = 1.80
V_fixture_min = 1.70
V_fixture_max = 1.90
| time   V(typ)   V(min)   V(max)
0s        1.8V       1.7V       1.9V
900ps     1.8V       1.7V       1.89V
1.5ns     1.76V      1.7V       1.78V
1.8ns     1.71V      1.68V      1.69V
2.4ns     1.62V      1.63V      1.58V
3ns       1.55V      1.58V      1.5V
3.9ns     1.48V      1.53V      1.44V
5.7ns     1.43V      1.46V      1.42V
7.8ns     1.41V      1.43V      1.41V
15ns      1.41V      1.42V      1.41V
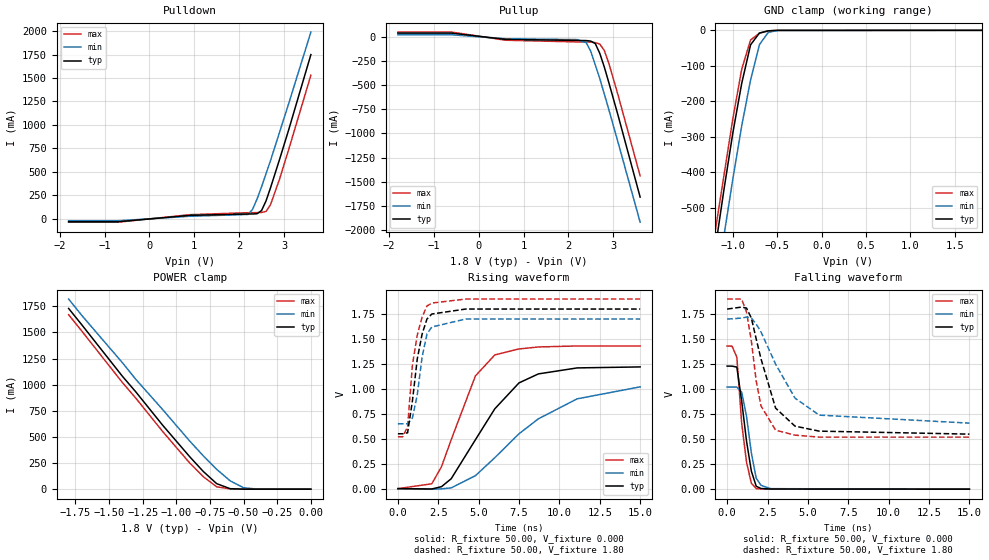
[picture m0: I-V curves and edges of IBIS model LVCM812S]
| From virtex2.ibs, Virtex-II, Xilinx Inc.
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|   Model LVCM812S
[Model]   LVCM812S
Model_type   I/O
Polarity   Non-Inverting
Enable   Active-Low
Vinh = 1.19V
Vinl = 0.4V
Vmeas =   0.90V
Cref =  0pF
Rref =   1.00M
Vref =  0.000V
C_comp   10.00pF   10.00pF   10.00pF
[Temperature Range]   25.00   100.00   0.000
[Voltage Range]   1.80V   1.70V   1.90V
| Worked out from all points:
|   slope of the pulldown table from 0 to 0.27 V, typ, clamps not added: 20.3 ohm
|   slope of the pullup table from 0 to 0.27 V, typ, clamps not added: 19.5 ohm
|   GND clamp passes 1 mA (typ) near -0.57 V on its own axis
|   POWER clamp passes 1 mA (typ) near -0.52 V on its own axis
|   rising waveform, R_fixture 50.00, V_fixture 0.000: 20-80 % time 2.93ns typ, 4.66ns min, 2ns max; typ from 0 V to 1.22 V
|   rising waveform, R_fixture 50.00, V_fixture 1.80: 20-80 % time 675ps typ, 626ps min, 655ps max; typ from 0.55 V to 1.8 V
|   falling waveform, R_fixture 50.00, V_fixture 0.000: 20-80 % time 626ps typ, 595ps min, 508ps max; typ from 1.23 V to 0 V
|   falling waveform, R_fixture 50.00, V_fixture 1.80: 20-80 % time 1.31ns typ, 2.12ns min, 817ps max; typ from 1.8 V to 0.55 V
[Pulldown]
| voltage   I(typ)   I(min)   I(max)
-1.8V     -32.1mA    -21.59mA   -36.84mA
-700mV    -32.1mA    -21.59mA   -36.84mA
900mV     35.92mA    26.22mA    43.22mA
2.2V      50.41mA    45.67mA    64.56mA
2.3V      50.73mA    100mA      64.77mA
2.4V      53.28mA    210mA      65.06mA
2.5V      87.07mA    340mA      66.53mA
2.6V      190mA      480mA      77.64mA
2.7V      330mA      620mA      150mA
2.9V      630mA      920mA      420mA
3.1V      940mA      1.22A      730mA
3.6V      1.75A      1.99A      1.53A
[Pullup]
| voltage   I(typ)   I(min)   I(max)
-1.8V     39.53mA    22.35mA    50.25mA
-600mV    39.53mA    22.35mA    50.25mA
600mV     -25.23mA   -18.99mA   -34.06mA
2.2V      -36.44mA   -27.71mA   -51.87mA
2.4V      -37.84mA   -60.77mA   -52.52mA
2.5V      -43.04mA   -150mA     -53.71mA
2.6V      -68.77mA   -290mA     -59.14mA
2.7V      -170mA     -430mA     -73.59mA
2.8V      -310mA     -590mA     -140mA
2.9V      -470mA     -750mA     -270mA
3.1V      -800mA     -1.08A     -590mA
3.6V      -1.66A     -1.92A     -1.44A
[GND_clamp]
| voltage   I(typ)   I(min)   I(max)
-1.8V     -1.65A     -1.74A     -1.6A
-1.2V     -620mA     -740mA     -570mA
-1.1V     -450mA     -580mA     -410mA
-1V       -290mA     -420mA     -250mA
-900mV    -150mA     -270mA     -110mA
-800mV    -40.97mA   -140mA     -27.17mA
-700mV    -7.54mA    -40.17mA   -8.08mA
-600mV    -1.39mA    -5.57mA    -1.57mA
-500mV    -120uA     -660uA     -120uA
1.8V      34.27pA    98.88nA    22.46pA
[POWER_clamp]
| voltage   I(typ)   I(min)   I(max)
-1.8V     1.73A      1.82A      1.67A
-1.7V     1.57A      1.66A      1.51A
-1.4V     1.08A      1.21A      1.02A
-1.3V     930mA      1.05A      870mA
-1.1V     610mA      760mA      550mA
-900mV    310mA      460mA      250mA
-800mV    170mA      320mA      120mA
-700mV    52.75mA    190mA      22.81mA
-600mV    4.57mA     79.88mA    2.44mA
-500mV    270uA      13.45mA    250uA
-400mV    16.38uA    820uA      14.46uA
0V        34.27pA    1.07nA     29.84pA
[Ramp]
| variable   typ   min   max
dV/dt_r   0.73/2.94n   0.60/4.34n   0.86/1.99n
dV/dt_f   0.75/1.29n   0.63/2.12n   0.83/0.86n
R_load = 50.00
[Rising Waveform]
R_fixture = 50.00
V_fixture = 0.000
| time   V(typ)   V(min)   V(max)
0s        0V         0V         0V
2.1ns     -3.44mV    -5.21mV    48.75mV
2.7ns     19.76mV    -1.88mV    220mV
3.3ns     99.12mV    7.58mV     490mV
4.8ns     490mV      130mV      1.13V
6ns       800mV      310mV      1.34V
7.5ns     1.06V      550mV      1.4V
8.7ns     1.15V      700mV      1.42V
11.1ns    1.21V      900mV      1.43V
15ns      1.22V      1.02V      1.43V
[Rising Waveform]
R_fixture = 50.00
V_fixture = 1.80
V_fixture_min = 1.70
V_fixture_max = 1.90
| time   V(typ)   V(min)   V(max)
0s        550mV      650mV      520mV
300ps     550mV      650mV      520mV
600ps     560mV      650mV      620mV
900ps     880mV      710mV      1.24V
1.2ns     1.3V       940mV      1.54V
1.5ns     1.55V      1.32V      1.72V
1.8ns     1.7V       1.55V      1.83V
2.1ns     1.75V      1.62V      1.86V
4.2ns     1.8V       1.7V       1.9V
15ns      1.8V       1.7V       1.9V
[Falling Waveform]
R_fixture = 50.00
V_fixture = 0.000
| time   V(typ)   V(min)   V(max)
0s        1.23V      1.02V      1.43V
300ps     1.23V      1.02V      1.43V
600ps     1.22V      1.02V      1.32V
900ps     880mV      970mV      660mV
1.2ns     480mV      730mV      270mV
1.5ns     180mV      360mV      58.97mV
1.8ns     29.34mV    110mV      6.18mV
2.1ns     6.35mV     38.1mV     2.45mV
2.7ns     1.6mV      4.85mV     990uV
15ns      -9.24uV    60.8uV     41.97uV
[Falling Waveform]
R_fixture = 50.00
V_fixture = 1.80
V_fixture_min = 1.70
V_fixture_max = 1.90
| time   V(typ)   V(min)   V(max)
0s        1.8V       1.7V       1.9V
900ps     1.82V      1.71V      1.9V
1.2ns     1.81V      1.72V      1.77V
1.5ns     1.71V      1.71V      1.48V
1.8ns     1.5V       1.65V      1.08V
2.1ns     1.3V       1.57V      830mV
3ns       810mV      1.25V      590mV
4.2ns     630mV      910mV      540mV
5.7ns     580mV      740mV      520mV
15ns      550mV      660mV      520mV
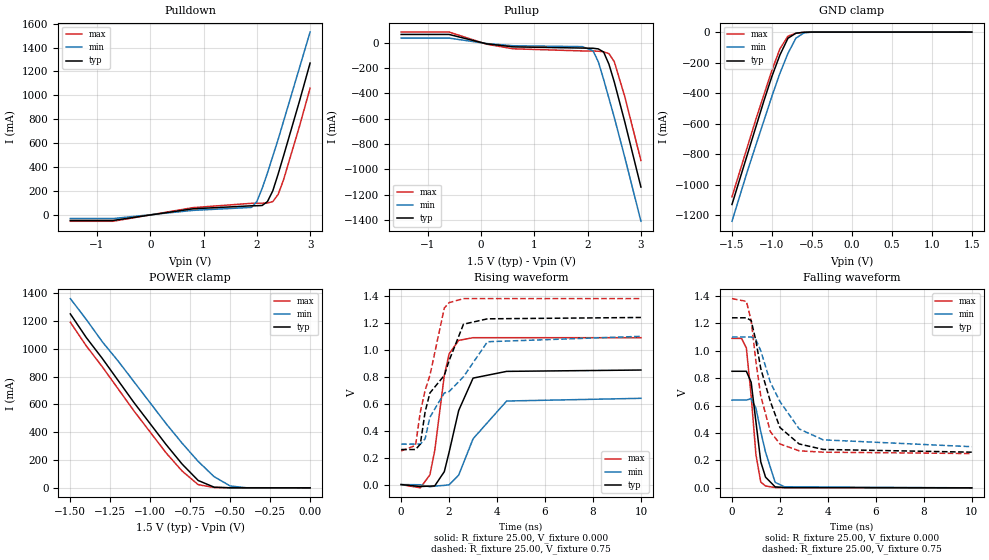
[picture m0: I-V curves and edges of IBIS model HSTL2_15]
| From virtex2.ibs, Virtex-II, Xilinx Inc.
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|   Model HSTL2_15
[Model]   HSTL2_15
Model_type   I/O
Polarity   Non-Inverting
Enable   Active-Low
Vinh = 0.85V
Vinl = 0.65V
Vmeas =   0.75V
Cref =  0pF
Rref =  25.00
Vref =   0.75V
C_comp   10.00pF   10.00pF   10.00pF
[Temperature Range]   25.00   100.00   0.000
[Voltage Range]   1.50V   1.40V   1.60V
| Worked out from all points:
|   slope of the pulldown table from 0 to 0.225 V, typ, clamps not added: 13.5 ohm
|   slope of the pullup table from 0 to 0.225 V, typ, clamps not added: 13.2 ohm
|   GND clamp passes 1 mA (typ) near -0.57 V on its own axis
|   POWER clamp passes 1 mA (typ) near -0.52 V on its own axis
|   rising waveform, R_fixture 25.00, V_fixture 0.000: 20-80 % time 742ps typ, 1ns min, 514ps max; typ from 0 V to 0.85 V
|   rising waveform, R_fixture 25.00, V_fixture 0.75: 20-80 % time 1.28ns typ, 1.79ns min, 837ps max; typ from 0.26 V to 1.24 V
|   falling waveform, R_fixture 25.00, V_fixture 0.000: 20-80 % time 374ps typ, 496ps min, 338ps max; typ from 0.85 V to 0 V
|   falling waveform, R_fixture 25.00, V_fixture 0.75: 20-80 % time 934ps typ, 1.33ns min, 654ps max; typ from 1.24 V to 0.26 V
[Pulldown]
| voltage   I(typ)   I(min)   I(max)
-1.5V     -48.01mA   -32.31mA   -55.01mA
-700mV    -48.01mA   -32.31mA   -55.01mA
800mV     49.4mA     36.24mA    59.06mA
1.9V      74.61mA    61.23mA    95.45mA
2V        75.14mA    110mA      96.07mA
2.1V      77.32mA    220mA      96.63mA
2.2V      110mA      350mA      98.03mA
2.3V      200mA      490mA      110mA
2.4V      340mA      630mA      170mA
2.5V      490mA      780mA      290mA
2.8V      950mA      1.23A      740mA
3V        1.27A      1.53A      1.06A
[Pullup]
| voltage   I(typ)   I(min)   I(max)
-1.5V     65.27mA    36.47mA    84.3mA
-600mV    65.27mA    36.47mA    84.3mA
100mV     -8.32mA    -6.21mA    -11.27mA
600mV     -32.72mA   -23.85mA   -47.93mA
1.9V      -42.19mA   -30.93mA   -64.82mA
2.1V      -43.7mA    -63.33mA   -65.77mA
2.2V      -48.81mA   -150mA     -66.99mA
2.3V      -73.48mA   -290mA     -72.22mA
2.4V      -170mA     -440mA     -85.88mA
2.5V      -310mA     -590mA     -150mA
2.7V      -630mA     -910mA     -430mA
3V        -1.14A     -1.41A     -930mA
[GND_clamp]
| voltage   I(typ)   I(min)   I(max)
-1.5V     -1.13A     -1.24A     -1.08A
-1.3V     -790mA     -900mA     -740mA
-1.2V     -620mA     -740mA     -570mA
-1.1V     -450mA     -580mA     -410mA
-1V       -290mA     -420mA     -250mA
-900mV    -150mA     -270mA     -110mA
-800mV    -40.96mA   -140mA     -27.15mA
-700mV    -7.52mA    -40.16mA   -8.06mA
-600mV    -1.38mA    -5.56mA    -1.57mA
-500mV    -120uA     -650uA     -120uA
1.5V      27.96pA    98.69nA    16.96pA
[POWER_clamp]
| voltage   I(typ)   I(min)   I(max)
-1.5V     1.25A      1.36A      1.19A
-1.4V     1.08A      1.21A      1.02A
-1.3V     930mA      1.05A      870mA
-1.2V     770mA      910mA      710mA
-1.1V     610mA      760mA      550mA
-900mV    310mA      460mA      250mA
-800mV    170mA      320mA      120mA
-700mV    52.75mA    190mA      22.81mA
-600mV    4.57mA     79.88mA    2.44mA
-500mV    270uA      13.45mA    250uA
-400mV    16.38uA    820uA      14.46uA
0V        27.96pA    880pA      24.27pA
[Ramp]
| variable   typ   min   max
dV/dt_r   0.51/0.72n   0.39/1.02n   0.65/0.49n
dV/dt_f   0.56/1.06n   0.46/1.70n   0.64/0.73n
R_load = 25.00
[Rising Waveform]
R_fixture = 25.00
V_fixture = 0.000
| time   V(typ)   V(min)   V(max)
0s        0V         0V         0V
800ps     -14.43mV   -1.44mV    -24.27mV
1.2ns     -11.64mV   -16.53mV   72.32mV
1.4ns     -9.87mV    -11.37mV   250mV
1.8ns     95.81mV    -6.06mV    810mV
2ns       240mV      -2.24mV    970mV
2.4ns     550mV      70.53mV    1.07V
3ns       790mV      340mV      1.09V
4.4ns     840mV      620mV      1.09V
10ns      850mV      640mV      1.09V
[Rising Waveform]
R_fixture = 25.00
V_fixture = 0.75
V_fixture_min = 0.70
V_fixture_max = 0.80
| time   V(typ)   V(min)   V(max)
0s        260mV      300mV      250mV
600ps     260mV      300mV      290mV
800ps     300mV      300mV      540mV
1ns       540mV      340mV      700mV
1.2ns     680mV      500mV      810mV
1.8ns     810mV      680mV      1.31V
2ns       920mV      690mV      1.35V
2.6ns     1.19V      800mV      1.38V
3.6ns     1.23V      1.06V      1.38V
10ns      1.24V      1.1V       1.38V
[Falling Waveform]
R_fixture = 25.00
V_fixture = 0.000
| time   V(typ)   V(min)   V(max)
0s        850mV      640mV      1.09V
400ps     850mV      640mV      1.09V
600ps     850mV      640mV      1.02V
800ps     770mV      650mV      670mV
1ns       480mV      580mV      240mV
1.2ns     190mV      410mV      42.42mV
1.4ns     77.99mV    260mV      13.54mV
1.8ns     7.06mV     39.98mV    2.31mV
2.2ns     2.08mV     6.76mV     1.44mV
10ns      4.42uV     26.57uV    990nV
[Falling Waveform]
R_fixture = 25.00
V_fixture = 0.75
V_fixture_min = 0.70
V_fixture_max = 0.80
| time   V(typ)   V(min)   V(max)
0s        1.24V      1.1V       1.38V
600ps     1.24V      1.1V       1.36V
800ps     1.22V      1.1V       1.22V
1ns       1.07V      1.08V      920mV
1.2ns     870mV      1V         670mV
1.6ns     630mV      770mV      410mV
2ns       440mV      630mV      320mV
2.8ns     320mV      430mV      270mV
3.8ns     280mV      350mV      260mV
10ns      260mV      300mV      250mV
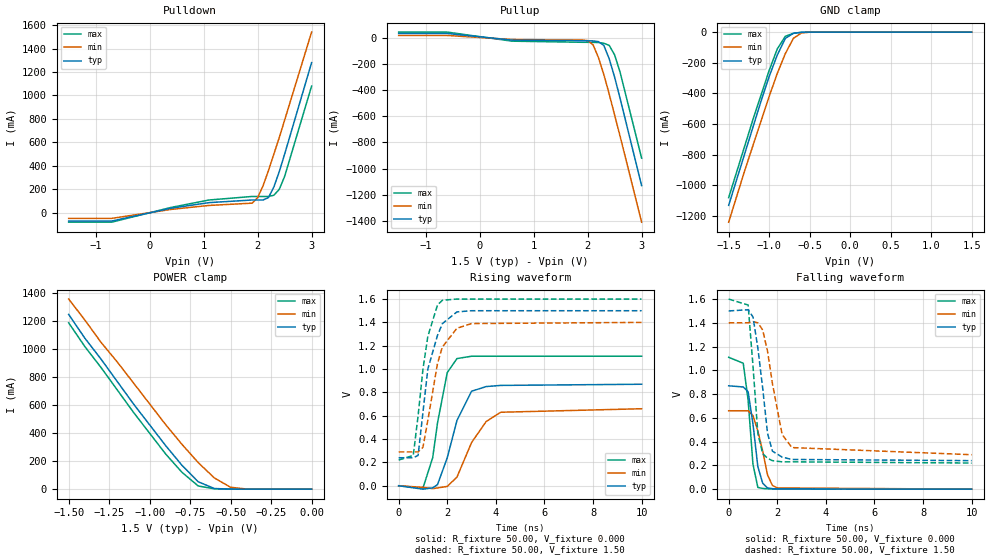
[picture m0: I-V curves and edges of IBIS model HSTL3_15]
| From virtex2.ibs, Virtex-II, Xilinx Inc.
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|   Model HSTL3_15
[Model]   HSTL3_15
Model_type   I/O
Polarity   Non-Inverting
Enable   Active-Low
Vinh = 1.0V
Vinl = 0.8V
Vmeas =   0.90V
Cref =  0pF
Rref =  50.00
Vref =   1.50V
C_comp   10.00pF   10.00pF   10.00pF
[Temperature Range]   25.00   100.00   0.000
[Voltage Range]   1.50V   1.40V   1.60V
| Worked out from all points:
|   slope of the pulldown table from 0 to 0.225 V, typ, clamps not added: 9.45 ohm
|   slope of the pullup table from 0 to 0.225 V, typ, clamps not added: 25.4 ohm
|   GND clamp passes 1 mA (typ) near -0.57 V on its own axis
|   POWER clamp passes 1 mA (typ) near -0.52 V on its own axis
|   rising waveform, R_fixture 50.00, V_fixture 0.000: 20-80 % time 728ps typ, 960ps min, 525ps max; typ from 0 V to 0.87 V
|   rising waveform, R_fixture 50.00, V_fixture 1.50: 20-80 % time 610ps typ, 625ps min, 520ps max; typ from 0.24 V to 1.5 V
|   falling waveform, R_fixture 50.00, V_fixture 0.000: 20-80 % time 331ps typ, 446ps min, 285ps max; typ from 0.87 V to 0 V
|   falling waveform, R_fixture 50.00, V_fixture 1.50: 20-80 % time 433ps typ, 559ps min, 302ps max; typ from 1.5 V to 0.24 V
[Pulldown]
| voltage   I(typ)   I(min)   I(max)
-1.5V     -68.82mA   -46.41mA   -79.05mA
-700mV    -68.82mA   -46.41mA   -78.66mA
400mV     40.25mA    30.01mA    47.04mA
1.1V      87.62mA    63.65mA    110mA
1.9V      110mA      83.13mA    140mA
2V        110mA      130mA      140mA
2.1V      110mA      230mA      140mA
2.2V      130mA      360mA      140mA
2.3V      220mA      500mA      150mA
2.4V      350mA      640mA      200mA
2.5V      500mA      790mA      310mA
3V        1.28A      1.54A      1.08A
[Pullup]
| voltage   I(typ)   I(min)   I(max)
-1.5V     34.03mA    18.7mA     44.55mA
-600mV    34.03mA    18.7mA     44.55mA
600mV     -16.93mA   -12.32mA   -24.89mA
1.9V      -21.75mA   -16.25mA   -33.42mA
2V        -21.99mA   -20.67mA   -33.66mA
2.1V      -23.18mA   -51.96mA   -33.96mA
2.2V      -28.75mA   -150mA     -35.25mA
2.3V      -57.37mA   -280mA     -41.07mA
2.4V      -160mA     -430mA     -56.91mA
2.5V      -300mA     -590mA     -130mA
2.6V      -460mA     -750mA     -260mA
3V        -1.13A     -1.41A     -920mA
[GND_clamp]
| voltage   I(typ)   I(min)   I(max)
-1.5V     -1.13A     -1.24A     -1.08A
-1.3V     -790mA     -900mA     -740mA
-1.2V     -620mA     -740mA     -570mA
-1.1V     -450mA     -580mA     -410mA
-1V       -290mA     -420mA     -250mA
-900mV    -150mA     -270mA     -110mA
-800mV    -40.96mA   -140mA     -27.15mA
-700mV    -7.52mA    -40.16mA   -8.06mA
-600mV    -1.38mA    -5.56mA    -1.57mA
-500mV    -120uA     -650uA     -120uA
1.5V      27.96pA    98.69nA    16.96pA
[POWER_clamp]
| voltage   I(typ)   I(min)   I(max)
-1.5V     1.25A      1.36A      1.19A
-1.4V     1.08A      1.21A      1.02A
-1.3V     930mA      1.05A      870mA
-1.2V     770mA      910mA      710mA
-1.1V     610mA      760mA      550mA
-900mV    310mA      460mA      250mA
-800mV    170mA      320mA      120mA
-700mV    52.75mA    190mA      22.81mA
-600mV    4.57mA     79.88mA    2.44mA
-500mV    270uA      13.45mA    250uA
-400mV    16.38uA    820uA      14.46uA
0V        27.96pA    880pA      24.27pA
[Ramp]
| variable   typ   min   max
dV/dt_r   0.52/0.72n   0.40/0.95n   0.67/0.51n
dV/dt_f   0.76/0.36n   0.67/0.55n   0.83/0.28n
R_load = 50.00
[Rising Waveform]
R_fixture = 50.00
V_fixture = 0.000
| time   V(typ)   V(min)   V(max)
0s        0V         0V         0V
1ns       -29.26mV   -13.81mV   -19.38mV
1.4ns     -18.08mV   -24.93mV   240mV
1.6ns     10.2mV     -18.51mV   540mV
2ns       240mV      -5.63mV    970mV
2.4ns     560mV      74.62mV    1.09V
3ns       810mV      370mV      1.11V
3.6ns     850mV      550mV      1.11V
4.2ns     860mV      630mV      1.11V
10ns      870mV      660mV      1.11V
[Rising Waveform]
R_fixture = 50.00
V_fixture = 1.50
V_fixture_min = 1.40
V_fixture_max = 1.60
| time   V(typ)   V(min)   V(max)
0s        240mV      290mV      220mV
600ps     240mV      290mV      260mV
800ps     260mV      290mV      600mV
1ns       630mV      330mV      1V
1.2ns     1V         560mV      1.28V
1.6ns     1.29V      1.05V      1.55V
1.8ns     1.39V      1.19V      1.59V
2.4ns     1.49V      1.35V      1.6V
3ns       1.5V       1.39V      1.6V
10ns      1.5V       1.4V       1.6V
[Falling Waveform]
R_fixture = 50.00
V_fixture = 0.000
| time   V(typ)   V(min)   V(max)
0s        870mV      660mV      1.11V
600ps     860mV      660mV      1.06V
800ps     820mV      660mV      750mV
1ns       550mV      620mV      210mV
1.2ns     190mV      490mV      14.99mV
1.4ns     50.29mV    320mV      6.2mV
1.6ns     9.71mV     120mV      3.15mV
1.8ns     4.06mV     31.42mV    2.05mV
2ns       2.62mV     10.4mV     1.4mV
10ns      970nV      -680nV     0V
[Falling Waveform]
R_fixture = 50.00
V_fixture = 1.50
V_fixture_min = 1.40
V_fixture_max = 1.60
| time   V(typ)   V(min)   V(max)
0s        1.5V       1.4V       1.6V
800ps     1.51V      1.4V       1.55V
1ns       1.45V      1.41V      1.04V
1.2ns     1.19V      1.4V       470mV
1.4ns     850mV      1.34V      300mV
1.6ns     470mV      1.16V      260mV
1.8ns     320mV      890mV      240mV
2.2ns     270mV      460mV      230mV
2.6ns     250mV      350mV      230mV
10ns      240mV      290mV      220mV
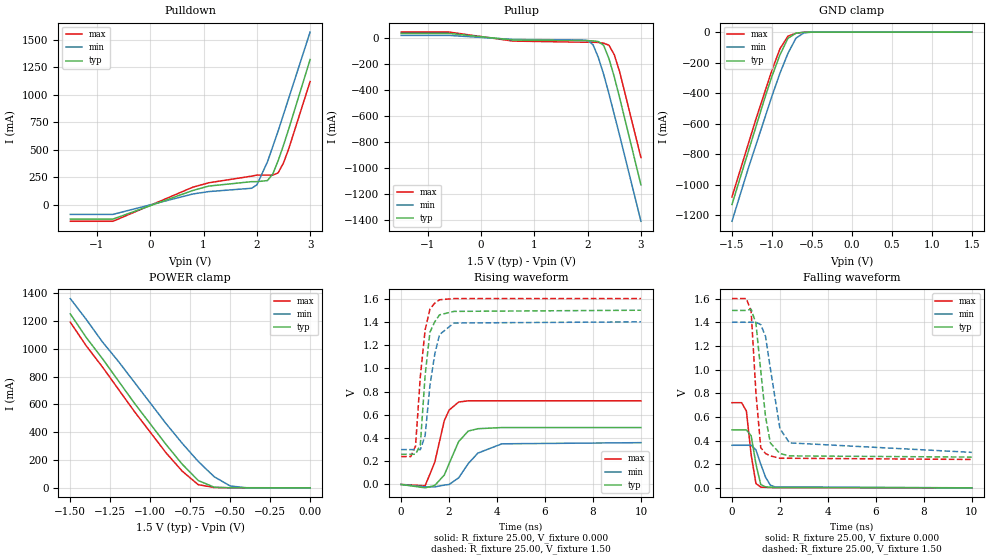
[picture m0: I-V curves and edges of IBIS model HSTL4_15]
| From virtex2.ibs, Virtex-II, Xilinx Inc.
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|   Model HSTL4_15
[Model]   HSTL4_15
Model_type   I/O
Polarity   Non-Inverting
Enable   Active-Low
Vinh = 1.0V
Vinl = 0.8V
Vmeas =   0.90V
Cref =  0pF
Rref =  25.00
Vref =   1.50V
C_comp   10.00pF   10.00pF   10.00pF
[Temperature Range]   25.00   100.00   0.000
[Voltage Range]   1.50V   1.40V   1.60V
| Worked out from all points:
|   slope of the pulldown table from 0 to 0.225 V, typ, clamps not added: 5.11 ohm
|   slope of the pullup table from 0 to 0.225 V, typ, clamps not added: 25.4 ohm
|   GND clamp passes 1 mA (typ) near -0.57 V on its own axis
|   POWER clamp passes 1 mA (typ) near -0.52 V on its own axis
|   rising waveform, R_fixture 25.00, V_fixture 0.000: 20-80 % time 640ps typ, 864ps min, 532ps max; typ from 0 V to 0.49 V
|   rising waveform, R_fixture 25.00, V_fixture 1.50: 20-80 % time 313ps typ, 424ps min, 338ps max; typ from 0.26 V to 1.5 V
|   falling waveform, R_fixture 25.00, V_fixture 0.000: 20-80 % time 278ps typ, 401ps min, 272ps max; typ from 0.49 V to 0 V
|   falling waveform, R_fixture 25.00, V_fixture 1.50: 20-80 % time 415ps typ, 506ps min, 278ps max; typ from 1.5 V to 0.26 V
[Pulldown]
| voltage   I(typ)   I(min)   I(max)
-1.5V     -130mA     -87.53mA   -150mA
-700mV    -130mA     -87.53mA   -150mA
800mV     130mA      98.25mA    160mA
1.1V      170mA      120mA      200mA
1.9V      210mA      150mA      260mA
2V        210mA      180mA      270mA
2.2V      220mA      390mA      270mA
2.3V      280mA      530mA      270mA
2.4V      400mA      670mA      290mA
2.5V      540mA      820mA      380mA
2.6V      690mA      970mA      510mA
3V        1.32A      1.57A      1.12A
[Pullup]
| voltage   I(typ)   I(min)   I(max)
-1.5V     34.03mA    18.7mA     44.55mA
-600mV    34.03mA    18.7mA     44.55mA
600mV     -16.93mA   -12.32mA   -24.89mA
1.9V      -21.75mA   -16.25mA   -33.42mA
2V        -21.99mA   -20.67mA   -33.66mA
2.1V      -23.18mA   -51.96mA   -33.96mA
2.2V      -28.75mA   -150mA     -35.25mA
2.3V      -57.37mA   -280mA     -41.07mA
2.4V      -160mA     -430mA     -56.91mA
2.5V      -300mA     -590mA     -130mA
2.6V      -460mA     -750mA     -260mA
3V        -1.13A     -1.41A     -920mA
[GND_clamp]
| voltage   I(typ)   I(min)   I(max)
-1.5V     -1.13A     -1.24A     -1.08A
-1.3V     -790mA     -900mA     -740mA
-1.2V     -620mA     -740mA     -570mA
-1.1V     -450mA     -580mA     -410mA
-1V       -290mA     -420mA     -250mA
-900mV    -150mA     -270mA     -110mA
-800mV    -40.96mA   -140mA     -27.15mA
-700mV    -7.52mA    -40.16mA   -8.06mA
-600mV    -1.38mA    -5.56mA    -1.57mA
-500mV    -120uA     -650uA     -120uA
1.5V      27.96pA    98.69nA    16.96pA
[POWER_clamp]
| voltage   I(typ)   I(min)   I(max)
-1.5V     1.25A      1.36A      1.19A
-1.4V     1.08A      1.21A      1.02A
-1.3V     930mA      1.05A      870mA
-1.2V     770mA      910mA      710mA
-1.1V     610mA      760mA      550mA
-900mV    310mA      460mA      250mA
-800mV    170mA      320mA      120mA
-700mV    52.75mA    190mA      22.81mA
-600mV    4.57mA     79.88mA    2.44mA
-500mV    270uA      13.45mA    250uA
-400mV    16.38uA    820uA      14.46uA
0V        27.96pA    880pA      24.27pA
[Ramp]
| variable   typ   min   max
dV/dt_r   0.30/0.63n   0.21/0.85n   0.43/0.50n
dV/dt_f   0.75/0.30n   0.66/0.49n   0.82/0.23n
R_load = 25.00
[Rising Waveform]
R_fixture = 25.00
V_fixture = 0.000
| time   V(typ)   V(min)   V(max)
0s        0V         0V         0V
1ns       -28.98mV   -19.94mV   -11.17mV
1.4ns     -8.55mV    -20.62mV   190mV
1.8ns     81.48mV    -5.53mV    550mV
2ns       180mV      -83.5uV    640mV
2.4ns     370mV      57.31mV    710mV
2.8ns     460mV      180mV      720mV
3.2ns     480mV      270mV      720mV
4.2ns     490mV      350mV      720mV
10ns      490mV      360mV      720mV
[Rising Waveform]
R_fixture = 25.00
V_fixture = 1.50
V_fixture_min = 1.40
V_fixture_max = 1.60
| time   V(typ)   V(min)   V(max)
0s        260mV      300mV      240mV
400ps     260mV      300mV      240mV
600ps     260mV      300mV      330mV
800ps     340mV      300mV      930mV
1ns       940mV      420mV      1.33V
1.2ns     1.31V      850mV      1.51V
1.4ns     1.4V       1.12V      1.56V
1.6ns     1.46V      1.29V      1.59V
2.2ns     1.49V      1.39V      1.6V
10ns      1.5V       1.4V       1.6V
[Falling Waveform]
R_fixture = 25.00
V_fixture = 0.000
| time   V(typ)   V(min)   V(max)
0s        490mV      360mV      720mV
400ps     490mV      360mV      720mV
600ps     490mV      360mV      650mV
800ps     440mV      360mV      280mV
1ns       200mV      320mV      36.15mV
1.2ns     27.2mV     200mV      6.06mV
1.4ns     8.5mV      90.51mV    4.1mV
1.6ns     4.89mV     22.57mV    2.63mV
1.8ns     3.12mV     7.44mV     1.76mV
10ns      0V         640nV      0V
[Falling Waveform]
R_fixture = 25.00
V_fixture = 1.50
V_fixture_min = 1.40
V_fixture_max = 1.60
| time   V(typ)   V(min)   V(max)
0s        1.5V       1.4V       1.6V
600ps     1.5V       1.4V       1.6V
800ps     1.51V      1.4V       1.49V
1ns       1.39V      1.4V       800mV
1.2ns     990mV      1.38V      340mV
1.4ns     600mV      1.28V      290mV
1.6ns     380mV      1.01V      270mV
2ns       290mV      500mV      250mV
2.4ns     270mV      380mV      250mV
10ns      260mV      300mV      240mV
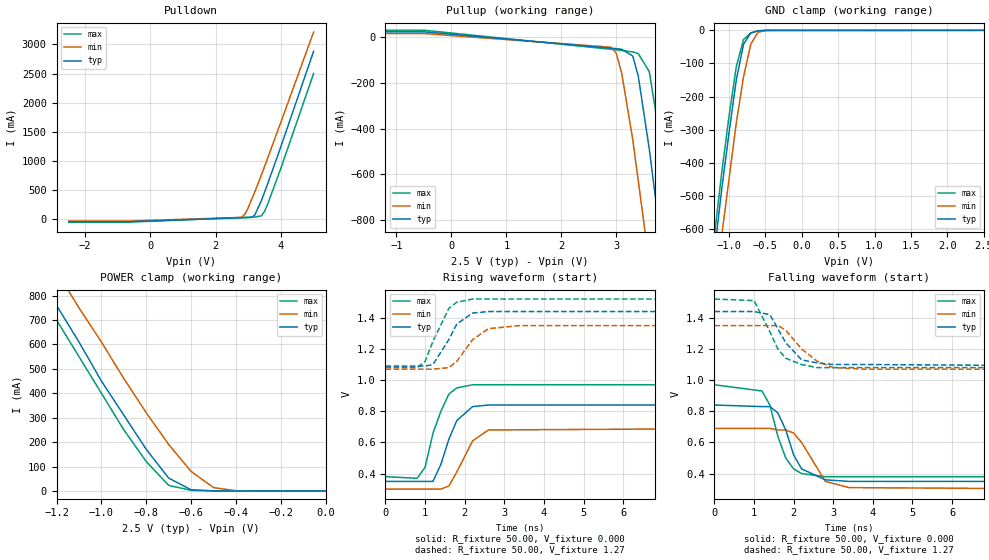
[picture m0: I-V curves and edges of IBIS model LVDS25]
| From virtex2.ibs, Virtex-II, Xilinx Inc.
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|   Model LVDS25
[Model]   LVDS25
Model_type   I/O
Polarity   Non-Inverting
Enable   Active-Low
Vinh = 1.4v
Vinl = 1.0v
Vmeas =   1.20V
Cref =  0pF
Rref =  50.00
Vref =   1.20V
C_comp   10.00pF   10.00pF   10.00pF
[Temperature Range]   25.00   100.00   0.000
[Voltage Range]   2.50V   2.30V   2.70V
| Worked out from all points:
|   slope of the pulldown table from 0 to 0.375 V, typ, clamps not added: 36.4 ohm
|   slope of the pullup table from 0 to 0.375 V, typ, clamps not added: 56.3 ohm
|   GND clamp passes 1 mA (typ) near -0.57 V on its own axis
|   POWER clamp passes 1 mA (typ) near -0.52 V on its own axis
|   rising waveform, R_fixture 50.00, V_fixture 0.000: 20-80 % time 428ps typ, 479ps min, 442ps max; typ from 0.35 V to 0.84 V
|   rising waveform, R_fixture 50.00, V_fixture 1.27: 20-80 % time 422ps typ, 553ps min, 464ps max; typ from 1.09 V to 1.44 V
|   falling waveform, R_fixture 50.00, V_fixture 0.000: 20-80 % time 473ps typ, 528ps min, 432ps max; typ from 0.84 V to 0.35 V
|   falling waveform, R_fixture 50.00, V_fixture 1.27: 20-80 % time 539ps typ, 656ps min, 533ps max; typ from 1.44 V to 1.09 V
[Pulldown]
| voltage   I(typ)   I(min)   I(max)
-2.5V     -40.4mA    -28.49mA   -48.63mA
-700mV    -40.4mA    -28.49mA   -48.63mA
2.8V      26.93mA    32.95mA    32.89mA
2.9V      28.43mA    94.12mA    34.57mA
3V        30.09mA    200mA      36.23mA
3.1V      34.6mA     340mA      37.89mA
3.2V      74.59mA    470mA      39.89mA
3.4V      320mA      760mA      60.32mA
3.5V      470mA      910mA      140mA
3.6V      620mA      1.06A      270mA
4V        1.25A      1.67A      880mA
5V        2.88A      3.21A      2.5A
[Pullup]
| voltage   I(typ)   I(min)   I(max)
-2.5V     24.97mA    16.95mA    32.29mA
-500mV    24.54mA    16.95mA    31.61mA
2.9V      -47mA      -42.9mA    -52.01mA
3V        -49.22mA   -69.62mA   -54.76mA
3.1V      -52.1mA    -160mA     -57.44mA
3.3V      -81.76mA   -450mA     -63.61mA
3.4V      -170mA     -630mA     -71.3mA
3.6V      -490mA     -990mA     -150mA
3.8V      -870mA     -1.36A     -450mA
4V        -1.27A     -1.74A     -830mA
4.2V      -1.68A     -2.13A     -1.22A
5V        -3.35A     -3.69A     -2.88A
[GND_clamp]
| voltage   I(typ)   I(min)   I(max)
-2.5V     -3.34A     -3.3A      -3.3A
-1.2V     -670mA     -800mA     -620mA
-1.1V     -480mA     -620mA     -430mA
-1V       -310mA     -450mA     -260mA
-900mV    -150mA     -280mA     -110mA
-800mV    -41.81mA   -140mA     -27.69mA
-700mV    -7.62mA    -40.98mA   -8.11mA
-600mV    -1.38mA    -5.69mA    -1.55mA
-500mV    -120uA     -670uA     -110uA
2.5V      540pA      2.11uA     480pA
[POWER_clamp]
| voltage   I(typ)   I(min)   I(max)
-2.5V     2.86A      2.89A      2.8A
-1.3V     920mA      1.05A      860mA
-1.2V     760mA      900mA      700mA
-1.1V     610mA      750mA      550mA
-1V       450mA      610mA      400mA
-900mV    310mA      460mA      250mA
-800mV    170mA      320mA      120mA
-700mV    52.5mA     190mA      22.73mA
-600mV    4.56mA     79.5mA     2.44mA
-500mV    270uA      13.41mA    250uA
-400mV    16.38uA    820uA      14.45uA
0V        540pA      2.08nA     580pA
[Ramp]
| variable   typ   min   max
dV/dt_r   0.29/0.41n   0.23/0.46n   0.35/0.35n
dV/dt_f   0.12/0.19n   90.00m/0.22n   0.17/0.18n
R_load = 50.00
[Rising Waveform]
R_fixture = 50.00
V_fixture = 0.000
| time   V(typ)   V(min)   V(max)
0s        350mV      300mV      380mV
800ps     350mV      300mV      370mV
1ns       350mV      300mV      440mV
1.2ns     350mV      300mV      660mV
1.4ns     460mV      300mV      800mV
1.6ns     620mV      320mV      910mV
1.8ns     740mV      410mV      950mV
2.2ns     830mV      610mV      970mV
2.6ns     840mV      680mV      970mV
10ns      840mV      690mV      970mV
[Rising Waveform]
R_fixture = 50.00
V_fixture = 1.27
V_fixture_min = 1.21
V_fixture_max = 1.30
| time   V(typ)   V(min)   V(max)
0s        1.09V      1.07V      1.08V
800ps     1.09V      1.07V      1.08V
1ns       1.09V      1.07V      1.12V
1.2ns     1.1V       1.07V      1.25V
1.6ns     1.26V      1.08V      1.46V
1.8ns     1.36V      1.12V      1.5V
2.2ns     1.43V      1.26V      1.52V
2.6ns     1.44V      1.33V      1.52V
3.4ns     1.44V      1.35V      1.52V
10ns      1.44V      1.35V      1.52V
[Falling Waveform]
R_fixture = 50.00
V_fixture = 0.000
| time   V(typ)   V(min)   V(max)
0s        840mV      690mV      970mV
1.2ns     830mV      690mV      930mV
1.4ns     830mV      690mV      840mV
1.6ns     790mV      680mV      640mV
1.8ns     680mV      680mV      500mV
2ns       520mV      660mV      430mV
2.2ns     430mV      600mV      400mV
2.8ns     360mV      350mV      380mV
3.4ns     350mV      310mV      380mV
10ns      350mV      300mV      380mV
[Falling Waveform]
R_fixture = 50.00
V_fixture = 1.27
V_fixture_min = 1.21
V_fixture_max = 1.30
| time   V(typ)   V(min)   V(max)
0s        1.44V      1.35V      1.52V
1ns       1.44V      1.35V      1.51V
1.4ns     1.42V      1.35V      1.31V
1.6ns     1.33V      1.35V      1.2V
1.8ns     1.24V      1.32V      1.14V
2.2ns     1.13V      1.2V       1.1V
2.6ns     1.11V      1.12V      1.08V
3ns       1.1V       1.08V      1.08V
3.8ns     1.1V       1.07V      1.08V
10ns      1.09V      1.07V      1.08V
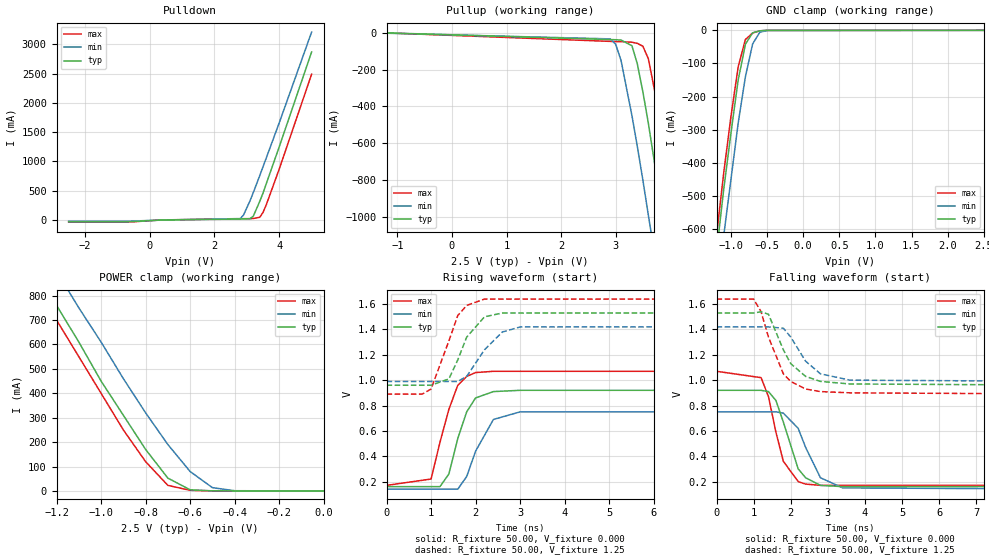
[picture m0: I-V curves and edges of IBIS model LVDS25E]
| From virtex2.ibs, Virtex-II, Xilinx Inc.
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|   Model LVDS25E
[Model]   LVDS25E
Model_type   I/O
Polarity   Non-Inverting
Enable   Active-Low
Vinh = 1.5v
Vinl = 0.8v
Vmeas =   1.20V
Cref =  0pF
Rref =  50.00
Vref =   1.20V
C_comp   10.00pF   10.00pF   10.00pF
[Temperature Range]   25.00   100.00   0.000
[Voltage Range]   2.50V   2.30V   2.70V
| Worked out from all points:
|   slope of the pulldown table from 0 to 0.375 V, typ, clamps not added: 44.9 ohm
|   slope of the pullup table from 0 to 0.375 V, typ, clamps not added: 112 ohm
|   GND clamp passes 1 mA (typ) near -0.57 V on its own axis
|   POWER clamp passes 1 mA (typ) near -0.52 V on its own axis
|   rising waveform, R_fixture 50.00, V_fixture 0.000: 20-80 % time 396ps typ, 440ps min, 437ps max; typ from 0.16 V to 0.92 V
|   rising waveform, R_fixture 50.00, V_fixture 1.25: 20-80 % time 453ps typ, 524ps min, 451ps max; typ from 0.96 V to 1.53 V
|   falling waveform, R_fixture 50.00, V_fixture 0.000: 20-80 % time 499ps typ, 547ps min, 445ps max; typ from 0.92 V to 0.16 V
|   falling waveform, R_fixture 50.00, V_fixture 1.25: 20-80 % time 627ps typ, 659ps min, 583ps max; typ from 1.53 V to 0.96 V
[Pulldown]
| voltage   I(typ)   I(min)   I(max)
-2.5V     -30.5mA    -20.63mA   -36.59mA
-700mV    -30.5mA    -20.63mA   -36.59mA
400mV     1.23mA     710uA      2.36mA
2.8V      17.44mA    25.24mA    22.38mA
2.9V      18.05mA    88.22mA    23.05mA
3.1V      23.1mA     330mA      24.47mA
3.2V      66.21mA    470mA      25.98mA
3.4V      320mA      760mA      47.61mA
3.5V      460mA      910mA      130mA
3.6V      620mA      1.06A      260mA
4V        1.25A      1.66A      870mA
5V        2.87A      3.21A      2.49A
[Pullup]
| voltage   I(typ)   I(min)   I(max)
-2.5V     11.45mA    7.74mA     14.22mA
2.9V      -36.59mA   -32.84mA   -46.42mA
3V        -37.4mA    -61.07mA   -47.35mA
3.1V      -39.12mA   -150mA     -48.24mA
3.3V      -70.02mA   -450mA     -51.02mA
3.4V      -170mA     -620mA     -57.38mA
3.5V      -320mA     -800mA     -72.59mA
3.6V      -490mA     -990mA     -140mA
3.8V      -870mA     -1.36A     -440mA
4V        -1.27A     -1.74A     -820mA
4.2V      -1.68A     -2.13A     -1.22A
5V        -3.34A     -3.69A     -2.88A
[GND_clamp]
| voltage   I(typ)   I(min)   I(max)
-2.5V     -3.34A     -3.3A      -3.3A
-1.2V     -670mA     -800mA     -620mA
-1.1V     -480mA     -620mA     -430mA
-1V       -310mA     -450mA     -260mA
-900mV    -150mA     -280mA     -110mA
-800mV    -41.81mA   -140mA     -27.69mA
-700mV    -7.62mA    -40.98mA   -8.11mA
-600mV    -1.38mA    -5.69mA    -1.55mA
-500mV    -120uA     -670uA     -110uA
2.5V      540pA      2.11uA     480pA
[POWER_clamp]
| voltage   I(typ)   I(min)   I(max)
-2.5V     2.86A      2.89A      2.8A
-1.3V     920mA      1.05A      860mA
-1.2V     760mA      900mA      700mA
-1.1V     610mA      750mA      550mA
-1V       450mA      610mA      400mA
-900mV    310mA      460mA      250mA
-800mV    170mA      320mA      120mA
-700mV    52.5mA     190mA      22.73mA
-600mV    4.56mA     79.5mA     2.44mA
-500mV    270uA      13.41mA    250uA
-400mV    16.38uA    820uA      14.45uA
0V        540pA      2.08nA     580pA
[Ramp]
| variable   typ   min   max
dV/dt_r   0.46/0.38n   0.37/0.44n   0.55/0.34n
dV/dt_f   0.18/0.17n   0.14/0.21n   0.25/0.17n
R_load = 50.00
[Rising Waveform]
R_fixture = 50.00
V_fixture = 0.000
| time   V(typ)   V(min)   V(max)
0s        160mV      140mV      170mV
1ns       160mV      140mV      220mV
1.2ns     160mV      140mV      510mV
1.4ns     260mV      140mV      770mV
1.6ns     540mV      140mV      960mV
1.8ns     750mV      240mV      1.03V
2ns       860mV      440mV      1.06V
2.4ns     910mV      690mV      1.07V
3ns       920mV      750mV      1.07V
10ns      920mV      750mV      1.07V
[Rising Waveform]
R_fixture = 50.00
V_fixture = 1.25
V_fixture_min = 1.21
V_fixture_max = 1.27
| time   V(typ)   V(min)   V(max)
0s        960mV      990mV      890mV
800ps     960mV      990mV      890mV
1ns       960mV      990mV      930mV
1.4ns     1.01V      990mV      1.31V
1.6ns     1.16V      990mV      1.51V
1.8ns     1.34V      1.03V      1.59V
2.2ns     1.5V       1.24V      1.64V
2.6ns     1.53V      1.38V      1.64V
3ns       1.53V      1.42V      1.64V
10ns      1.53V      1.42V      1.64V
[Falling Waveform]
R_fixture = 50.00
V_fixture = 0.000
| time   V(typ)   V(min)   V(max)
0s        920mV      750mV      1.07V
1.2ns     920mV      750mV      1.02V
1.4ns     910mV      750mV      870mV
1.6ns     840mV      750mV      590mV
1.8ns     670mV      740mV      360mV
2.2ns     300mV      620mV      200mV
2.4ns     230mV      470mV      180mV
2.8ns     170mV      230mV      170mV
3.4ns     160mV      150mV      170mV
10ns      160mV      140mV      170mV
[Falling Waveform]
R_fixture = 50.00
V_fixture = 1.25
V_fixture_min = 1.21
V_fixture_max = 1.27
| time   V(typ)   V(min)   V(max)
0s        1.53V      1.42V      1.64V
1ns       1.53V      1.42V      1.64V
1.2ns     1.54V      1.42V      1.54V
1.4ns     1.52V      1.42V      1.34V
1.8ns     1.24V      1.41V      1.05V
2ns       1.13V      1.34V      990mV
2.4ns     1.03V      1.15V      930mV
2.8ns     990mV      1.05V      910mV
3.6ns     970mV      1V         900mV
10ns      960mV      990mV      890mV
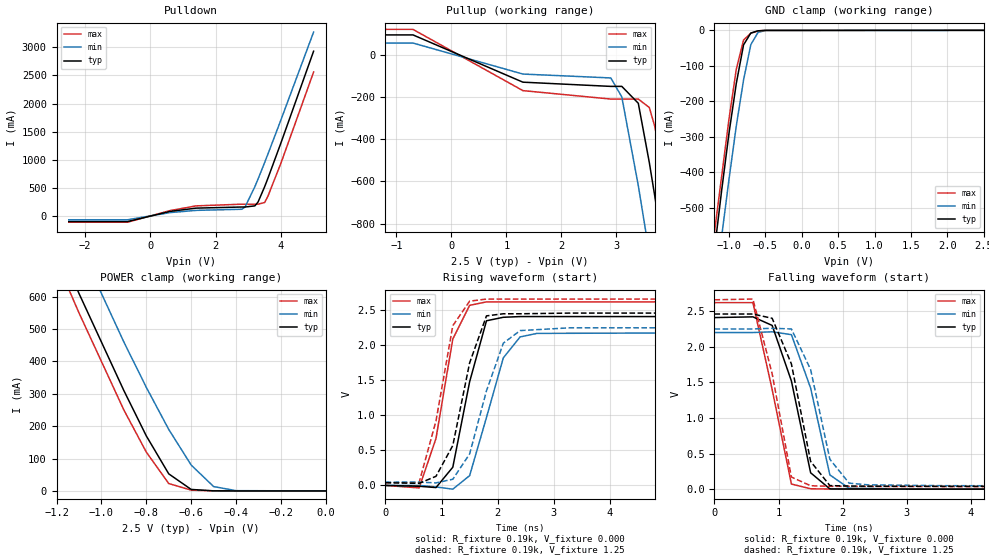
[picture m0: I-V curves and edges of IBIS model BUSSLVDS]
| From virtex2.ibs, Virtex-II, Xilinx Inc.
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|   Model BUSSLVDS
[Model]   BUSSLVDS
Model_type   I/O
Polarity   Non-Inverting
Enable   Active-Low
Vinh = 1.4v
Vinl = 1.0v
Vmeas =   1.20V
Cref =  0pF
Rref =   1.00M
Vref =  0.000V
C_comp   10.00pF   10.00pF   10.00pF
[Temperature Range]   25.00   100.00   0.000
[Voltage Range]   2.50V   2.30V   2.70V
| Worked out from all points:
|   slope of the pulldown table from 0 to 0.375 V, typ, clamps not added: 6.89 ohm
|   slope of the pullup table from 0 to 0.375 V, typ, clamps not added: 7.37 ohm
|   GND clamp passes 1 mA (typ) near -0.57 V on its own axis
|   POWER clamp passes 1 mA (typ) near -0.52 V on its own axis
|   rising waveform, R_fixture 0.19k, V_fixture 0.000: 20-80 % time 400ps typ, 470ps min, 366ps max; typ from 0 V to 2.41 V
|   rising waveform, R_fixture 0.19k, V_fixture 1.25: 20-80 % time 433ps typ, 490ps min, 391ps max; typ from 0.039 V to 2.46 V
|   falling waveform, R_fixture 0.19k, V_fixture 0.000: 20-80 % time 398ps typ, 377ps min, 369ps max; typ from 2.41 V to 0 V
|   falling waveform, R_fixture 0.19k, V_fixture 1.25: 20-80 % time 372ps typ, 352ps min, 366ps max; typ from 2.46 V to 0.039 V
[Pulldown]
| voltage   I(typ)   I(min)   I(max)
-2.5V     -99.13mA   -67.11mA   -110mA
-700mV    -99.13mA   -67.11mA   -110mA
600mV     81.47mA    60.63mA    95.8mA
1.4V      140mA      100mA      180mA
2.8V      160mA      120mA      210mA
2.9V      160mA      160mA      210mA
3.2V      180mA      520mA      210mA
3.3V      250mA      660mA      210mA
3.5V      520mA      950mA      240mA
3.6V      670mA      1.1A       350mA
4V        1.3A       1.71A      940mA
5V        2.93A      3.27A      2.56A
[Pullup]
| voltage   I(typ)   I(min)   I(max)
-2.5V     93.9mA     55.32mA    120mA
-700mV    93.9mA     55.32mA    120mA
1.3V      -130mA     -91.56mA   -170mA
2.9V      -150mA     -110mA     -210mA
3.1V      -150mA     -200mA     -210mA
3.4V      -230mA     -620mA     -210mA
3.6V      -510mA     -940mA     -250mA
3.7V      -670mA     -1.11A     -340mA
3.8V      -840mA     -1.27A     -480mA
4V        -1.17A     -1.61A     -810mA
4.2V      -1.52A     -1.95A     -1.15A
5V        -2.93A     -3.31A     -2.55A
[GND_clamp]
| voltage   I(typ)   I(min)   I(max)
-2.5V     -2.88A     -2.94A     -2.84A
-1.2V     -620mA     -740mA     -570mA
-1.1V     -450mA     -580mA     -410mA
-1V       -290mA     -420mA     -250mA
-900mV    -150mA     -270mA     -110mA
-800mV    -41mA      -140mA     -27.22mA
-700mV    -7.57mA    -40.19mA   -8.13mA
-600mV    -1.4mA     -5.59mA    -1.6mA
-500mV    -130uA     -660uA     -120uA
2.5V      400pA      2.1uA      350pA
[POWER_clamp]
| voltage   I(typ)   I(min)   I(max)
-2.5V     2.87A      2.91A      2.82A
-1.3V     930mA      1.05A      870mA
-1.2V     770mA      910mA      710mA
-1.1V     610mA      760mA      550mA
-900mV    310mA      460mA      250mA
-800mV    170mA      320mA      120mA
-700mV    52.75mA    190mA      22.81mA
-600mV    4.57mA     79.88mA    2.44mA
-500mV    270uA      13.45mA    250uA
-400mV    16.38uA    820uA      14.46uA
0V        400pA      1.8nA      430pA
[Ramp]
| variable   typ   min   max
dV/dt_r   1.45/0.34n   1.32/0.46n   1.57/0.26n
dV/dt_f   1.45/0.27n   1.32/0.38n   1.58/0.23n
R_load = 0.19k
[Rising Waveform]
R_fixture = 0.19k
V_fixture = 0.000
| time   V(typ)   V(min)   V(max)
0s        0V         0V         0V
600ps     -12.03mV   53.81uV    -35.61mV
900ps     -30.83mV   -21.73mV   670mV
1.2ns     260mV      -53.49mV   2.09V
1.5ns     1.48V      140mV      2.57V
1.8ns     2.35V      970mV      2.62V
2.1ns     2.4V       1.82V      2.62V
2.4ns     2.41V      2.12V      2.62V
2.7ns     2.41V      2.17V      2.62V
15ns      2.41V      2.2V       2.62V
[Rising Waveform]
R_fixture = 0.19k
V_fixture = 1.25
V_fixture_min = 1.15
V_fixture_max = 1.35
| time   V(typ)   V(min)   V(max)
0s        39mV       46.96mV    36.89mV
600ps     29.53mV    46.99mV    41.8mV
900ps     130mV      35.87mV    920mV
1.2ns     570mV      88.42mV    2.28V
1.5ns     1.75V      450mV      2.63V
1.8ns     2.42V      1.35V      2.66V
2.1ns     2.45V      2.03V      2.66V
2.4ns     2.45V      2.21V      2.66V
3.3ns     2.46V      2.25V      2.66V
15ns      2.46V      2.25V      2.66V
[Falling Waveform]
R_fixture = 0.19k
V_fixture = 0.000
| time   V(typ)   V(min)   V(max)
0s        2.41V      2.2V       2.62V
600ps     2.42V      2.2V       2.62V
900ps     2.3V       2.21V      1.4V
1.2ns     1.52V      2.17V      71.93mV
1.5ns     230mV      1.42V      5.54mV
1.8ns     4.09mV     200mV      1.83mV
2.1ns     2.07mV     12.45mV    940uV
3.6ns     120uV      550uV      29.85uV
15ns      0V         0V         -620nV
[Falling Waveform]
R_fixture = 0.19k
V_fixture = 1.25
V_fixture_min = 1.15
V_fixture_max = 1.35
| time   V(typ)   V(min)   V(max)
0s        2.46V      2.25V      2.66V
600ps     2.46V      2.25V      2.67V
900ps     2.4V       2.26V      1.62V
1.2ns     1.76V      2.25V      170mV
1.5ns     390mV      1.68V      48.11mV
1.8ns     50.15mV    420mV      40.2mV
2.1ns     44.27mV    84.68mV    38.48mV
2.4ns     41.88mV    60.37mV    37.68mV
3.6ns     39.28mV    48.82mV    36.94mV
15ns      39mV       46.96mV    36.89mV
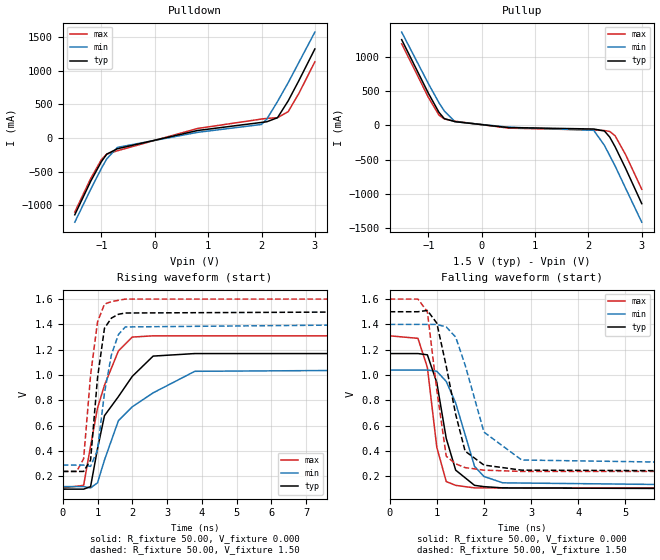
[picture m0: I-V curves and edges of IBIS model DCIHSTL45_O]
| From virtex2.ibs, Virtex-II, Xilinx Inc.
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|   Model DCIHSTL45_O
[Model]   DCIHSTL45_O
Model_type   Output
Polarity   Non-Inverting
Vmeas =   0.90V
Cref =  0pF
Rref =  50.00
Vref =   1.50V
C_comp   10.00pF   10.00pF   10.00pF
[Temperature Range]   25.00   100.00   0.000
[Voltage Range]   1.50V   1.40V   1.60V
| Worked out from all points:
|   slope of the pulldown table from 0 to 0.225 V, typ, clamps not added: 4.98 ohm
|   slope of the pullup table from 0 to 0.225 V, typ, clamps not added: 13 ohm
|   rising waveform, R_fixture 50.00, V_fixture 0.000: 20-80 % time 995ps typ, 1.41ns min, 698ps max; typ from 0.1 V to 1.17 V
|   rising waveform, R_fixture 50.00, V_fixture 1.50: 20-80 % time 288ps typ, 377ps min, 304ps max; typ from 0.24 V to 1.5 V
|   falling waveform, R_fixture 50.00, V_fixture 0.000: 20-80 % time 363ps typ, 468ps min, 268ps max; typ from 1.17 V to 0.1 V
|   falling waveform, R_fixture 50.00, V_fixture 1.50: 20-80 % time 441ps typ, 552ps min, 286ps max; typ from 1.5 V to 0.24 V
[Pulldown]
| voltage   I(typ)   I(min)   I(max)
-1.5V     -1.14A     -1.25A     -1.1A
-1.2V     -640mA     -760mA     -600mA
-1V       -350mA     -450mA     -320mA
-900mV    -240mA     -310mA     -240mA
-700mV    -160mA     -140mA     -190mA
800mV     110mA      82.53mA    140mA
2V        230mA      200mA      280mA
2.1V      240mA      280mA      290mA
2.3V      300mA      540mA      300mA
2.5V      550mA      820mA      390mA
2.7V      850mA      1.12A      660mA
3V        1.32A      1.57A      1.13A
[Pullup]
| voltage   I(typ)   I(min)   I(max)
-1.5V     1.25A      1.36A      1.19A
-1V       470mA      610mA      410mA
-800mV    190mA      330mA      150mA
-700mV    98.52mA    210mA      93.99mA
-500mV    54.91mA    53.99mA    61.6mA
500mV     -31.11mA   -25.62mA   -39.31mA
2.1V      -52.14mA   -71.44mA   -67.3mA
2.3V      -80.39mA   -290mA     -74.31mA
2.4V      -170mA     -440mA     -87.92mA
2.5V      -310mA     -590mA     -150mA
2.7V      -630mA     -920mA     -430mA
3V        -1.14A     -1.41A     -930mA
[Ramp]
| variable   typ   min   max
dV/dt_r   0.64/0.95n   0.55/1.35n   0.72/0.62n
dV/dt_f   0.75/0.34n   0.67/0.53n   0.82/0.24n
R_load = 50.00
[Rising Waveform]
R_fixture = 50.00
V_fixture = 0.000
| time   V(typ)   V(min)   V(max)
0s        100mV      120mV      110mV
600ps     100mV      120mV      130mV
800ps     120mV      110mV      440mV
1ns       420mV      150mV      740mV
1.2ns     680mV      330mV      920mV
1.6ns     830mV      640mV      1.19V
2ns       990mV      750mV      1.3V
2.6ns     1.15V      860mV      1.31V
3.8ns     1.17V      1.03V      1.31V
10ns      1.17V      1.04V      1.31V
[Rising Waveform]
R_fixture = 50.00
V_fixture = 1.50
V_fixture_min = 1.40
V_fixture_max = 1.60
| time   V(typ)   V(min)   V(max)
0s        240mV      290mV      240mV
400ps     240mV      290mV      240mV
600ps     240mV      290mV      340mV
800ps     330mV      280mV      1V
1ns       980mV      410mV      1.42V
1.2ns     1.37V      860mV      1.56V
1.4ns     1.45V      1.16V      1.58V
1.6ns     1.48V      1.32V      1.59V
1.8ns     1.49V      1.38V      1.6V
10ns      1.5V       1.4V       1.6V
[Falling Waveform]
R_fixture = 50.00
V_fixture = 0.000
| time   V(typ)   V(min)   V(max)
0s        1.17V      1.04V      1.31V
600ps     1.17V      1.04V      1.29V
800ps     1.16V      1.04V      1.06V
1ns       940mV      1.03V      430mV
1.2ns     500mV      950mV      160mV
1.4ns     250mV      780mV      130mV
1.8ns     130mV      280mV      110mV
2ns       120mV      200mV      110mV
2.4ns     110mV      150mV      110mV
10ns      100mV      120mV      110mV
[Falling Waveform]
R_fixture = 50.00
V_fixture = 1.50
V_fixture_min = 1.40
V_fixture_max = 1.60
| time   V(typ)   V(min)   V(max)
0s        1.5V       1.4V       1.6V
600ps     1.5V       1.4V       1.6V
800ps     1.51V      1.4V       1.5V
1ns       1.41V      1.4V       880mV
1.2ns     1.07V      1.38V      360mV
1.4ns     690mV      1.3V       300mV
1.6ns     400mV      1.08V      270mV
2ns       290mV      550mV      250mV
2.8ns     250mV      330mV      240mV
10ns      240mV      290mV      240mV
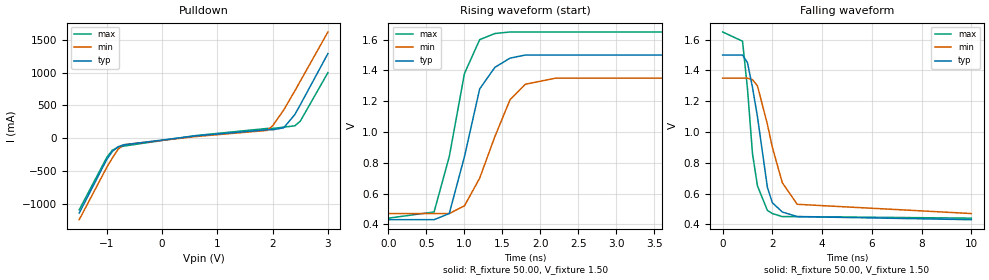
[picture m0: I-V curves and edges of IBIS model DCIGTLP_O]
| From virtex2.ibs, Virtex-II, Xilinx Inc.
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|   Model DCIGTLP_O
[Model]   DCIGTLP_O
Model_type   Open_drain
Polarity   Non-Inverting
Vmeas =   1.00V
Cref =  0pF
Rref =  50.00
Vref =   1.50V
C_comp   10.00pF   10.00pF   10.00pF
[Temperature Range]   25.00   100.00   0.000
[Voltage Range]   1.50V   1.35V   1.65V
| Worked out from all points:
|   slope of the pulldown table from 0 to 0.225 V, typ, clamps not added: 8.95 ohm
|   rising waveform, R_fixture 50.00, V_fixture 1.50: 20-80 % time 315ps typ, 430ps min, 313ps max; typ from 0.43 V to 1.5 V
|   falling waveform, R_fixture 50.00, V_fixture 1.50: 20-80 % time 592ps typ, 846ps min, 452ps max; typ from 1.5 V to 0.43 V
[Pulldown]
| voltage   I(typ)   I(min)   I(max)
-1.5V     -1.14A     -1.24A     -1.09A
-1V       -320mA     -440mA     -290mA
-900mV    -200mA     -300mA     -180mA
-800mV    -130mA     -170mA     -140mA
-700mV    -100mA     -98.42mA   -120mA
600mV     36.17mA    26.11mA    40.93mA
1.9V      130mA      120mA      150mA
2V        130mA      190mA      150mA
2.2V      160mA      430mA      170mA
2.4V      360mA      720mA      190mA
2.5V      510mA      870mA      260mA
3V        1.29A      1.62A      1A
[Ramp]
| variable   typ   min   max
dV/dt_r   0.64/0.28n   0.53/0.33n   0.72/0.25n
dV/dt_f   0.64/0.53n   0.53/0.82n   0.72/0.39n
R_load = 50.00
[Rising Waveform]
R_fixture = 50.00
V_fixture = 1.50
V_fixture_min = 1.35
V_fixture_max = 1.65
| time   V(typ)   V(min)   V(max)
0s        430mV      470mV      440mV
600ps     430mV      470mV      480mV
800ps     470mV      470mV      840mV
1ns       840mV      520mV      1.38V
1.2ns     1.28V      700mV      1.6V
1.4ns     1.42V      970mV      1.64V
1.6ns     1.48V      1.21V      1.65V
1.8ns     1.5V       1.31V      1.65V
2.2ns     1.5V       1.35V      1.65V
10ns      1.5V       1.35V      1.65V
[Falling Waveform]
R_fixture = 50.00
V_fixture = 1.50
V_fixture_min = 1.35
V_fixture_max = 1.65
| time   V(typ)   V(min)   V(max)
0s        1.5V       1.35V      1.65V
800ps     1.5V       1.35V      1.59V
1ns       1.45V      1.35V      1.28V
1.2ns     1.29V      1.34V      860mV
1.4ns     1.1V       1.3V       650mV
1.8ns     640mV      1.05V      490mV
2ns       540mV      900mV      470mV
2.4ns     480mV      670mV      450mV
3ns       450mV      530mV      450mV
10ns      430mV      470mV      440mV
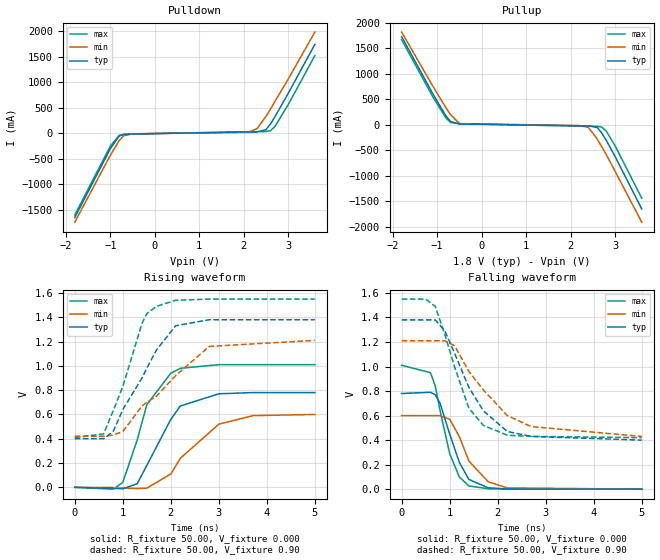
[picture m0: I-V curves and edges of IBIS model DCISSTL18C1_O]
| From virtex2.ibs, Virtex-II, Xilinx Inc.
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|   Model DCISSTL18C1_O
[Model]   DCISSTL18C1_O
Model_type   Output
Polarity   Non-Inverting
Vmeas =   0.90V
Cref =  0pF
Rref =  50.00
Vref =   0.90V
C_comp   10.00pF   10.00pF   10.00pF
[Temperature Range]   25.00   100.00   0.000
[Voltage Range]   1.80V   1.70V   1.90V
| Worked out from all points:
|   slope of the pulldown table from 0 to 0.27 V, typ, clamps not added: 38.5 ohm
|   slope of the pullup table from 0 to 0.27 V, typ, clamps not added: 40.5 ohm
|   rising waveform, R_fixture 50.00, V_fixture 0.000: 20-80 % time 621ps typ, 783ps min, 525ps max; typ from 0 V to 0.78 V
|   rising waveform, R_fixture 50.00, V_fixture 0.90: 20-80 % time 826ps typ, 1.21ns min, 570ps max; typ from 0.4 V to 1.38 V
|   falling waveform, R_fixture 50.00, V_fixture 0.000: 20-80 % time 411ps typ, 487ps min, 364ps max; typ from 0.78 V to 0 V
|   falling waveform, R_fixture 50.00, V_fixture 0.90: 20-80 % time 770ps typ, 977ps min, 577ps max; typ from 1.38 V to 0.4 V
[Pulldown]
| voltage   I(typ)   I(min)   I(max)
-1.8V     -1.65A     -1.74A     -1.6A
-1V       -300mA     -430mA     -250mA
-800mV    -52.51mA   -140mA     -41.29mA
-700mV    -22.54mA   -48.85mA   -24.09mA
-500mV    -13.21mA   -10.35mA   -14.88mA
2.1V      25.64mA    18.75mA    31.4mA
2.3V      26.16mA    91.27mA    31.56mA
2.5V      70.68mA    330mA      34.48mA
2.6V      180mA      470mA      50.15mA
2.7V      320mA      620mA      130mA
3V        780mA      1.06A      560mA
3.6V      1.74A      1.98A      1.52A
[Pullup]
| voltage   I(typ)   I(min)   I(max)
-1.8V     1.73A      1.82A      1.67A
-1.1V     610mA      760mA      550mA
-800mV    170mA      330mA      130mA
-700mV    66.08mA    200mA      45.98mA
-500mV    17.35mA    24.58mA    20.89mA
2.2V      -18.4mA    -14.18mA   -25.41mA
2.4V      -19.27mA   -50.36mA   -25.79mA
2.6V      -52.96mA   -280mA     -30.12mA
2.7V      -160mA     -430mA     -45.41mA
2.8V      -300mA     -580mA     -120mA
3V        -620mA     -910mA     -410mA
3.6V      -1.65A     -1.91A     -1.44A
[Ramp]
| variable   typ   min   max
dV/dt_r   0.47/0.63n   0.36/0.82n   0.60/0.52n
dV/dt_f   0.55/1.03n   0.41/1.42n   0.63/0.80n
R_load = 50.00
[Rising Waveform]
R_fixture = 50.00
V_fixture = 0.000
| time   V(typ)   V(min)   V(max)
0s        0V         0V         0V
800ps     -8.77mV    -1.86mV    -15.08mV
1ns       -11.86mV   -5.96mV    40.62mV
1.3ns     29.76mV    -9.58mV    390mV
1.5ns     180mV      -6.53mV    680mV
2ns       560mV      110mV      940mV
2.2ns     670mV      240mV      980mV
3ns       770mV      520mV      1.01V
3.7ns     780mV      590mV      1.01V
5ns       780mV      600mV      1.01V
[Rising Waveform]
R_fixture = 50.00
V_fixture = 0.90
V_fixture_min = 0.79
V_fixture_max = 1.01
| time   V(typ)   V(min)   V(max)
0s        400mV      420mV      410mV
600ps     400mV      420mV      440mV
800ps     460mV      430mV      630mV
1ns       640mV      460mV      830mV
1.4ns     900mV      670mV      1.35V
1.5ns     980mV      700mV      1.43V
1.7ns     1.13V      750mV      1.49V
2.1ns     1.33V      920mV      1.54V
2.8ns     1.38V      1.16V      1.55V
5ns       1.38V      1.21V      1.55V
[Falling Waveform]
R_fixture = 50.00
V_fixture = 0.000
| time   V(typ)   V(min)   V(max)
0s        780mV      600mV      1.01V
600ps     790mV      600mV      950mV
700ps     770mV      600mV      840mV
800ps     700mV      600mV      640mV
1ns       450mV      570mV      290mV
1.2ns     220mV      430mV      100mV
1.4ns     78.98mV    230mV      26.26mV
1.8ns     11.28mV    60.73mV    3.23mV
2.2ns     1.78mV     10.19mV    890uV
5ns       53.16uV    170uV      16.98uV
[Falling Waveform]
R_fixture = 50.00
V_fixture = 0.90
V_fixture_min = 0.79
V_fixture_max = 1.01
| time   V(typ)   V(min)   V(max)
0s        1.38V      1.21V      1.55V
500ps     1.38V      1.21V      1.55V
700ps     1.38V      1.21V      1.49V
900ps     1.29V      1.21V      1.26V
1.1ns     1.11V      1.17V      1V
1.4ns     830mV      960mV      660mV
1.7ns     640mV      810mV      520mV
2.2ns     470mV      600mV      440mV
2.7ns     430mV      510mV      430mV
5ns       400mV      430mV      420mV
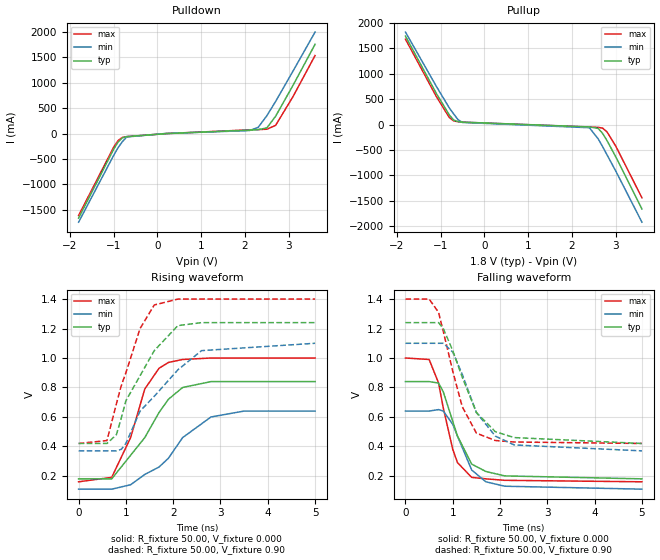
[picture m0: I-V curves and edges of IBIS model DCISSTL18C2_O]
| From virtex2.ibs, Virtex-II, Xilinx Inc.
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|   Model DCISSTL18C2_O
[Model]   DCISSTL18C2_O
Model_type   Output
Polarity   Non-Inverting
Vmeas =   0.90V
Cref =  0pF
Rref =  50.00
Vref =   0.90V
C_comp   10.00pF   10.00pF   10.00pF
[Temperature Range]   25.00   100.00   0.000
[Voltage Range]   1.80V   1.70V   1.90V
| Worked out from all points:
|   slope of the pulldown table from 0 to 0.27 V, typ, clamps not added: 16.3 ohm
|   slope of the pullup table from 0 to 0.27 V, typ, clamps not added: 21.1 ohm
|   rising waveform, R_fixture 50.00, V_fixture 0.000: 20-80 % time 840ps typ, 1.05ns min, 557ps max; typ from 0.18 V to 0.84 V
|   rising waveform, R_fixture 50.00, V_fixture 0.90: 20-80 % time 757ps typ, 1.04ns min, 551ps max; typ from 0.42 V to 1.24 V
|   falling waveform, R_fixture 50.00, V_fixture 0.000: 20-80 % time 474ps typ, 440ps min, 360ps max; typ from 0.84 V to 0.18 V
|   falling waveform, R_fixture 50.00, V_fixture 0.90: 20-80 % time 648ps typ, 640ps min, 486ps max; typ from 1.24 V to 0.42 V
[Pulldown]
| voltage   I(typ)   I(min)   I(max)
-1.8V     -1.66A     -1.74A     -1.61A
-1V       -310mA     -430mA     -270mA
-900mV    -170mA     -280mA     -140mA
-800mV    -84.49mA   -160mA     -76.86mA
-700mV    -60.69mA   -67.42mA   -60.95mA
200mV     -2.75mA    1.62mA     -880uA
2.1V      67.56mA    57.49mA    71.89mA
2.3V      74.57mA    120mA      77.18mA
2.5V      110mA      350mA      84.51mA
2.7V      340mA      630mA      160mA
3.1V      950mA      1.23A      730mA
3.6V      1.75A      1.99A      1.53A
[Pullup]
| voltage   I(typ)   I(min)   I(max)
-1.8V     1.74A      1.82A      1.68A
-1.1V     620mA      760mA      560mA
-800mV    190mA      330mA      140mA
-700mV    90.6mA     210mA      73.21mA
-600mV    57.9mA     98.42mA    56.69mA
-500mV    48.54mA    41.82mA    47.96mA
2.4V      -45.83mA   -61.41mA   -48.24mA
2.6V      -75.13mA   -280mA     -54.71mA
2.7V      -170mA     -430mA     -68.55mA
2.8V      -310mA     -590mA     -140mA
3V        -630mA     -910mA     -420mA
3.6V      -1.66A     -1.92A     -1.44A
[Ramp]
| variable   typ   min   max
dV/dt_r   0.39/0.84n   0.32/1.02n   0.50/0.57n
dV/dt_f   0.52/0.79n   0.48/0.82n   0.61/0.59n
R_load = 50.00
[Rising Waveform]
R_fixture = 50.00
V_fixture = 0.000
| time   V(typ)   V(min)   V(max)
0s        180mV      110mV      160mV
700ps     180mV      110mV      190mV
1.1ns     340mV      140mV      460mV
1.4ns     460mV      210mV      790mV
1.7ns     630mV      260mV      930mV
1.9ns     720mV      320mV      970mV
2.2ns     800mV      460mV      990mV
2.8ns     840mV      600mV      1V
3.5ns     840mV      640mV      1V
5ns       840mV      640mV      1V
[Rising Waveform]
R_fixture = 50.00
V_fixture = 0.90
V_fixture_min = 0.79
V_fixture_max = 1.01
| time   V(typ)   V(min)   V(max)
0s        420mV      370mV      420mV
600ps     420mV      370mV      440mV
800ps     480mV      370mV      690mV
900ps     590mV      380mV      810mV
1ns       710mV      420mV      900mV
1.3ns     880mV      640mV      1.2V
1.6ns     1.05V      740mV      1.36V
2.1ns     1.22V      920mV      1.4V
2.6ns     1.24V      1.05V      1.4V
5ns       1.24V      1.1V       1.4V
[Falling Waveform]
R_fixture = 50.00
V_fixture = 0.000
| time   V(typ)   V(min)   V(max)
0s        840mV      640mV      1V
500ps     840mV      640mV      990mV
700ps     830mV      650mV      830mV
800ps     770mV      640mV      660mV
1ns       570mV      550mV      380mV
1.1ns     470mV      470mV      290mV
1.4ns     280mV      240mV      190mV
1.7ns     230mV      160mV      180mV
2.1ns     200mV      130mV      170mV
5ns       180mV      110mV      160mV
[Falling Waveform]
R_fixture = 50.00
V_fixture = 0.90
V_fixture_min = 0.79
V_fixture_max = 1.01
| time   V(typ)   V(min)   V(max)
0s        1.24V      1.1V       1.4V
500ps     1.24V      1.1V       1.4V
700ps     1.24V      1.1V       1.31V
800ps     1.2V       1.1V       1.18V
1ns       1.05V      1.04V      910mV
1.2ns     870mV      890mV      670mV
1.5ns     630mV      630mV      490mV
1.9ns     500mV      470mV      440mV
2.3ns     460mV      410mV      430mV
5ns       420mV      370mV      420mV
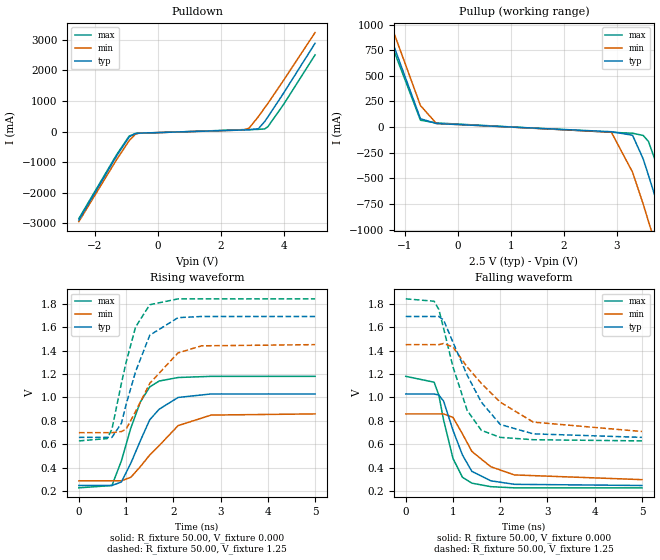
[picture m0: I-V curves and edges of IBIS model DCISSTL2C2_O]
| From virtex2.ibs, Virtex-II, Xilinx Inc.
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|   Model DCISSTL2C2_O
[Model]   DCISSTL2C2_O
Model_type   Output
Polarity   Non-Inverting
Vmeas =   1.25V
Cref =  0pF
Rref =  50.00
Vref =   1.25V
C_comp   10.00pF   10.00pF   10.00pF
[Temperature Range]   25.00   100.00   0.000
[Voltage Range]   2.50V   2.30V   2.70V
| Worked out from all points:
|   slope of the pulldown table from 0 to 0.375 V, typ, clamps not added: 20.5 ohm
|   slope of the pullup table from 0 to 0.375 V, typ, clamps not added: 27.3 ohm
|   rising waveform, R_fixture 50.00, V_fixture 0.000: 20-80 % time 573ps typ, 777ps min, 468ps max; typ from 0.25 V to 1.03 V
|   rising waveform, R_fixture 50.00, V_fixture 1.25: 20-80 % time 489ps typ, 708ps min, 424ps max; typ from 0.66 V to 1.69 V
|   falling waveform, R_fixture 50.00, V_fixture 0.000: 20-80 % time 469ps typ, 666ps min, 346ps max; typ from 1.03 V to 0.25 V
|   falling waveform, R_fixture 50.00, V_fixture 1.25: 20-80 % time 781ps typ, 1.12ns min, 525ps max; typ from 1.69 V to 0.66 V
[Pulldown]
| voltage   I(typ)   I(min)   I(max)
-2.5V     -2.89A     -2.94A     -2.84A
-1.3V     -790mA     -910mA     -750mA
-900mV    -170mA     -290mA     -140mA
-700mV    -57.29mA   -76.27mA   -63.43mA
-600mV    -48.61mA   -49.62mA   -53.77mA
2.7V      54.79mA    52.92mA    65.13mA
2.9V      59.2mA     110mA      69mA
3.2V      96.37mA    490mA      75.12mA
3.4V      330mA      780mA      89.38mA
3.5V      480mA      920mA      160mA
4V        1.26A      1.68A      890mA
5V        2.89A      3.24A      2.51A
[Pullup]
| voltage   I(typ)   I(min)   I(max)
-2.5V     2.88A      2.92A      2.82A
-1.3V     930mA      1.06A      880mA
-700mV    81.38mA    210mA      66.75mA
-400mV    34.28mA    35.53mA    40.35mA
2.9V      -45.25mA   -49.52mA   -50.79mA
3.3V      -79.62mA   -440mA     -60.02mA
3.5V      -310mA     -750mA     -81.63mA
3.6V      -470mA     -920mA     -140mA
3.8V      -800mA     -1.25A     -430mA
4V        -1.14A     -1.58A     -760mA
4.2V      -1.49A     -1.92A     -1.1A
5V        -2.89A     -3.29A     -2.5A
[Ramp]
| variable   typ   min   max
dV/dt_r   0.47/0.58n   0.34/0.80n   0.57/0.46n
dV/dt_f   0.63/1.02n   0.43/1.43n   0.76/0.71n
R_load = 50.00
[Rising Waveform]
R_fixture = 50.00
V_fixture = 0.000
| time   V(typ)   V(min)   V(max)
0s        250mV      290mV      230mV
700ps     250mV      290mV      250mV
900ps     280mV      290mV      460mV
1.1ns     440mV      320mV      740mV
1.3ns     630mV      410mV      960mV
1.5ns     810mV      510mV      1.09V
1.7ns     900mV      590mV      1.14V
2.1ns     1V         760mV      1.17V
2.8ns     1.03V      850mV      1.18V
5ns       1.03V      860mV      1.18V
[Rising Waveform]
R_fixture = 50.00
V_fixture = 1.25
V_fixture_min = 1.11
V_fixture_max = 1.39
| time   V(typ)   V(min)   V(max)
0s        660mV      700mV      630mV
600ps     660mV      700mV      650mV
700ps     660mV      700mV      730mV
900ps     780mV      710mV      1.12V
1ns       940mV      730mV      1.3V
1.2ns     1.22V      880mV      1.6V
1.5ns     1.53V      1.12V      1.79V
2.1ns     1.68V      1.38V      1.84V
2.6ns     1.69V      1.44V      1.84V
5ns       1.69V      1.45V      1.84V
[Falling Waveform]
R_fixture = 50.00
V_fixture = 0.000
| time   V(typ)   V(min)   V(max)
0s        1.03V      860mV      1.18V
600ps     1.03V      860mV      1.13V
700ps     1.02V      860mV      1.02V
800ps     970mV      860mV      810mV
1ns       720mV      830mV      480mV
1.2ns     510mV      690mV      320mV
1.4ns     370mV      540mV      270mV
1.8ns     290mV      410mV      240mV
2.3ns     260mV      340mV      230mV
5ns       250mV      300mV      230mV
[Falling Waveform]
R_fixture = 50.00
V_fixture = 1.25
V_fixture_min = 1.11
V_fixture_max = 1.39
| time   V(typ)   V(min)   V(max)
0s        1.69V      1.45V      1.84V
600ps     1.69V      1.45V      1.82V
700ps     1.69V      1.45V      1.75V
800ps     1.66V      1.46V      1.59V
1ns       1.47V      1.43V      1.26V
1.3ns     1.19V      1.26V      890mV
1.6ns     960mV      1.12V      720mV
2ns       770mV      960mV      660mV
2.7ns     690mV      790mV      640mV
5ns       660mV      710mV      630mV
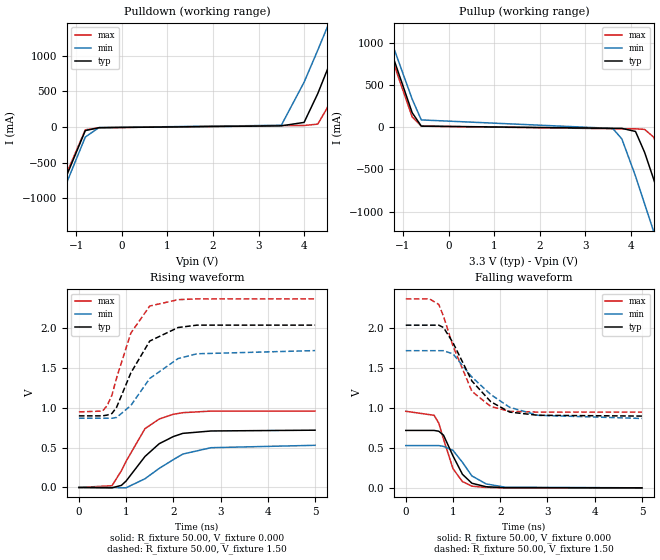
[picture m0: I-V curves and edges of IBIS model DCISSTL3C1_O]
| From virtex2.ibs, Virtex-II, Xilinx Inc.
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|   Model DCISSTL3C1_O
[Model]   DCISSTL3C1_O
Model_type   Output
Polarity   Non-Inverting
Vmeas =   1.50V
Cref =  0pF
Rref =  50.00
Vref =   1.50V
C_comp   10.00pF   10.00pF   10.00pF
[Temperature Range]   25.00   100.00   0.000
[Voltage Range]   3.30V   3.00V   3.60V
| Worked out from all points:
|   slope of the pulldown table from 0 to 0.495 V, typ, clamps not added: 64.8 ohm
|   slope of the pullup table from 0 to 0.495 V, typ, clamps not added: 95.5 ohm
|   rising waveform, R_fixture 50.00, V_fixture 0.000: 20-80 % time 674ps typ, 848ps min, 572ps max; typ from 0 V to 0.72 V
|   rising waveform, R_fixture 50.00, V_fixture 1.50: 20-80 % time 576ps typ, 789ps min, 495ps max; typ from 0.9 V to 2.04 V
|   falling waveform, R_fixture 50.00, V_fixture 0.000: 20-80 % time 367ps typ, 411ps min, 327ps max; typ from 0.72 V to 0 V
|   falling waveform, R_fixture 50.00, V_fixture 1.50: 20-80 % time 698ps typ, 888ps min, 548ps max; typ from 2.04 V to 0.9 V
[Pulldown]
| voltage   I(typ)   I(min)   I(max)
-3.3V     -4.3A      -4.31A     -4.26A
-1.7V     -1.47A     -1.57A     -1.43A
-1.5V     -1.13A     -1.24A     -1.08A
-800mV    -49.5mA    -140mA     -39.11mA
-500mV    -8.57mA    -7.12mA    -9.81mA
3.5V      17.22mA    24.99mA    22.01mA
4V        65.53mA    630mA      22.12mA
4.3V      470mA      1.08A      41.45mA
4.5V      790mA      1.39A      260mA
4.9V      1.43A      2.01A      890mA
5.3V      2.09A      2.64A      1.54A
6.6V      4.26A      4.7A       3.7A
[Pullup]
| voltage   I(typ)   I(min)   I(max)
-3.3V     4.25A      4.22A      4.2A
-1.5V     1.27A      1.38A      1.21A
-800mV    170mA      330mA      120mA
-600mV    11.52mA    84.58mA    10.81mA
3.6V      -15.07mA   -16.2mA    -20.1mA
3.8V      -15.26mA   -140mA     -20.23mA
4.1V      -52.21mA   -580mA     -20.5mA
4.3V      -300mA     -910mA     -27.9mA
4.5V      -620mA     -1.24A     -120mA
4.9V      -1.3A      -1.91A     -750mA
5.1V      -1.65A     -2.25A     -1.09A
6.6V      -4.31A     -4.84A     -3.73A
[Ramp]
| variable   typ   min   max
dV/dt_r   0.43/0.68n   0.32/0.86n   0.58/0.59n
dV/dt_f   0.51/0.97n   0.36/1.19n   0.65/0.84n
R_load = 50.00
[Rising Waveform]
R_fixture = 50.00
V_fixture = 0.000
| time   V(typ)   V(min)   V(max)
0s        0V         0V         0V
700ps     -4.56mV    -480uV     21.78mV
900ps     26.65mV    -3.9mV     210mV
1ns       81.48mV    -3.64mV    330mV
1.4ns     390mV      110mV      740mV
1.7ns     550mV      240mV      860mV
2ns       640mV      350mV      920mV
2.2ns     680mV      420mV      940mV
2.8ns     710mV      500mV      960mV
5ns       720mV      530mV      960mV
[Rising Waveform]
R_fixture = 50.00
V_fixture = 1.50
V_fixture_min = 1.30
V_fixture_max = 1.70
| time   V(typ)   V(min)   V(max)
0s        900mV      870mV      950mV
500ps     900mV      870mV      960mV
600ps     910mV      870mV      1.03V
700ps     930mV      870mV      1.16V
800ps     1.01V      880mV      1.38V
1.1ns     1.44V      1.03V      1.94V
1.5ns     1.84V      1.37V      2.28V
2.1ns     2.01V      1.62V      2.36V
2.5ns     2.04V      1.68V      2.37V
5ns       2.04V      1.72V      2.37V
[Falling Waveform]
R_fixture = 50.00
V_fixture = 0.000
| time   V(typ)   V(min)   V(max)
0s        720mV      530mV      960mV
600ps     720mV      530mV      910mV
700ps     710mV      530mV      810mV
800ps     660mV      520mV      610mV
1ns       400mV      470mV      240mV
1.2ns     170mV      320mV      78.41mV
1.4ns     57.63mV    150mV      21.16mV
1.7ns     13.68mV    49.46mV    4.28mV
2.1ns     1.88mV     8.53mV     560uV
5ns       -7.77uV    8.04uV     -8.98uV
[Falling Waveform]
R_fixture = 50.00
V_fixture = 1.50
V_fixture_min = 1.30
V_fixture_max = 1.70
| time   V(typ)   V(min)   V(max)
0s        2.04V      1.72V      2.37V
500ps     2.04V      1.72V      2.37V
700ps     2.04V      1.72V      2.3V
800ps     2.01V      1.72V      2.15V
1ns       1.82V      1.68V      1.78V
1.4ns     1.34V      1.39V      1.21V
1.8ns     1.08V      1.17V      1.02V
2.2ns     950mV      1.01V      960mV
2.8ns     910mV      910mV      950mV
5ns       900mV      870mV      950mV
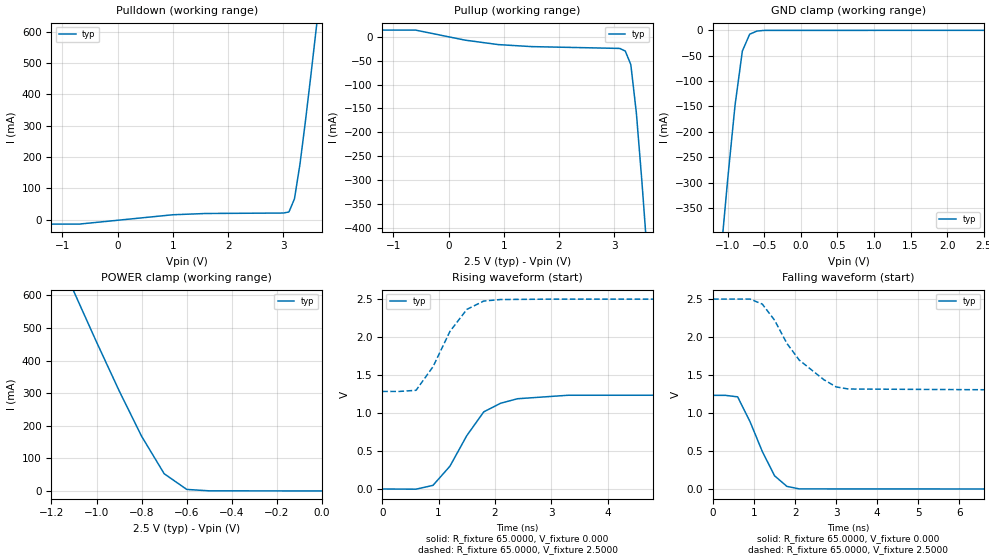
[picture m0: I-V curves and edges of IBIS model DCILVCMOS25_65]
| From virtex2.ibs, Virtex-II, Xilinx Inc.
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|   Model DCILVCMOS25_65
[Model]   DCILVCMOS25_65
Model_type   I/O
Polarity   Non-Inverting
Enable   Active-Low
Vinh = 1.7V
Vinl = 0.7V
Vmeas =   1.25V
Cref =  0pF
Rref =   1.00M
Vref =  0.000V
C_comp   7.0000pF   NA   NA
[Temperature Range]   25.0000   NA   NA
[Voltage Range]   2.5000V   NA   NA
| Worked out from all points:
|   slope of the pulldown table from 0 to 0.375 V, typ, clamps not added: 49.4 ohm
|   slope of the pullup table from 0 to 0.375 V, typ, clamps not added: 46.8 ohm
|   GND clamp passes 1 mA (typ) near -0.57 V on its own axis
|   POWER clamp passes 1 mA (typ) near -0.52 V on its own axis
|   rising waveform, R_fixture 65.0000, V_fixture 0.000: 20-80 % time 636ps typ, NA min, NA max; typ from 0 V to 1.23 V
|   rising waveform, R_fixture 65.0000, V_fixture 2.5000: 20-80 % time 569ps typ, NA min, NA max; typ from 1.28 V to 2.5 V
|   falling waveform, R_fixture 65.0000, V_fixture 0.000: 20-80 % time 624ps typ, NA min, NA max; typ from 1.23 V to 0 V
|   falling waveform, R_fixture 65.0000, V_fixture 2.5000: 20-80 % time 1.01ns typ, NA min, NA max; typ from 2.5 V to 1.28 V
[Pulldown]
| voltage   I(typ)   I(min)   I(max)
-2.5V     -13.61mA   NA         NA
-700mV    -13.61mA   NA         NA
1V        16.26mA    NA         NA
1.6V      20.28mA    NA         NA
3V        21.72mA    NA         NA
3.1V      25.14mA    NA         NA
3.2V      66.94mA    NA         NA
3.3V      178.1mA    NA         NA
3.4V      316.8mA    NA         NA
3.5V      465.4mA    NA         NA
3.6V      619.1mA    NA         NA
5V        2.882A     NA         NA
[Pullup]
| voltage   I(typ)   I(min)   I(max)
-2.5V     14.58mA    NA         NA
-600mV    14.58mA    NA         NA
300mV     -6.573mA   NA         NA
900mV     -15.91mA   NA         NA
1.5V      -20.13mA   NA         NA
3.1V      -23.96mA   NA         NA
3.2V      -29.52mA   NA         NA
3.3V      -57.95mA   NA         NA
3.4V      -159mA     NA         NA
3.5V      -302.3mA   NA         NA
3.6V      -460.3mA   NA         NA
5V        -2.888A    NA         NA
[GND_clamp]
| voltage   I(typ)   I(min)   I(max)
-2.5V     -2.881A    NA         NA
-1.1V     -452.1mA   NA         NA
-1V       -293.4mA   NA         NA
-900mV    -148.1mA   NA         NA
-800mV    -41.04mA   NA         NA
-700mV    -7.632mA   NA         NA
-600mV    -1.432mA   NA         NA
-500mV    -131.2uA   NA         NA
2.5V      397.5nA    NA         NA
[POWER_clamp]
| voltage   I(typ)   I(min)   I(max)
-2.5V     2.874A     NA         NA
-1.1V     610.9mA    NA         NA
-1V       456.9mA    NA         NA
-900mV    307.7mA    NA         NA
-800mV    167.5mA    NA         NA
-700mV    52.78mA    NA         NA
-600mV    4.607mA    NA         NA
-500mV    279.3uA    NA         NA
0V        397.5nA    NA         NA
[Ramp]
| variable   typ   min   max
dV/dt_r   0.7404/0.6606n   NA   NA
dV/dt_f   0.7296/1.0800n   NA   NA
R_load = 65.0000
[Rising Waveform]
R_fixture = 65.0000
V_fixture = 0.000
| time   V(typ)   V(min)   V(max)
0s        14.09uV    NA         NA
600ps     -2.329mV   NA         NA
900ps     47.87mV    NA         NA
1.2ns     299.6mV    NA         NA
1.5ns     703mV      NA         NA
1.8ns     1.015V     NA         NA
2.1ns     1.129V     NA         NA
2.4ns     1.188V     NA         NA
3.3ns     1.234V     NA         NA
15ns      1.234V     NA         NA
[Rising Waveform]
R_fixture = 65.0000
V_fixture = 2.5000
V_fixture_min = 2.3000
V_fixture_max = 2.7000
| time   V(typ)   V(min)   V(max)
0s        1.284V     NA         NA
300ps     1.284V     NA         NA
600ps     1.299V     NA         NA
900ps     1.609V     NA         NA
1.2ns     2.073V     NA         NA
1.5ns     2.364V     NA         NA
1.8ns     2.474V     NA         NA
2.1ns     2.494V     NA         NA
3ns       2.499V     NA         NA
15ns      2.5V       NA         NA
[Falling Waveform]
R_fixture = 65.0000
V_fixture = 0.000
| time   V(typ)   V(min)   V(max)
0s        1.234V     NA         NA
300ps     1.234V     NA         NA
600ps     1.214V     NA         NA
900ps     889.6mV    NA         NA
1.2ns     495.9mV    NA         NA
1.5ns     175.7mV    NA         NA
1.8ns     36.73mV    NA         NA
2.1ns     3.767mV    NA         NA
15ns      -1.743uV   NA         NA
[Falling Waveform]
R_fixture = 65.0000
V_fixture = 2.5000
V_fixture_min = 2.3000
V_fixture_max = 2.7000
| time   V(typ)   V(min)   V(max)
0s        2.5V       NA         NA
900ps     2.5V       NA         NA
1.2ns     2.434V     NA         NA
1.5ns     2.222V     NA         NA
1.8ns     1.917V     NA         NA
2.1ns     1.698V     NA         NA
2.7ns     1.44V      NA         NA
3ns       1.345V     NA         NA
3.3ns     1.317V     NA         NA
15ns      1.284V     NA         NA
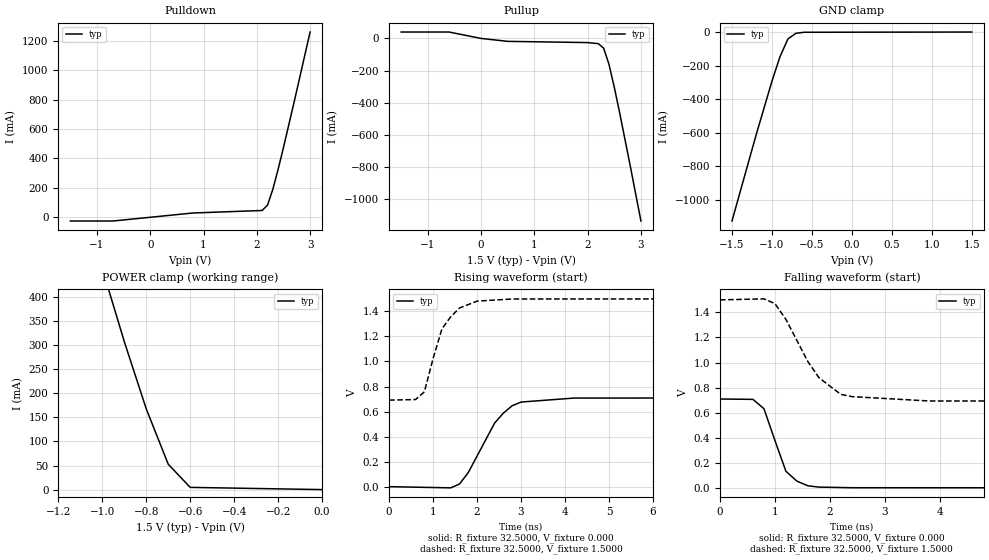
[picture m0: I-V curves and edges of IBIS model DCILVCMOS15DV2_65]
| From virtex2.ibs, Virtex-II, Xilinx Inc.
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|   Model DCILVCMOS15DV2_65
[Model]   DCILVCMOS15DV2_65
Model_type   I/O
Polarity   Non-Inverting
Enable   Active-Low
Vinh = 1.05V
Vinl = 0.3V
Vmeas =   0.75V
Cref =  0pF
Rref =   1.00M
Vref =  0.000V
C_comp   7.0000pF   NA   NA
[Temperature Range]   25.0000   NA   NA
[Voltage Range]   1.5000V   NA   NA
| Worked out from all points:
|   slope of the pulldown table from 0 to 0.225 V, typ, clamps not added: 23.9 ohm
|   slope of the pullup table from 0 to 0.225 V, typ, clamps not added: 21.7 ohm
|   GND clamp passes 1 mA (typ) near -0.57 V on its own axis
|   POWER clamp passes 1 mA (typ) near -0.52 V on its own axis
|   rising waveform, R_fixture 32.5000, V_fixture 0.000: 20-80 % time 703ps typ, NA min, NA max; typ from 0 V to 0.709 V
|   rising waveform, R_fixture 32.5000, V_fixture 1.5000: 20-80 % time 489ps typ, NA min, NA max; typ from 0.691 V to 1.5 V
|   falling waveform, R_fixture 32.5000, V_fixture 0.000: 20-80 % time 341ps typ, NA min, NA max; typ from 0.709 V to 0 V
|   falling waveform, R_fixture 32.5000, V_fixture 1.5000: 20-80 % time 660ps typ, NA min, NA max; typ from 1.5 V to 0.692 V
[Pulldown]
| voltage   I(typ)   I(min)   I(max)
-1.5V     -26.93mA   NA         NA
-700mV    -26.93mA   NA         NA
800mV     27.71mA    NA         NA
2.1V      44.78mA    NA         NA
2.2V      80.94mA    NA         NA
2.3V      188.1mA    NA         NA
2.4V      325.6mA    NA         NA
2.5V      473.6mA    NA         NA
2.7V      783.3mA    NA         NA
3V        1.261A     NA         NA
[Pullup]
| voltage   I(typ)   I(min)   I(max)
-1.5V     39.79mA    NA         NA
-600mV    39.79mA    NA         NA
0V        -9.4nA     NA         NA
500mV     -18.25mA   NA         NA
2V        -25.82mA   NA         NA
2.2V      -32.54mA   NA         NA
2.3V      -60.37mA   NA         NA
2.4V      -160.6mA   NA         NA
2.5V      -303.6mA   NA         NA
2.6V      -461.4mA   NA         NA
2.8V      -793.9mA   NA         NA
3V        -1.136A    NA         NA
[GND_clamp]
| voltage   I(typ)   I(min)   I(max)
-1.5V     -1.127A    NA         NA
-1.2V     -617mA     NA         NA
-1V       -293.4mA   NA         NA
-900mV    -148mA     NA         NA
-800mV    -41mA      NA         NA
-700mV    -7.588mA   NA         NA
-600mV    -1.413mA   NA         NA
1.5V      218.4nA    NA         NA
[POWER_clamp]
| voltage   I(typ)   I(min)   I(max)
-1.5V     1.246A     NA         NA
-1.1V     610.9mA    NA         NA
-900mV    307.7mA    NA         NA
-800mV    167.8mA    NA         NA
-700mV    52.78mA    NA         NA
-600mV    4.607mA    NA         NA
0V        218.4nA    NA         NA
[Ramp]
| variable   typ   min   max
dV/dt_r   0.4253/0.6878n   NA   NA
dV/dt_f   0.4851/0.6071n   NA   NA
R_load = 32.5000
[Rising Waveform]
R_fixture = 32.5000
V_fixture = 0.000
| time   V(typ)   V(min)   V(max)
0s        4.725uV    NA         NA
1.4ns     -9.368mV   NA         NA
1.6ns     21.11mV    NA         NA
1.8ns     113mV      NA         NA
2.4ns     508.5mV    NA         NA
2.6ns     588.4mV    NA         NA
2.8ns     646.8mV    NA         NA
3ns       675.9mV    NA         NA
4.2ns     707.6mV    NA         NA
10ns      708.9mV    NA         NA
[Rising Waveform]
R_fixture = 32.5000
V_fixture = 1.5000
V_fixture_min = 1.4000
V_fixture_max = 1.6000
| time   V(typ)   V(min)   V(max)
0s        691.4mV    NA         NA
600ps     695.9mV    NA         NA
800ps     757.2mV    NA         NA
1ns       1.024V     NA         NA
1.2ns     1.26V      NA         NA
1.4ns     1.357V     NA         NA
1.6ns     1.427V     NA         NA
2ns       1.482V     NA         NA
2.8ns     1.499V     NA         NA
10ns      1.5V       NA         NA
[Falling Waveform]
R_fixture = 32.5000
V_fixture = 0.000
| time   V(typ)   V(min)   V(max)
0s        708.9mV    NA         NA
600ps     706mV      NA         NA
800ps     631.5mV    NA         NA
1ns       377.8mV    NA         NA
1.2ns     131.7mV    NA         NA
1.4ns     53.57mV    NA         NA
1.6ns     16.17mV    NA         NA
1.8ns     5.958mV    NA         NA
2.4ns     1.012mV    NA         NA
10ns      -14.79uV   NA         NA
[Falling Waveform]
R_fixture = 32.5000
V_fixture = 1.5000
V_fixture_min = 1.4000
V_fixture_max = 1.6000
| time   V(typ)   V(min)   V(max)
0s        1.5V       NA         NA
800ps     1.508V     NA         NA
1ns       1.47V      NA         NA
1.2ns     1.344V     NA         NA
1.6ns     1.007V     NA         NA
1.8ns     879.3mV    NA         NA
2.2ns     745.6mV    NA         NA
2.4ns     728mV      NA         NA
3.8ns     693.2mV    NA         NA
10ns      691.5mV    NA         NA
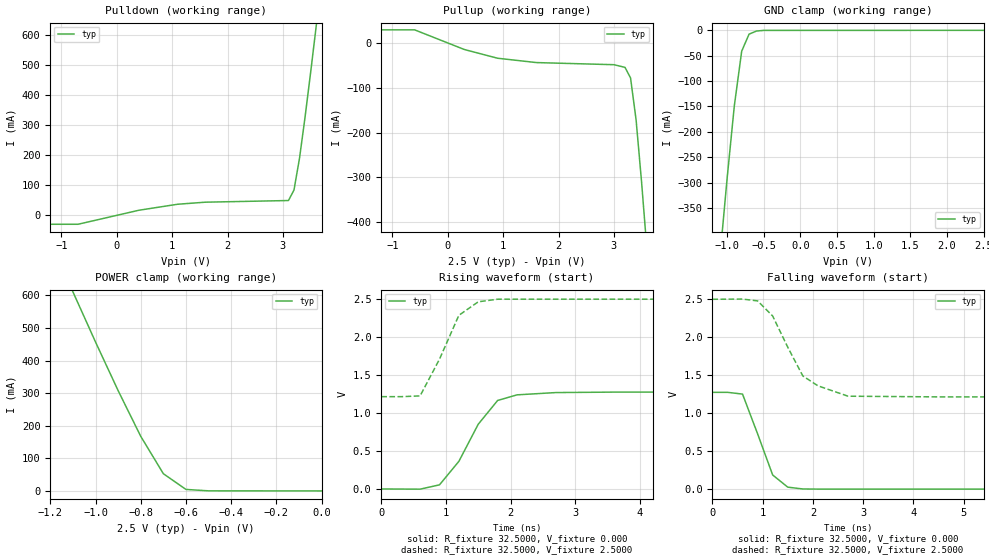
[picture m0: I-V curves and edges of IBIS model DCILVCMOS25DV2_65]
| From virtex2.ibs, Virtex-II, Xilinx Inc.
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|   Model DCILVCMOS25DV2_65
[Model]   DCILVCMOS25DV2_65
Model_type   I/O
Polarity   Non-Inverting
Enable   Active-Low
Vinh = 1.7V
Vinl = 0.7V
Vmeas =   1.25V
Cref =  0pF
Rref =   1.00M
Vref =  0.000V
C_comp   7.0000pF   NA   NA
[Temperature Range]   25.0000   NA   NA
[Voltage Range]   2.5000V   NA   NA
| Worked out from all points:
|   slope of the pulldown table from 0 to 0.375 V, typ, clamps not added: 22.9 ohm
|   slope of the pullup table from 0 to 0.375 V, typ, clamps not added: 22.5 ohm
|   GND clamp passes 1 mA (typ) near -0.57 V on its own axis
|   POWER clamp passes 1 mA (typ) near -0.52 V on its own axis
|   rising waveform, R_fixture 32.5000, V_fixture 0.000: 20-80 % time 566ps typ, NA min, NA max; typ from 0 V to 1.27 V
|   rising waveform, R_fixture 32.5000, V_fixture 2.5000: 20-80 % time 424ps typ, NA min, NA max; typ from 1.22 V to 2.5 V
|   falling waveform, R_fixture 32.5000, V_fixture 0.000: 20-80 % time 429ps typ, NA min, NA max; typ from 1.27 V to 0 V
|   falling waveform, R_fixture 32.5000, V_fixture 2.5000: 20-80 % time 617ps typ, NA min, NA max; typ from 2.5 V to 1.22 V
[Pulldown]
| voltage   I(typ)   I(min)   I(max)
-2.5V     -29.43mA   NA         NA
-700mV    -29.43mA   NA         NA
400mV     17.34mA    NA         NA
1.1V      37.38mA    NA         NA
1.6V      44.23mA    NA         NA
3.1V      49.76mA    NA         NA
3.2V      84.49mA    NA         NA
3.3V      190.6mA    NA         NA
3.4V      327.7mA    NA         NA
3.5V      475.6mA    NA         NA
3.6V      628.9mA    NA         NA
5V        2.891A     NA         NA
[Pullup]
| voltage   I(typ)   I(min)   I(max)
-2.5V     30.51mA    NA         NA
-600mV    30.51mA    NA         NA
300mV     -13.68mA   NA         NA
900mV     -33.24mA   NA         NA
1.6V      -42.95mA   NA         NA
3V        -47.71mA   NA         NA
3.2V      -53.72mA   NA         NA
3.3V      -77.44mA   NA         NA
3.4V      -171.4mA   NA         NA
3.5V      -312.3mA   NA         NA
3.6V      -469.3mA   NA         NA
5V        -2.896A    NA         NA
[GND_clamp]
| voltage   I(typ)   I(min)   I(max)
-2.5V     -2.881A    NA         NA
-1.1V     -452.1mA   NA         NA
-1V       -293.4mA   NA         NA
-900mV    -148.1mA   NA         NA
-800mV    -41.04mA   NA         NA
-700mV    -7.632mA   NA         NA
-600mV    -1.432mA   NA         NA
-500mV    -131.2uA   NA         NA
2.5V      397.5nA    NA         NA
[POWER_clamp]
| voltage   I(typ)   I(min)   I(max)
-2.5V     2.874A     NA         NA
-1.1V     610.9mA    NA         NA
-1V       456.9mA    NA         NA
-900mV    307.7mA    NA         NA
-800mV    167.5mA    NA         NA
-700mV    52.78mA    NA         NA
-600mV    4.607mA    NA         NA
-500mV    279.3uA    NA         NA
0V        397.5nA    NA         NA
[Ramp]
| variable   typ   min   max
dV/dt_r   0.7650/0.5000n   NA   NA
dV/dt_f   0.7710/0.6731n   NA   NA
R_load = 32.5000
[Rising Waveform]
R_fixture = 32.5000
V_fixture = 0.000
| time   V(typ)   V(min)   V(max)
0s        6.382uV    NA         NA
600ps     -2.675mV   NA         NA
900ps     54.08mV    NA         NA
1.2ns     363.1mV    NA         NA
1.5ns     852.3mV    NA         NA
1.8ns     1.165V     NA         NA
2.1ns     1.239V     NA         NA
2.7ns     1.269V     NA         NA
3.6ns     1.275V     NA         NA
15ns      1.275V     NA         NA
[Rising Waveform]
R_fixture = 32.5000
V_fixture = 2.5000
V_fixture_min = 2.3000
V_fixture_max = 2.7000
| time   V(typ)   V(min)   V(max)
0s        1.215V     NA         NA
300ps     1.215V     NA         NA
600ps     1.225V     NA         NA
900ps     1.708V     NA         NA
1.2ns     2.286V     NA         NA
1.5ns     2.464V     NA         NA
1.8ns     2.498V     NA         NA
15ns      2.5V       NA         NA
[Falling Waveform]
R_fixture = 32.5000
V_fixture = 0.000
| time   V(typ)   V(min)   V(max)
0s        1.275V     NA         NA
300ps     1.275V     NA         NA
600ps     1.252V     NA         NA
900ps     728.6mV    NA         NA
1.2ns     186.6mV    NA         NA
1.5ns     26.61mV    NA         NA
1.8ns     2.612mV    NA         NA
2.1ns     826.2uV    NA         NA
15ns      5.956uV    NA         NA
[Falling Waveform]
R_fixture = 32.5000
V_fixture = 2.5000
V_fixture_min = 2.3000
V_fixture_max = 2.7000
| time   V(typ)   V(min)   V(max)
0s        2.5V       NA         NA
600ps     2.503V     NA         NA
900ps     2.479V     NA         NA
1.2ns     2.28V      NA         NA
1.5ns     1.869V     NA         NA
1.8ns     1.491V     NA         NA
2.1ns     1.361V     NA         NA
2.7ns     1.224V     NA         NA
4.5ns     1.215V     NA         NA
15ns      1.215V     NA         NA
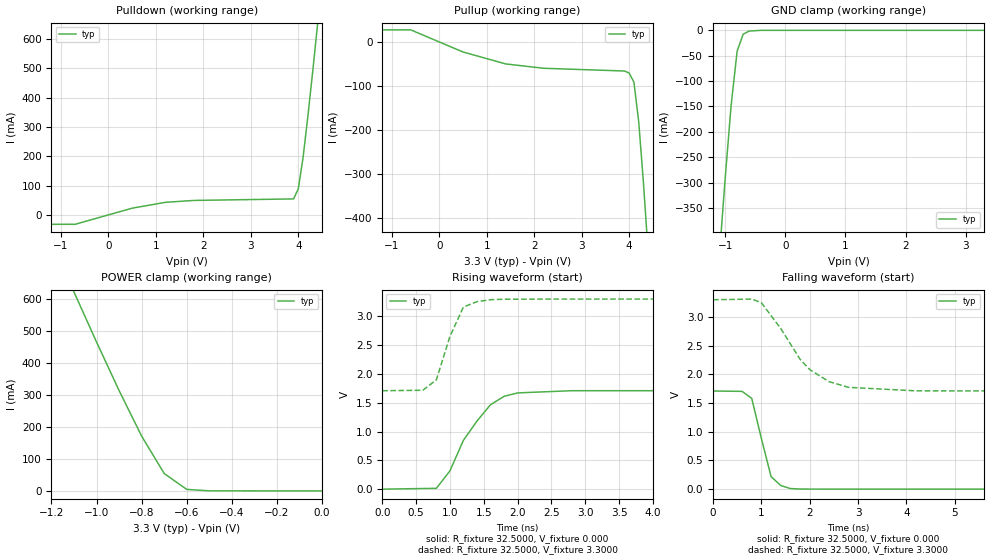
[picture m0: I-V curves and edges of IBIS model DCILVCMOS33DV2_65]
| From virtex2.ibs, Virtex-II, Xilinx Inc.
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|   Model DCILVCMOS33DV2_65
[Model]   DCILVCMOS33DV2_65
Model_type   I/O
Polarity   Non-Inverting
Enable   Active-Low
Vinh = 2.0V
Vinl = 0.8V
Vmeas =   1.65V
Cref =  0pF
Rref =   1.00M
Vref =  0.000V
C_comp   7.0000pF   NA   NA
[Temperature Range]   25.0000   NA   NA
[Voltage Range]   3.3000V   NA   NA
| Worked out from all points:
|   slope of the pulldown table from 0 to 0.495 V, typ, clamps not added: 21.8 ohm
|   slope of the pullup table from 0 to 0.495 V, typ, clamps not added: 22.8 ohm
|   GND clamp passes 1 mA (typ) near -0.57 V on its own axis
|   POWER clamp passes 1 mA (typ) near -0.52 V on its own axis
|   rising waveform, R_fixture 32.5000, V_fixture 0.000: 20-80 % time 521ps typ, NA min, NA max; typ from 0 V to 1.71 V
|   rising waveform, R_fixture 32.5000, V_fixture 3.3000: 20-80 % time 295ps typ, NA min, NA max; typ from 1.71 V to 3.3 V
|   falling waveform, R_fixture 32.5000, V_fixture 0.000: 20-80 % time 302ps typ, NA min, NA max; typ from 1.71 V to 0 V
|   falling waveform, R_fixture 32.5000, V_fixture 3.3000: 20-80 % time 845ps typ, NA min, NA max; typ from 3.3 V to 1.71 V
[Pulldown]
| voltage   I(typ)   I(min)   I(max)
-3.3V     -32.11mA   NA         NA
-700mV    -32.11mA   NA         NA
500mV     22.88mA    NA         NA
1.2V      42.83mA    NA         NA
1.8V      49.32mA    NA         NA
3.9V      54.53mA    NA         NA
4V        89.07mA    NA         NA
4.1V      196.2mA    NA         NA
4.2V      335.2mA    NA         NA
4.3V      485.2mA    NA         NA
4.5V      799.3mA    NA         NA
6.6V      4.271A     NA         NA
[Pullup]
| voltage   I(typ)   I(min)   I(max)
-3.3V     28.49mA    NA         NA
-600mV    28.49mA    NA         NA
500mV     -21.9mA    NA         NA
1.4V      -49.12mA   NA         NA
2.2V      -59.01mA   NA         NA
3.9V      -65.23mA   NA         NA
4V        -69.8mA    NA         NA
4.1V      -90.79mA   NA         NA
4.2V      -179.8mA   NA         NA
4.3V      -319mA     NA         NA
4.5V      -638.9mA   NA         NA
6.6V      -4.321A    NA         NA
[GND_clamp]
| voltage   I(typ)   I(min)   I(max)
-3.3V     -4.301A    NA         NA
-1.1V     -452.1mA   NA         NA
-1V       -293.4mA   NA         NA
-900mV    -148.1mA   NA         NA
-800mV    -41.07mA   NA         NA
-700mV    -7.668mA   NA         NA
-600mV    -1.449mA   NA         NA
-400mV    -8.141uA   NA         NA
3.3V      540.8nA    NA         NA
[POWER_clamp]
| voltage   I(typ)   I(min)   I(max)
-3.3V     4.254A     NA         NA
-1.1V     621.4mA    NA         NA
-1V       465.1mA    NA         NA
-900mV    313.6mA    NA         NA
-800mV    171.2mA    NA         NA
-700mV    54.37mA    NA         NA
-600mV    4.797mA    NA         NA
-500mV    289.2uA    NA         NA
0V        540.8nA    NA         NA
[Ramp]
| variable   typ   min   max
dV/dt_r   1.0260/0.4491n   NA   NA
dV/dt_f   0.9546/0.7976n   NA   NA
R_load = 32.5000
[Rising Waveform]
R_fixture = 32.5000
V_fixture = 0.000
| time   V(typ)   V(min)   V(max)
0s        8.575uV    NA         NA
800ps     14.81mV    NA         NA
1ns       317.1mV    NA         NA
1.2ns     848.6mV    NA         NA
1.4ns     1.182V     NA         NA
1.6ns     1.466V     NA         NA
1.8ns     1.611V     NA         NA
2ns       1.671V     NA         NA
2.8ns     1.709V     NA         NA
10ns      1.71V      NA         NA
[Rising Waveform]
R_fixture = 32.5000
V_fixture = 3.3000
V_fixture_min = 3.0000
V_fixture_max = 3.6000
| time   V(typ)   V(min)   V(max)
0s        1.709V     NA         NA
600ps     1.717V     NA         NA
800ps     1.898V     NA         NA
1ns       2.651V     NA         NA
1.2ns     3.162V     NA         NA
1.4ns     3.255V     NA         NA
1.6ns     3.289V     NA         NA
1.8ns     3.297V     NA         NA
2.6ns     3.3V       NA         NA
10ns      3.3V       NA         NA
[Falling Waveform]
R_fixture = 32.5000
V_fixture = 0.000
| time   V(typ)   V(min)   V(max)
0s        1.71V      NA         NA
600ps     1.704V     NA         NA
800ps     1.582V     NA         NA
1ns       881.1mV    NA         NA
1.2ns     219.4mV    NA         NA
1.4ns     63.12mV    NA         NA
1.6ns     10.7mV     NA         NA
1.8ns     2.152mV    NA         NA
2.4ns     564.4uV    NA         NA
10ns      1.487uV    NA         NA
[Falling Waveform]
R_fixture = 32.5000
V_fixture = 3.3000
V_fixture_min = 3.0000
V_fixture_max = 3.6000
| time   V(typ)   V(min)   V(max)
0s        3.3V       NA         NA
800ps     3.312V     NA         NA
1ns       3.248V     NA         NA
1.4ns     2.799V     NA         NA
1.8ns     2.263V     NA         NA
2ns       2.083V     NA         NA
2.4ns     1.873V     NA         NA
2.8ns     1.774V     NA         NA
4.2ns     1.713V     NA         NA
10ns      1.709V     NA         NA
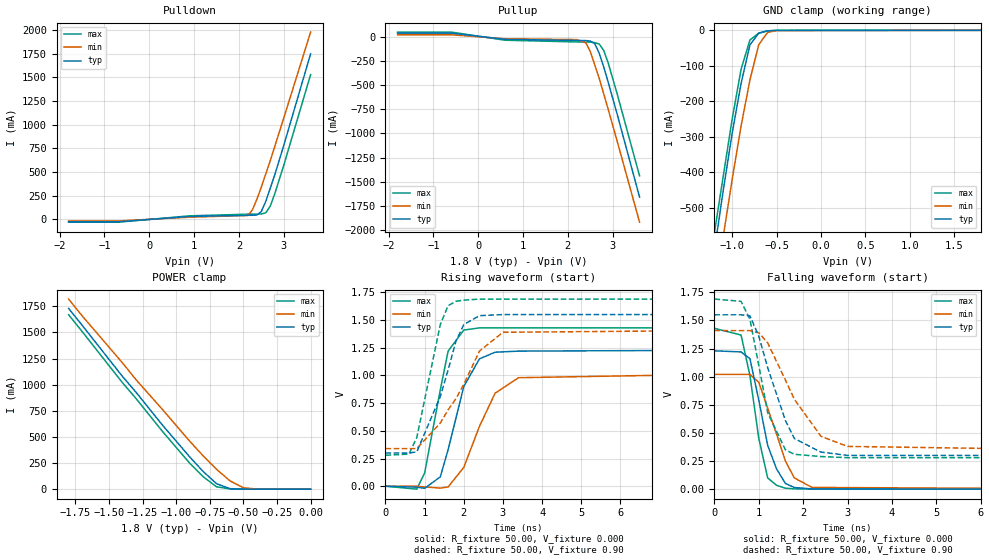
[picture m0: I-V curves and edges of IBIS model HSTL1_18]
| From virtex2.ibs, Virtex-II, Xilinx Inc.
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|   Model HSTL1_18
[Model]   HSTL1_18
Model_type   I/O
Polarity   Non-Inverting
Enable   Active-Low
Vinh = 1.0V
Vinl = 0.8V
Vmeas =   0.90V
Cref =  0pF
Rref =  50.00
Vref =   0.90V
C_comp   10.00pF   10.00pF   10.00pF
[Temperature Range]   25.00   100.00   0.000
[Voltage Range]   1.80V   1.70V   1.90V
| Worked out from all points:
|   slope of the pulldown table from 0 to 0.27 V, typ, clamps not added: 24.3 ohm
|   slope of the pullup table from 0 to 0.27 V, typ, clamps not added: 19.5 ohm
|   GND clamp passes 1 mA (typ) near -0.57 V on its own axis
|   POWER clamp passes 1 mA (typ) near -0.52 V on its own axis
|   rising waveform, R_fixture 50.00, V_fixture 0.000: 20-80 % time 567ps typ, 728ps min, 469ps max; typ from 0 V to 1.23 V
|   rising waveform, R_fixture 50.00, V_fixture 0.90: 20-80 % time 708ps typ, 992ps min, 487ps max; typ from 0.3 V to 1.55 V
|   falling waveform, R_fixture 50.00, V_fixture 0.000: 20-80 % time 442ps typ, 545ps min, 368ps max; typ from 1.23 V to 0 V
|   falling waveform, R_fixture 50.00, V_fixture 0.90: 20-80 % time 632ps typ, 826ps min, 468ps max; typ from 1.55 V to 0.3 V
[Pulldown]
| voltage   I(typ)   I(min)   I(max)
-1.8V     -26.88mA   -18.06mA   -30.9mA
-700mV    -26.88mA   -18.06mA   -30.9mA
900mV     30.07mA    21.92mA    36.24mA
2.2V      42.1mA     40.25mA    53.94mA
2.3V      42.39mA    98.99mA    54.11mA
2.4V      45.16mA    210mA      54.39mA
2.5V      81.17mA    340mA      55.95mA
2.6V      190mA      480mA      68.22mA
2.7V      330mA      620mA      140mA
2.8V      470mA      770mA      270mA
3V        780mA      1.07A      570mA
3.6V      1.75A      1.98A      1.53A
[Pullup]
| voltage   I(typ)   I(min)   I(max)
-1.8V     39.53mA    22.35mA    50.25mA
-600mV    39.53mA    22.35mA    50.25mA
600mV     -25.23mA   -18.99mA   -34.06mA
2.2V      -36.44mA   -27.71mA   -51.87mA
2.4V      -37.84mA   -60.77mA   -52.52mA
2.5V      -43.04mA   -150mA     -53.71mA
2.6V      -68.77mA   -290mA     -59.14mA
2.7V      -170mA     -430mA     -73.59mA
2.8V      -310mA     -590mA     -140mA
2.9V      -470mA     -750mA     -270mA
3.1V      -800mA     -1.08A     -590mA
3.6V      -1.66A     -1.92A     -1.44A
[GND_clamp]
| voltage   I(typ)   I(min)   I(max)
-1.8V     -1.65A     -1.74A     -1.6A
-1.2V     -620mA     -740mA     -570mA
-1.1V     -450mA     -580mA     -410mA
-1V       -290mA     -420mA     -250mA
-900mV    -150mA     -270mA     -110mA
-800mV    -40.97mA   -140mA     -27.17mA
-700mV    -7.54mA    -40.17mA   -8.08mA
-600mV    -1.39mA    -5.57mA    -1.57mA
-500mV    -120uA     -660uA     -120uA
1.8V      34.27pA    98.88nA    22.46pA
[POWER_clamp]
| voltage   I(typ)   I(min)   I(max)
-1.8V     1.73A      1.82A      1.67A
-1.7V     1.57A      1.66A      1.51A
-1.4V     1.08A      1.21A      1.02A
-1.3V     930mA      1.05A      870mA
-1.1V     610mA      760mA      550mA
-900mV    310mA      460mA      250mA
-800mV    170mA      320mA      120mA
-700mV    52.75mA    190mA      22.81mA
-600mV    4.57mA     79.88mA    2.44mA
-500mV    270uA      13.45mA    250uA
-400mV    16.38uA    820uA      14.46uA
0V        34.27pA    1.07nA     29.84pA
[Ramp]
| variable   typ   min   max
dV/dt_r   0.74/0.54n   0.61/0.75n   0.86/0.38n
dV/dt_f   0.70/0.68n   0.58/1.02n   0.78/0.51n
R_load = 50.00
[Rising Waveform]
R_fixture = 50.00
V_fixture = 0.000
| time   V(typ)   V(min)   V(max)
0s        0V         0V         0V
800ps     -8.52mV    -280uV     -26.52mV
1ns       -19.22mV   -6.19mV    120mV
1.4ns     84.62mV    -16.93mV   870mV
1.6ns     330mV      -6.41mV    1.22V
2ns       900mV      170mV      1.41V
2.4ns     1.15V      540mV      1.43V
2.8ns     1.21V      840mV      1.43V
3.4ns     1.22V      980mV      1.43V
10ns      1.23V      1.02V      1.43V
[Rising Waveform]
R_fixture = 50.00
V_fixture = 0.90
V_fixture_min = 0.85
V_fixture_max = 0.95
| time   V(typ)   V(min)   V(max)
0s        300mV      340mV      280mV
600ps     300mV      340mV      290mV
800ps     310mV      340mV      440mV
1.4ns     810mV      570mV      1.46V
1.6ns     1.05V      690mV      1.63V
1.8ns     1.31V      790mV      1.67V
2ns       1.46V      920mV      1.68V
2.4ns     1.54V      1.22V      1.69V
3ns       1.55V      1.39V      1.69V
10ns      1.55V      1.41V      1.69V
[Falling Waveform]
R_fixture = 50.00
V_fixture = 0.000
| time   V(typ)   V(min)   V(max)
0s        1.23V      1.02V      1.43V
600ps     1.22V      1.02V      1.37V
800ps     1.16V      1.02V      1.01V
1ns       790mV      950mV      450mV
1.2ns     390mV      720mV      100mV
1.4ns     180mV      490mV      34.17mV
1.6ns     50.98mV    250mV      8.49mV
1.8ns     14.74mV    100mV      2.78mV
2.2ns     2.05mV     15.47mV    970uV
10ns      -2.34uV    -1.56uV    -1.37uV
[Falling Waveform]
R_fixture = 50.00
V_fixture = 0.90
V_fixture_min = 0.85
V_fixture_max = 0.95
| time   V(typ)   V(min)   V(max)
0s        1.55V      1.41V      1.69V
600ps     1.55V      1.41V      1.67V
800ps     1.54V      1.41V      1.51V
1ns       1.36V      1.39V      1.1V
1.2ns     1.08V      1.3V       680mV
1.6ns     610mV      970mV      350mV
1.8ns     450mV      800mV      310mV
2.4ns     330mV      470mV      290mV
3ns       300mV      380mV      280mV
10ns      300mV      340mV      280mV
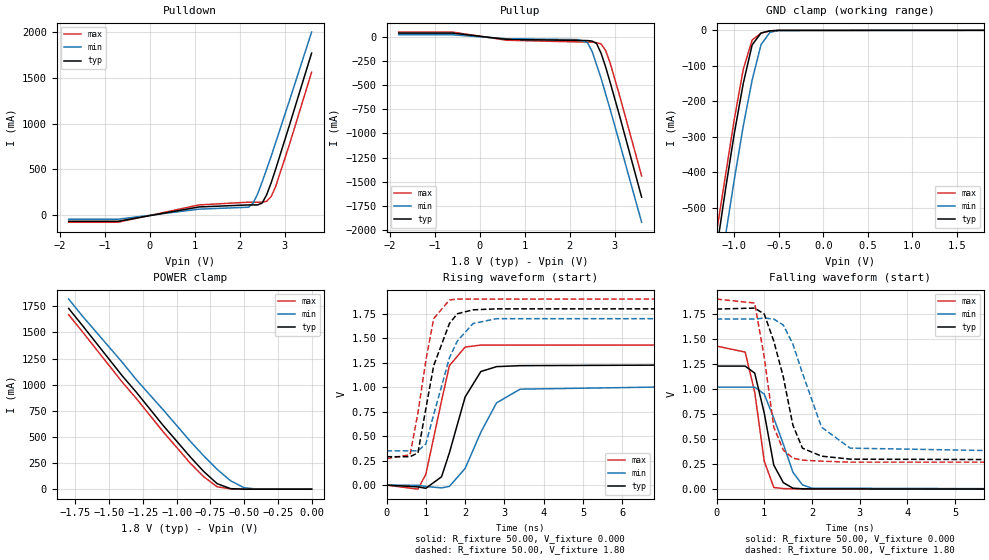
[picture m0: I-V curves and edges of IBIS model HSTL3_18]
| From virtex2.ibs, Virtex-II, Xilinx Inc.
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|   Model HSTL3_18
[Model]   HSTL3_18
Model_type   I/O
Polarity   Non-Inverting
Enable   Active-Low
Vinh = 1.2V
Vinl = 1.0V
Vmeas =   1.10V
Cref =  0pF
Rref =  50.00
Vref =   1.80V
C_comp   10.00pF   10.00pF   10.00pF
[Temperature Range]   25.00   100.00   0.000
[Voltage Range]   1.80V   1.70V   1.90V
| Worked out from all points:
|   slope of the pulldown table from 0 to 0.27 V, typ, clamps not added: 9.58 ohm
|   slope of the pullup table from 0 to 0.27 V, typ, clamps not added: 19.5 ohm
|   GND clamp passes 1 mA (typ) near -0.57 V on its own axis
|   POWER clamp passes 1 mA (typ) near -0.52 V on its own axis
|   rising waveform, R_fixture 50.00, V_fixture 0.000: 20-80 % time 567ps typ, 728ps min, 468ps max; typ from 0 V to 1.23 V
|   rising waveform, R_fixture 50.00, V_fixture 1.80: 20-80 % time 539ps typ, 620ps min, 408ps max; typ from 0.29 V to 1.8 V
|   falling waveform, R_fixture 50.00, V_fixture 0.000: 20-80 % time 310ps typ, 464ps min, 285ps max; typ from 1.23 V to 0 V
|   falling waveform, R_fixture 50.00, V_fixture 1.80: 20-80 % time 455ps typ, 586ps min, 315ps max; typ from 1.8 V to 0.29 V
[Pulldown]
| voltage   I(typ)   I(min)   I(max)
-1.8V     -68.81mA   -46.42mA   -79.03mA
-700mV    -68.81mA   -46.42mA   -78.65mA
1.1V      87.62mA    63.65mA    110mA
2.2V      110mA      84.62mA    140mA
2.3V      110mA      130mA      140mA
2.4V      110mA      230mA      140mA
2.5V      130mA      360mA      140mA
2.6V      220mA      500mA      150mA
2.7V      350mA      640mA      200mA
2.8V      500mA      790mA      310mA
3.1V      970mA      1.24A      760mA
3.6V      1.77A      2A         1.56A
[Pullup]
| voltage   I(typ)   I(min)   I(max)
-1.8V     39.53mA    22.35mA    50.25mA
-600mV    39.53mA    22.35mA    50.25mA
600mV     -25.23mA   -18.99mA   -34.06mA
2.2V      -36.44mA   -27.71mA   -51.87mA
2.4V      -37.84mA   -60.77mA   -52.52mA
2.5V      -43.04mA   -150mA     -53.71mA
2.6V      -68.77mA   -290mA     -59.14mA
2.7V      -170mA     -430mA     -73.59mA
2.8V      -310mA     -590mA     -140mA
2.9V      -470mA     -750mA     -270mA
3.1V      -800mA     -1.08A     -590mA
3.6V      -1.66A     -1.92A     -1.44A
[GND_clamp]
| voltage   I(typ)   I(min)   I(max)
-1.8V     -1.65A     -1.74A     -1.6A
-1.2V     -620mA     -740mA     -570mA
-1.1V     -450mA     -580mA     -410mA
-1V       -290mA     -420mA     -250mA
-900mV    -150mA     -270mA     -110mA
-800mV    -40.97mA   -140mA     -27.17mA
-700mV    -7.54mA    -40.17mA   -8.08mA
-600mV    -1.39mA    -5.57mA    -1.57mA
-500mV    -120uA     -660uA     -120uA
1.8V      34.27pA    98.88nA    22.46pA
[POWER_clamp]
| voltage   I(typ)   I(min)   I(max)
-1.8V     1.73A      1.82A      1.67A
-1.7V     1.57A      1.66A      1.51A
-1.4V     1.08A      1.21A      1.02A
-1.3V     930mA      1.05A      870mA
-1.1V     610mA      760mA      550mA
-900mV    310mA      460mA      250mA
-800mV    170mA      320mA      120mA
-700mV    52.75mA    190mA      22.81mA
-600mV    4.57mA     79.88mA    2.44mA
-500mV    270uA      13.45mA    250uA
-400mV    16.38uA    820uA      14.46uA
0V        34.27pA    1.07nA     29.84pA
[Ramp]
| variable   typ   min   max
dV/dt_r   0.74/0.54n   0.61/0.75n   0.86/0.38n
dV/dt_f   0.91/0.38n   0.81/0.59n   0.98/0.29n
R_load = 50.00
[Rising Waveform]
R_fixture = 50.00
V_fixture = 0.000
| time   V(typ)   V(min)   V(max)
0s        0V         0V         0V
800ps     -18.08mV   -1.58mV    -41.47mV
1ns       -32.48mV   -14.19mV   110mV
1.4ns     85.16mV    -28.27mV   860mV
1.6ns     330mV      -13.14mV   1.22V
2ns       900mV      170mV      1.41V
2.4ns     1.16V      540mV      1.43V
2.8ns     1.21V      840mV      1.43V
3.4ns     1.22V      980mV      1.43V
10ns      1.23V      1.02V      1.43V
[Rising Waveform]
R_fixture = 50.00
V_fixture = 1.80
V_fixture_min = 1.70
V_fixture_max = 1.90
| time   V(typ)   V(min)   V(max)
0s        290mV      350mV      270mV
600ps     290mV      350mV      310mV
800ps     330mV      350mV      740mV
1ns       780mV      420mV      1.27V
1.2ns     1.22V      720mV      1.7V
1.6ns     1.65V      1.3V       1.89V
1.8ns     1.75V      1.47V      1.9V
2.2ns     1.79V      1.65V      1.9V
2.8ns     1.8V       1.7V       1.9V
10ns      1.8V       1.7V       1.9V
[Falling Waveform]
R_fixture = 50.00
V_fixture = 0.000
| time   V(typ)   V(min)   V(max)
0s        1.23V      1.02V      1.43V
600ps     1.23V      1.02V      1.37V
800ps     1.16V      1.02V      970mV
1ns       760mV      950mV      280mV
1.2ns     240mV      710mV      16.99mV
1.4ns     65.06mV    450mV      6.17mV
1.6ns     10.2mV     170mV      3.05mV
1.8ns     3.95mV     43.17mV    2.04mV
2ns       2.46mV     9.52mV     1.41mV
10ns      -530nV     -660nV     0V
[Falling Waveform]
R_fixture = 50.00
V_fixture = 1.80
V_fixture_min = 1.70
V_fixture_max = 1.90
| time   V(typ)   V(min)   V(max)
0s        1.8V       1.7V       1.9V
800ps     1.81V      1.7V       1.86V
1ns       1.75V      1.71V      1.32V
1.2ns     1.48V      1.7V       620mV
1.4ns     1.12V      1.64V      390mV
1.6ns     640mV      1.45V      310mV
1.8ns     410mV      1.16V      290mV
2.2ns     330mV      620mV      280mV
2.8ns     300mV      410mV      270mV
10ns      290mV      350mV      270mV
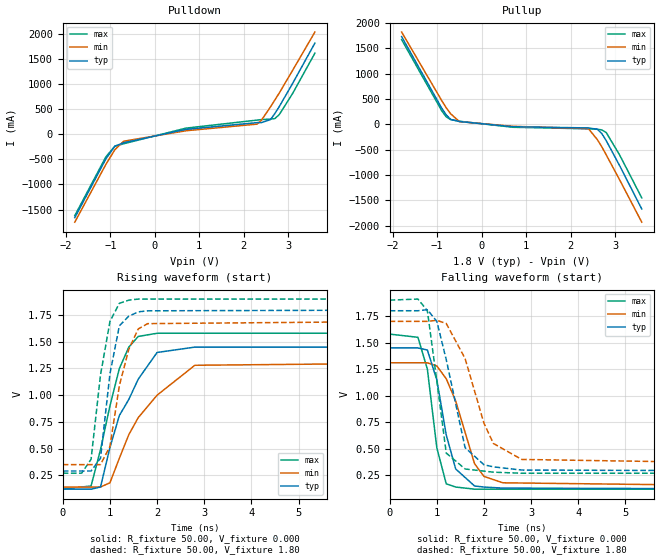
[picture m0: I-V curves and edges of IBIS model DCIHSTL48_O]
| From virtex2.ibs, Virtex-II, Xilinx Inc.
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|   Model DCIHSTL48_O
[Model]   DCIHSTL48_O
Model_type   Output
Polarity   Non-Inverting
Vmeas =   1.10V
Cref =  0pF
Rref =  50.00
Vref =   1.80V
C_comp   10.00pF   10.00pF   10.00pF
[Temperature Range]   25.00   100.00   0.000
[Voltage Range]   1.80V   1.70V   1.90V
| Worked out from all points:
|   slope of the pulldown table from 0 to 0.27 V, typ, clamps not added: 5.05 ohm
|   slope of the pullup table from 0 to 0.27 V, typ, clamps not added: 11.7 ohm
|   rising waveform, R_fixture 50.00, V_fixture 0.000: 20-80 % time 710ps typ, 983ps min, 484ps max; typ from 0.12 V to 1.45 V
|   rising waveform, R_fixture 50.00, V_fixture 1.80: 20-80 % time 286ps typ, 365ps min, 304ps max; typ from 0.29 V to 1.8 V
|   falling waveform, R_fixture 50.00, V_fixture 0.000: 20-80 % time 377ps typ, 510ps min, 283ps max; typ from 1.45 V to 0.12 V
|   falling waveform, R_fixture 50.00, V_fixture 1.80: 20-80 % time 448ps typ, 593ps min, 292ps max; typ from 1.8 V to 0.29 V
[Pulldown]
| voltage   I(typ)   I(min)   I(max)
-1.8V     -1.66A     -1.75A     -1.62A
-1.1V     -490mA     -600mA     -450mA
-900mV    -240mA     -310mA     -240mA
-700mV    -170mA     -140mA     -190mA
700mV     95.94mA    68.04mA    120mA
2.3V      230mA      200mA      280mA
2.4V      230mA      280mA      290mA
2.6V      290mA      540mA      300mA
2.7V      410mA      680mA      310mA
2.8V      550mA      820mA      390mA
3.1V      1.01A      1.27A      810mA
3.6V      1.81A      2.03A      1.61A
[Pullup]
| voltage   I(typ)   I(min)   I(max)
-1.8V     1.73A      1.82A      1.67A
-900mV    320mA      470mA      270mA
-800mV    190mA      330mA      150mA
-700mV    98.83mA    210mA      93.56mA
-500mV    55.36mA    53.96mA    61.64mA
700mV     -46.87mA   -38.55mA   -57.34mA
2.4V      -70.84mA   -84mA      -88.18mA
2.6V      -95.76mA   -300mA     -94.65mA
2.7V      -180mA     -440mA     -110mA
2.8V      -320mA     -600mA     -160mA
3.1V      -810mA     -1.09A     -600mA
3.6V      -1.67A     -1.93A     -1.45A
[Ramp]
| variable   typ   min   max
dV/dt_r   0.80/0.65n   0.70/0.91n   0.88/0.45n
dV/dt_f   0.90/0.36n   0.81/0.57n   0.98/0.27n
R_load = 50.00
[Rising Waveform]
R_fixture = 50.00
V_fixture = 0.000
| time   V(typ)   V(min)   V(max)
0s        120mV      140mV      120mV
600ps     120mV      140mV      150mV
800ps     140mV      140mV      490mV
1ns       510mV      180mV      900mV
1.2ns     810mV      410mV      1.25V
1.4ns     960mV      630mV      1.45V
1.6ns     1.15V      790mV      1.55V
2ns       1.4V       1V         1.58V
2.8ns     1.45V      1.28V      1.58V
10ns      1.45V      1.31V      1.58V
[Rising Waveform]
R_fixture = 50.00
V_fixture = 1.80
V_fixture_min = 1.70
V_fixture_max = 1.90
| time   V(typ)   V(min)   V(max)
0s        290mV      350mV      270mV
400ps     290mV      350mV      270mV
600ps     290mV      350mV      400mV
800ps     410mV      350mV      1.19V
1ns       1.2V       520mV      1.69V
1.2ns     1.65V      1.09V      1.86V
1.4ns     1.74V      1.43V      1.89V
1.6ns     1.78V      1.62V      1.9V
1.8ns     1.79V      1.67V      1.9V
10ns      1.8V       1.7V       1.9V
[Falling Waveform]
R_fixture = 50.00
V_fixture = 0.000
| time   V(typ)   V(min)   V(max)
0s        1.45V      1.31V      1.58V
600ps     1.45V      1.31V      1.55V
800ps     1.43V      1.31V      1.25V
1ns       1.15V      1.28V      510mV
1.2ns     630mV      1.16V      170mV
1.4ns     310mV      950mV      140mV
1.8ns     150mV      360mV      120mV
2ns       140mV      240mV      120mV
2.4ns     130mV      180mV      120mV
10ns      120mV      140mV      120mV
[Falling Waveform]
R_fixture = 50.00
V_fixture = 1.80
V_fixture_min = 1.70
V_fixture_max = 1.90
| time   V(typ)   V(min)   V(max)
0s        1.8V       1.7V       1.9V
600ps     1.8V       1.7V       1.91V
800ps     1.81V      1.7V       1.8V
1ns       1.7V       1.71V      1.14V
1.2ns     1.34V      1.68V      460mV
1.6ns     510mV      1.35V      310mV
2ns       350mV      740mV      290mV
2.2ns     330mV      550mV      280mV
2.8ns     300mV      400mV      270mV
10ns      290mV      350mV      270mV
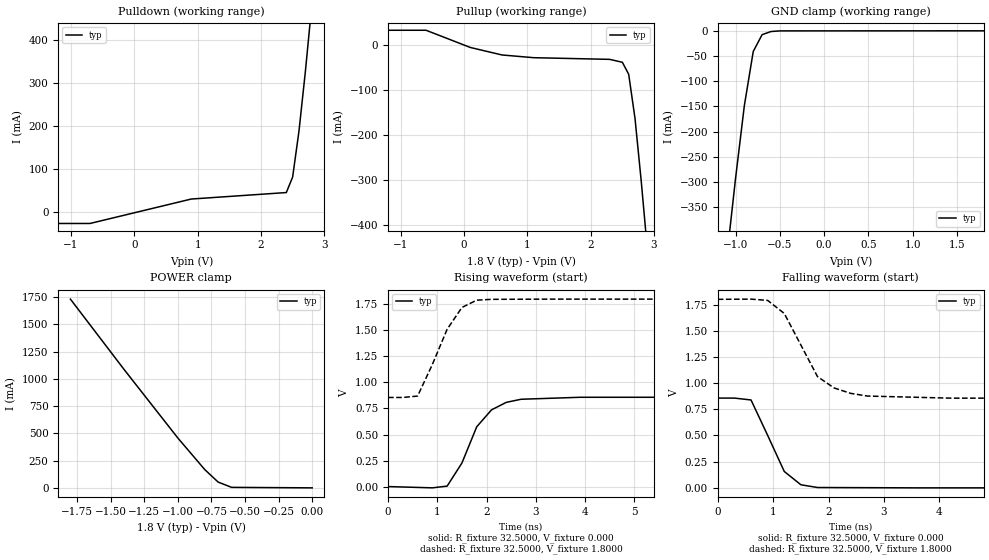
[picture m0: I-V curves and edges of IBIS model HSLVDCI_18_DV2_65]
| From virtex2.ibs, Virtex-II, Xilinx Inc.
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|   Model HSLVDCI_18_DV2_65
[Model]   HSLVDCI_18_DV2_65
Model_type   I/O
Polarity   Non-Inverting
Enable   Active-Low
Vinh = 1.0V
Vinl = 0.8V
Vmeas =   0.90V
Cref =  0pF
Rref =   1.00M
Vref =  0.000V
C_comp   7.0000pF   NA   NA
[Temperature Range]   25.0000   NA   NA
[Voltage Range]   1.8000V   NA   NA
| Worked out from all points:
|   slope of the pulldown table from 0 to 0.27 V, typ, clamps not added: 24.2 ohm
|   slope of the pullup table from 0 to 0.27 V, typ, clamps not added: 22.9 ohm
|   GND clamp passes 1 mA (typ) near -0.57 V on its own axis
|   POWER clamp passes 1 mA (typ) near -0.52 V on its own axis
|   rising waveform, R_fixture 32.5000, V_fixture 0.000: 20-80 % time 581ps typ, NA min, NA max; typ from 0 V to 0.857 V
|   rising waveform, R_fixture 32.5000, V_fixture 1.8000: 20-80 % time 571ps typ, NA min, NA max; typ from 0.856 V to 1.8 V
|   falling waveform, R_fixture 32.5000, V_fixture 0.000: 20-80 % time 451ps typ, NA min, NA max; typ from 0.857 V to 0 V
|   falling waveform, R_fixture 32.5000, V_fixture 1.8000: 20-80 % time 594ps typ, NA min, NA max; typ from 1.8 V to 0.856 V
[Pulldown]
| voltage   I(typ)   I(min)   I(max)
-1.8V     -26.93mA   NA         NA
-700mV    -26.93mA   NA         NA
900mV     30.08mA    NA         NA
2.4V      45.18mA    NA         NA
2.5V      81.2mA     NA         NA
2.6V      188.3mA    NA         NA
2.7V      325.7mA    NA         NA
3V        783.4mA    NA         NA
3.6V      1.746A     NA         NA
[Pullup]
| voltage   I(typ)   I(min)   I(max)
-1.8V     33.63mA    NA         NA
-600mV    33.63mA    NA         NA
100mV     -4.789mA   NA         NA
600mV     -21.48mA   NA         NA
1.1V      -27.55mA   NA         NA
2.3V      -31.27mA   NA         NA
2.5V      -37.8mA    NA         NA
2.6V      -64.55mA   NA         NA
2.7V      -163.2mA   NA         NA
2.8V      -305.8mA   NA         NA
2.9V      -463.4mA   NA         NA
3.6V      -1.659A    NA         NA
[GND_clamp]
| voltage   I(typ)   I(min)   I(max)
-1.8V     -1.649A    NA         NA
-1.1V     -452.1mA   NA         NA
-1V       -293.4mA   NA         NA
-900mV    -148mA     NA         NA
-800mV    -41.01mA   NA         NA
-700mV    -7.602mA   NA         NA
-600mV    -1.419mA   NA         NA
-500mV    -128.9uA   NA         NA
1.8V      272.1nA    NA         NA
[POWER_clamp]
| voltage   I(typ)   I(min)   I(max)
-1.8V     1.731A     NA         NA
-1.4V     1.085A     NA         NA
-1V       456.9mA    NA         NA
-800mV    167.8mA    NA         NA
-700mV    52.78mA    NA         NA
-600mV    4.607mA    NA         NA
0V        272.1nA    NA         NA
[Ramp]
| variable   typ   min   max
dV/dt_r   0.5143/0.6086n   NA   NA
dV/dt_f   0.5666/0.6508n   NA   NA
R_load = 32.5000
[Rising Waveform]
R_fixture = 32.5000
V_fixture = 0.000
| time   V(typ)   V(min)   V(max)
0s        5.077uV    NA         NA
900ps     -12.41mV   NA         NA
1.2ns     4.533mV    NA         NA
1.5ns     226.3mV    NA         NA
1.8ns     573.8mV    NA         NA
2.1ns     736.4mV    NA         NA
2.4ns     808.6mV    NA         NA
2.7ns     838.4mV    NA         NA
3.9ns     857.5mV    NA         NA
15ns      857.1mV    NA         NA
[Rising Waveform]
R_fixture = 32.5000
V_fixture = 1.8000
V_fixture_min = 1.7000
V_fixture_max = 1.9000
| time   V(typ)   V(min)   V(max)
0s        855.6mV    NA         NA
300ps     855.6mV    NA         NA
600ps     869.2mV    NA         NA
900ps     1.173V     NA         NA
1.2ns     1.511V     NA         NA
1.5ns     1.72V      NA         NA
1.8ns     1.79V      NA         NA
2.1ns     1.798V     NA         NA
3.3ns     1.8V       NA         NA
15ns      1.8V       NA         NA
[Falling Waveform]
R_fixture = 32.5000
V_fixture = 0.000
| time   V(typ)   V(min)   V(max)
0s        857.1mV    NA         NA
300ps     857.1mV    NA         NA
600ps     839.2mV    NA         NA
900ps     501.4mV    NA         NA
1.2ns     156.4mV    NA         NA
1.5ns     29.45mV    NA         NA
1.8ns     3.333mV    NA         NA
3.6ns     49.76uV    NA         NA
15ns      -2.387uV   NA         NA
[Falling Waveform]
R_fixture = 32.5000
V_fixture = 1.8000
V_fixture_min = 1.7000
V_fixture_max = 1.9000
| time   V(typ)   V(min)   V(max)
0s        1.8V       NA         NA
600ps     1.802V     NA         NA
900ps     1.79V      NA         NA
1.2ns     1.665V     NA         NA
1.8ns     1.062V     NA         NA
2.1ns     953.6mV    NA         NA
2.4ns     902mV      NA         NA
2.7ns     876.6mV    NA         NA
4.2ns     856.6mV    NA         NA
15ns      855.6mV    NA         NA
